VERSION 5.8 ;
BUSBITCHARS "[]" ;
DIVIDERCHAR "/" ;
UNITS
    DATABASE MICRONS 1000 ;
END UNITS

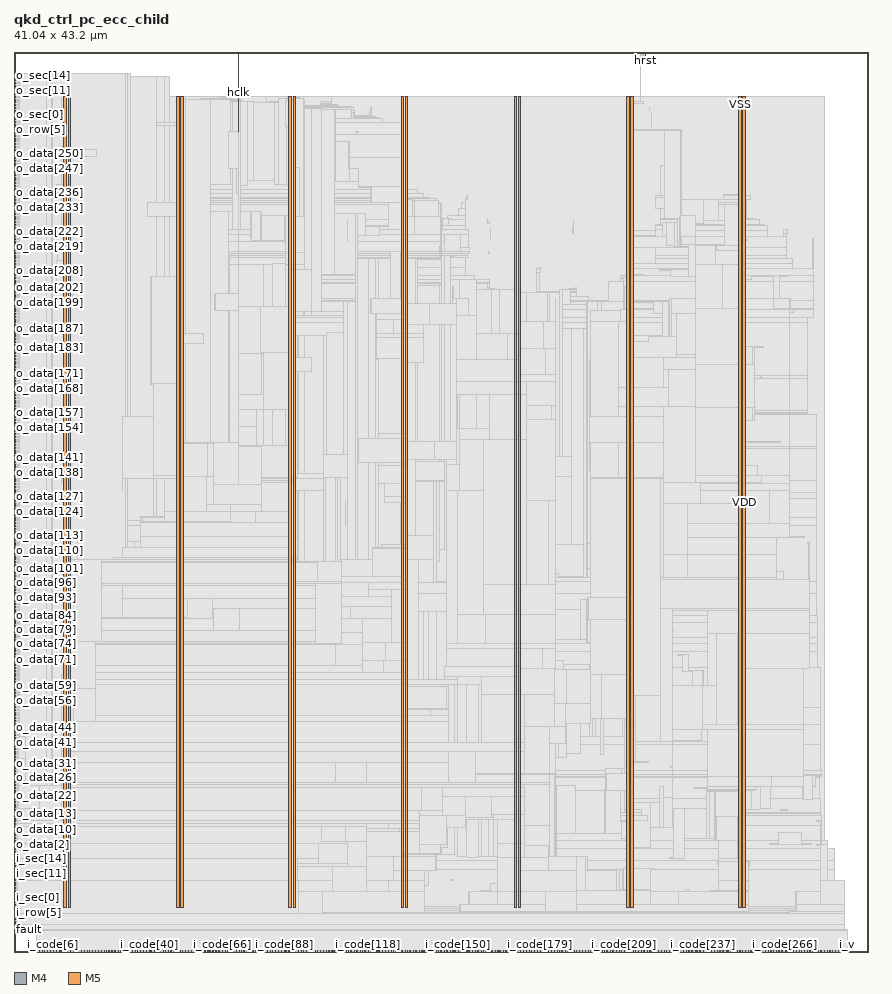
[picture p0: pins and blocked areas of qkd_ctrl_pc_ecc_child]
MACRO qkd_ctrl_pc_ecc_child
  FOREIGN qkd_ctrl_pc_ecc_child 0 0 ;
  CLASS BLOCK ;
  SIZE 41.04 BY 43.2 ;
  PIN fault
    DIRECTION OUTPUT ;
    USE SIGNAL ;
    PORT
      LAYER M4 ;
        RECT  0 1.056 0.084 1.08 ;
    END
  END fault
  PIN hclk
    DIRECTION INPUT ;
    USE SIGNAL ;
    PORT
      LAYER M5 ;
        RECT  10.752 43.116 10.776 43.2 ;
    END
    PORT
      LAYER M5 ;
        RECT  10.752 39.395 10.776 43.152 ;
    END
  END hclk
  PIN hrst
    DIRECTION INPUT ;
    USE SIGNAL ;
    PORT
      LAYER M5 ;
        RECT  30.288 43.116 30.312 43.2 ;
    END
    PORT
      LAYER M5 ;
        RECT  30.288 43.045 30.312 43.152 ;
    END
  END hrst
  PIN i_code[0]
    DIRECTION INPUT ;
    USE SIGNAL ;
    PORT
      LAYER M5 ;
        RECT  1.056 0 1.08 0.084 ;
    END
  END i_code[0]
  PIN i_code[100]
    DIRECTION INPUT ;
    USE SIGNAL ;
    PORT
      LAYER M5 ;
        RECT  14.544 0 14.568 0.084 ;
    END
  END i_code[100]
  PIN i_code[101]
    DIRECTION INPUT ;
    USE SIGNAL ;
    PORT
      LAYER M5 ;
        RECT  14.688 0 14.712 0.084 ;
    END
  END i_code[101]
  PIN i_code[102]
    DIRECTION INPUT ;
    USE SIGNAL ;
    PORT
      LAYER M5 ;
        RECT  14.832 0 14.856 0.084 ;
    END
  END i_code[102]
  PIN i_code[103]
    DIRECTION INPUT ;
    USE SIGNAL ;
    PORT
      LAYER M5 ;
        RECT  14.976 0 15 0.084 ;
    END
  END i_code[103]
  PIN i_code[104]
    DIRECTION INPUT ;
    USE SIGNAL ;
    PORT
      LAYER M5 ;
        RECT  15.12 0 15.144 0.084 ;
    END
  END i_code[104]
  PIN i_code[105]
    DIRECTION INPUT ;
    USE SIGNAL ;
    PORT
      LAYER M5 ;
        RECT  15.264 0 15.288 0.084 ;
    END
  END i_code[105]
  PIN i_code[106]
    DIRECTION INPUT ;
    USE SIGNAL ;
    PORT
      LAYER M5 ;
        RECT  15.36 0 15.384 0.084 ;
    END
  END i_code[106]
  PIN i_code[107]
    DIRECTION INPUT ;
    USE SIGNAL ;
    PORT
      LAYER M5 ;
        RECT  15.504 0 15.528 0.084 ;
    END
  END i_code[107]
  PIN i_code[108]
    DIRECTION INPUT ;
    USE SIGNAL ;
    PORT
      LAYER M5 ;
        RECT  15.648 0 15.672 0.084 ;
    END
  END i_code[108]
  PIN i_code[109]
    DIRECTION INPUT ;
    USE SIGNAL ;
    PORT
      LAYER M5 ;
        RECT  15.792 0 15.816 0.084 ;
    END
  END i_code[109]
  PIN i_code[10]
    DIRECTION INPUT ;
    USE SIGNAL ;
    PORT
      LAYER M5 ;
        RECT  2.4 0 2.424 0.084 ;
    END
  END i_code[10]
  PIN i_code[110]
    DIRECTION INPUT ;
    USE SIGNAL ;
    PORT
      LAYER M5 ;
        RECT  15.936 0 15.96 0.084 ;
    END
  END i_code[110]
  PIN i_code[111]
    DIRECTION INPUT ;
    USE SIGNAL ;
    PORT
      LAYER M5 ;
        RECT  16.032 0 16.056 0.084 ;
    END
  END i_code[111]
  PIN i_code[112]
    DIRECTION INPUT ;
    USE SIGNAL ;
    PORT
      LAYER M5 ;
        RECT  16.176 0 16.2 0.084 ;
    END
  END i_code[112]
  PIN i_code[113]
    DIRECTION INPUT ;
    USE SIGNAL ;
    PORT
      LAYER M5 ;
        RECT  16.32 0 16.344 0.084 ;
    END
  END i_code[113]
  PIN i_code[114]
    DIRECTION INPUT ;
    USE SIGNAL ;
    PORT
      LAYER M5 ;
        RECT  16.464 0 16.488 0.084 ;
    END
  END i_code[114]
  PIN i_code[115]
    DIRECTION INPUT ;
    USE SIGNAL ;
    PORT
      LAYER M5 ;
        RECT  16.608 0 16.632 0.084 ;
    END
  END i_code[115]
  PIN i_code[116]
    DIRECTION INPUT ;
    USE SIGNAL ;
    PORT
      LAYER M5 ;
        RECT  16.704 0 16.728 0.084 ;
    END
  END i_code[116]
  PIN i_code[117]
    DIRECTION INPUT ;
    USE SIGNAL ;
    PORT
      LAYER M5 ;
        RECT  16.848 0 16.872 0.084 ;
    END
  END i_code[117]
  PIN i_code[118]
    DIRECTION INPUT ;
    USE SIGNAL ;
    PORT
      LAYER M5 ;
        RECT  16.992 0 17.016 0.084 ;
    END
  END i_code[118]
  PIN i_code[119]
    DIRECTION INPUT ;
    USE SIGNAL ;
    PORT
      LAYER M5 ;
        RECT  17.136 0 17.16 0.084 ;
    END
  END i_code[119]
  PIN i_code[11]
    DIRECTION INPUT ;
    USE SIGNAL ;
    PORT
      LAYER M5 ;
        RECT  2.544 0 2.568 0.084 ;
    END
  END i_code[11]
  PIN i_code[120]
    DIRECTION INPUT ;
    USE SIGNAL ;
    PORT
      LAYER M5 ;
        RECT  17.28 0 17.304 0.084 ;
    END
  END i_code[120]
  PIN i_code[121]
    DIRECTION INPUT ;
    USE SIGNAL ;
    PORT
      LAYER M5 ;
        RECT  17.424 0 17.448 0.084 ;
    END
  END i_code[121]
  PIN i_code[122]
    DIRECTION INPUT ;
    USE SIGNAL ;
    PORT
      LAYER M5 ;
        RECT  17.52 0 17.544 0.084 ;
    END
  END i_code[122]
  PIN i_code[123]
    DIRECTION INPUT ;
    USE SIGNAL ;
    PORT
      LAYER M5 ;
        RECT  17.664 0 17.688 0.084 ;
    END
  END i_code[123]
  PIN i_code[124]
    DIRECTION INPUT ;
    USE SIGNAL ;
    PORT
      LAYER M5 ;
        RECT  17.808 0 17.832 0.084 ;
    END
  END i_code[124]
  PIN i_code[125]
    DIRECTION INPUT ;
    USE SIGNAL ;
    PORT
      LAYER M5 ;
        RECT  17.952 0 17.976 0.084 ;
    END
  END i_code[125]
  PIN i_code[126]
    DIRECTION INPUT ;
    USE SIGNAL ;
    PORT
      LAYER M5 ;
        RECT  18.096 0 18.12 0.084 ;
    END
  END i_code[126]
  PIN i_code[127]
    DIRECTION INPUT ;
    USE SIGNAL ;
    PORT
      LAYER M5 ;
        RECT  18.192 0 18.216 0.084 ;
    END
  END i_code[127]
  PIN i_code[128]
    DIRECTION INPUT ;
    USE SIGNAL ;
    PORT
      LAYER M5 ;
        RECT  18.336 0 18.36 0.084 ;
    END
  END i_code[128]
  PIN i_code[129]
    DIRECTION INPUT ;
    USE SIGNAL ;
    PORT
      LAYER M5 ;
        RECT  18.48 0 18.504 0.084 ;
    END
  END i_code[129]
  PIN i_code[12]
    DIRECTION INPUT ;
    USE SIGNAL ;
    PORT
      LAYER M5 ;
        RECT  2.688 0 2.712 0.084 ;
    END
  END i_code[12]
  PIN i_code[130]
    DIRECTION INPUT ;
    USE SIGNAL ;
    PORT
      LAYER M5 ;
        RECT  18.624 0 18.648 0.084 ;
    END
  END i_code[130]
  PIN i_code[131]
    DIRECTION INPUT ;
    USE SIGNAL ;
    PORT
      LAYER M5 ;
        RECT  18.768 0 18.792 0.084 ;
    END
  END i_code[131]
  PIN i_code[132]
    DIRECTION INPUT ;
    USE SIGNAL ;
    PORT
      LAYER M5 ;
        RECT  18.864 0 18.888 0.084 ;
    END
  END i_code[132]
  PIN i_code[133]
    DIRECTION INPUT ;
    USE SIGNAL ;
    PORT
      LAYER M5 ;
        RECT  19.008 0 19.032 0.084 ;
    END
  END i_code[133]
  PIN i_code[134]
    DIRECTION INPUT ;
    USE SIGNAL ;
    PORT
      LAYER M5 ;
        RECT  19.152 0 19.176 0.084 ;
    END
  END i_code[134]
  PIN i_code[135]
    DIRECTION INPUT ;
    USE SIGNAL ;
    PORT
      LAYER M5 ;
        RECT  19.296 0 19.32 0.084 ;
    END
  END i_code[135]
  PIN i_code[136]
    DIRECTION INPUT ;
    USE SIGNAL ;
    PORT
      LAYER M5 ;
        RECT  19.44 0 19.464 0.084 ;
    END
  END i_code[136]
  PIN i_code[137]
    DIRECTION INPUT ;
    USE SIGNAL ;
    PORT
      LAYER M5 ;
        RECT  19.584 0 19.608 0.084 ;
    END
  END i_code[137]
  PIN i_code[138]
    DIRECTION INPUT ;
    USE SIGNAL ;
    PORT
      LAYER M5 ;
        RECT  19.68 0 19.704 0.084 ;
    END
  END i_code[138]
  PIN i_code[139]
    DIRECTION INPUT ;
    USE SIGNAL ;
    PORT
      LAYER M5 ;
        RECT  19.824 0 19.848 0.084 ;
    END
  END i_code[139]
  PIN i_code[13]
    DIRECTION INPUT ;
    USE SIGNAL ;
    PORT
      LAYER M5 ;
        RECT  2.832 0 2.856 0.084 ;
    END
  END i_code[13]
  PIN i_code[140]
    DIRECTION INPUT ;
    USE SIGNAL ;
    PORT
      LAYER M5 ;
        RECT  19.968 0 19.992 0.084 ;
    END
  END i_code[140]
  PIN i_code[141]
    DIRECTION INPUT ;
    USE SIGNAL ;
    PORT
      LAYER M5 ;
        RECT  20.112 0 20.136 0.084 ;
    END
  END i_code[141]
  PIN i_code[142]
    DIRECTION INPUT ;
    USE SIGNAL ;
    PORT
      LAYER M5 ;
        RECT  20.256 0 20.28 0.084 ;
    END
  END i_code[142]
  PIN i_code[143]
    DIRECTION INPUT ;
    USE SIGNAL ;
    PORT
      LAYER M5 ;
        RECT  20.352 0 20.376 0.084 ;
    END
  END i_code[143]
  PIN i_code[144]
    DIRECTION INPUT ;
    USE SIGNAL ;
    PORT
      LAYER M5 ;
        RECT  20.496 0 20.52 0.084 ;
    END
  END i_code[144]
  PIN i_code[145]
    DIRECTION INPUT ;
    USE SIGNAL ;
    PORT
      LAYER M5 ;
        RECT  20.64 0 20.664 0.084 ;
    END
  END i_code[145]
  PIN i_code[146]
    DIRECTION INPUT ;
    USE SIGNAL ;
    PORT
      LAYER M5 ;
        RECT  20.784 0 20.808 0.084 ;
    END
  END i_code[146]
  PIN i_code[147]
    DIRECTION INPUT ;
    USE SIGNAL ;
    PORT
      LAYER M5 ;
        RECT  20.928 0 20.952 0.084 ;
    END
  END i_code[147]
  PIN i_code[148]
    DIRECTION INPUT ;
    USE SIGNAL ;
    PORT
      LAYER M5 ;
        RECT  21.072 0 21.096 0.084 ;
    END
  END i_code[148]
  PIN i_code[149]
    DIRECTION INPUT ;
    USE SIGNAL ;
    PORT
      LAYER M5 ;
        RECT  21.168 0 21.192 0.084 ;
    END
  END i_code[149]
  PIN i_code[14]
    DIRECTION INPUT ;
    USE SIGNAL ;
    PORT
      LAYER M5 ;
        RECT  2.928 0 2.952 0.084 ;
    END
  END i_code[14]
  PIN i_code[150]
    DIRECTION INPUT ;
    USE SIGNAL ;
    PORT
      LAYER M5 ;
        RECT  21.312 0 21.336 0.084 ;
    END
  END i_code[150]
  PIN i_code[151]
    DIRECTION INPUT ;
    USE SIGNAL ;
    PORT
      LAYER M5 ;
        RECT  21.456 0 21.48 0.084 ;
    END
  END i_code[151]
  PIN i_code[152]
    DIRECTION INPUT ;
    USE SIGNAL ;
    PORT
      LAYER M5 ;
        RECT  21.6 0 21.624 0.084 ;
    END
  END i_code[152]
  PIN i_code[153]
    DIRECTION INPUT ;
    USE SIGNAL ;
    PORT
      LAYER M5 ;
        RECT  21.744 0 21.768 0.084 ;
    END
  END i_code[153]
  PIN i_code[154]
    DIRECTION INPUT ;
    USE SIGNAL ;
    PORT
      LAYER M5 ;
        RECT  21.84 0 21.864 0.084 ;
    END
  END i_code[154]
  PIN i_code[155]
    DIRECTION INPUT ;
    USE SIGNAL ;
    PORT
      LAYER M5 ;
        RECT  21.984 0 22.008 0.084 ;
    END
  END i_code[155]
  PIN i_code[156]
    DIRECTION INPUT ;
    USE SIGNAL ;
    PORT
      LAYER M5 ;
        RECT  22.128 0 22.152 0.084 ;
    END
  END i_code[156]
  PIN i_code[157]
    DIRECTION INPUT ;
    USE SIGNAL ;
    PORT
      LAYER M5 ;
        RECT  22.272 0 22.296 0.084 ;
    END
  END i_code[157]
  PIN i_code[158]
    DIRECTION INPUT ;
    USE SIGNAL ;
    PORT
      LAYER M5 ;
        RECT  22.416 0 22.44 0.084 ;
    END
  END i_code[158]
  PIN i_code[159]
    DIRECTION INPUT ;
    USE SIGNAL ;
    PORT
      LAYER M5 ;
        RECT  22.512 0 22.536 0.084 ;
    END
  END i_code[159]
  PIN i_code[15]
    DIRECTION INPUT ;
    USE SIGNAL ;
    PORT
      LAYER M5 ;
        RECT  3.072 0 3.096 0.084 ;
    END
  END i_code[15]
  PIN i_code[160]
    DIRECTION INPUT ;
    USE SIGNAL ;
    PORT
      LAYER M5 ;
        RECT  22.656 0 22.68 0.084 ;
    END
  END i_code[160]
  PIN i_code[161]
    DIRECTION INPUT ;
    USE SIGNAL ;
    PORT
      LAYER M5 ;
        RECT  22.8 0 22.824 0.084 ;
    END
  END i_code[161]
  PIN i_code[162]
    DIRECTION INPUT ;
    USE SIGNAL ;
    PORT
      LAYER M5 ;
        RECT  22.944 0 22.968 0.084 ;
    END
  END i_code[162]
  PIN i_code[163]
    DIRECTION INPUT ;
    USE SIGNAL ;
    PORT
      LAYER M5 ;
        RECT  23.088 0 23.112 0.084 ;
    END
  END i_code[163]
  PIN i_code[164]
    DIRECTION INPUT ;
    USE SIGNAL ;
    PORT
      LAYER M5 ;
        RECT  23.232 0 23.256 0.084 ;
    END
  END i_code[164]
  PIN i_code[165]
    DIRECTION INPUT ;
    USE SIGNAL ;
    PORT
      LAYER M5 ;
        RECT  23.328 0 23.352 0.084 ;
    END
  END i_code[165]
  PIN i_code[166]
    DIRECTION INPUT ;
    USE SIGNAL ;
    PORT
      LAYER M5 ;
        RECT  23.472 0 23.496 0.084 ;
    END
  END i_code[166]
  PIN i_code[167]
    DIRECTION INPUT ;
    USE SIGNAL ;
    PORT
      LAYER M5 ;
        RECT  23.616 0 23.64 0.084 ;
    END
  END i_code[167]
  PIN i_code[168]
    DIRECTION INPUT ;
    USE SIGNAL ;
    PORT
      LAYER M5 ;
        RECT  23.76 0 23.784 0.084 ;
    END
  END i_code[168]
  PIN i_code[169]
    DIRECTION INPUT ;
    USE SIGNAL ;
    PORT
      LAYER M5 ;
        RECT  23.904 0 23.928 0.084 ;
    END
  END i_code[169]
  PIN i_code[16]
    DIRECTION INPUT ;
    USE SIGNAL ;
    PORT
      LAYER M5 ;
        RECT  3.216 0 3.24 0.084 ;
    END
  END i_code[16]
  PIN i_code[170]
    DIRECTION INPUT ;
    USE SIGNAL ;
    PORT
      LAYER M5 ;
        RECT  24 0 24.024 0.084 ;
    END
  END i_code[170]
  PIN i_code[171]
    DIRECTION INPUT ;
    USE SIGNAL ;
    PORT
      LAYER M5 ;
        RECT  24.144 0 24.168 0.084 ;
    END
  END i_code[171]
  PIN i_code[172]
    DIRECTION INPUT ;
    USE SIGNAL ;
    PORT
      LAYER M5 ;
        RECT  24.288 0 24.312 0.084 ;
    END
  END i_code[172]
  PIN i_code[173]
    DIRECTION INPUT ;
    USE SIGNAL ;
    PORT
      LAYER M5 ;
        RECT  24.432 0 24.456 0.084 ;
    END
  END i_code[173]
  PIN i_code[174]
    DIRECTION INPUT ;
    USE SIGNAL ;
    PORT
      LAYER M5 ;
        RECT  24.576 0 24.6 0.084 ;
    END
  END i_code[174]
  PIN i_code[175]
    DIRECTION INPUT ;
    USE SIGNAL ;
    PORT
      LAYER M5 ;
        RECT  24.72 0 24.744 0.084 ;
    END
  END i_code[175]
  PIN i_code[176]
    DIRECTION INPUT ;
    USE SIGNAL ;
    PORT
      LAYER M5 ;
        RECT  24.816 0 24.84 0.084 ;
    END
  END i_code[176]
  PIN i_code[177]
    DIRECTION INPUT ;
    USE SIGNAL ;
    PORT
      LAYER M5 ;
        RECT  24.96 0 24.984 0.084 ;
    END
  END i_code[177]
  PIN i_code[178]
    DIRECTION INPUT ;
    USE SIGNAL ;
    PORT
      LAYER M5 ;
        RECT  25.104 0 25.128 0.084 ;
    END
  END i_code[178]
  PIN i_code[179]
    DIRECTION INPUT ;
    USE SIGNAL ;
    PORT
      LAYER M5 ;
        RECT  25.248 0 25.272 0.084 ;
    END
  END i_code[179]
  PIN i_code[17]
    DIRECTION INPUT ;
    USE SIGNAL ;
    PORT
      LAYER M5 ;
        RECT  3.36 0 3.384 0.084 ;
    END
  END i_code[17]
  PIN i_code[180]
    DIRECTION INPUT ;
    USE SIGNAL ;
    PORT
      LAYER M5 ;
        RECT  25.392 0 25.416 0.084 ;
    END
  END i_code[180]
  PIN i_code[181]
    DIRECTION INPUT ;
    USE SIGNAL ;
    PORT
      LAYER M5 ;
        RECT  25.488 0 25.512 0.084 ;
    END
  END i_code[181]
  PIN i_code[182]
    DIRECTION INPUT ;
    USE SIGNAL ;
    PORT
      LAYER M5 ;
        RECT  25.632 0 25.656 0.084 ;
    END
  END i_code[182]
  PIN i_code[183]
    DIRECTION INPUT ;
    USE SIGNAL ;
    PORT
      LAYER M5 ;
        RECT  25.776 0 25.8 0.084 ;
    END
  END i_code[183]
  PIN i_code[184]
    DIRECTION INPUT ;
    USE SIGNAL ;
    PORT
      LAYER M5 ;
        RECT  25.92 0 25.944 0.084 ;
    END
  END i_code[184]
  PIN i_code[185]
    DIRECTION INPUT ;
    USE SIGNAL ;
    PORT
      LAYER M5 ;
        RECT  26.064 0 26.088 0.084 ;
    END
  END i_code[185]
  PIN i_code[186]
    DIRECTION INPUT ;
    USE SIGNAL ;
    PORT
      LAYER M5 ;
        RECT  26.16 0 26.184 0.084 ;
    END
  END i_code[186]
  PIN i_code[187]
    DIRECTION INPUT ;
    USE SIGNAL ;
    PORT
      LAYER M5 ;
        RECT  26.304 0 26.328 0.084 ;
    END
  END i_code[187]
  PIN i_code[188]
    DIRECTION INPUT ;
    USE SIGNAL ;
    PORT
      LAYER M5 ;
        RECT  26.448 0 26.472 0.084 ;
    END
  END i_code[188]
  PIN i_code[189]
    DIRECTION INPUT ;
    USE SIGNAL ;
    PORT
      LAYER M5 ;
        RECT  26.592 0 26.616 0.084 ;
    END
  END i_code[189]
  PIN i_code[18]
    DIRECTION INPUT ;
    USE SIGNAL ;
    PORT
      LAYER M5 ;
        RECT  3.504 0 3.528 0.084 ;
    END
  END i_code[18]
  PIN i_code[190]
    DIRECTION INPUT ;
    USE SIGNAL ;
    PORT
      LAYER M5 ;
        RECT  26.736 0 26.76 0.084 ;
    END
  END i_code[190]
  PIN i_code[191]
    DIRECTION INPUT ;
    USE SIGNAL ;
    PORT
      LAYER M5 ;
        RECT  26.88 0 26.904 0.084 ;
    END
  END i_code[191]
  PIN i_code[192]
    DIRECTION INPUT ;
    USE SIGNAL ;
    PORT
      LAYER M5 ;
        RECT  26.976 0 27 0.084 ;
    END
  END i_code[192]
  PIN i_code[193]
    DIRECTION INPUT ;
    USE SIGNAL ;
    PORT
      LAYER M5 ;
        RECT  27.12 0 27.144 0.084 ;
    END
  END i_code[193]
  PIN i_code[194]
    DIRECTION INPUT ;
    USE SIGNAL ;
    PORT
      LAYER M5 ;
        RECT  27.264 0 27.288 0.084 ;
    END
  END i_code[194]
  PIN i_code[195]
    DIRECTION INPUT ;
    USE SIGNAL ;
    PORT
      LAYER M5 ;
        RECT  27.408 0 27.432 0.084 ;
    END
  END i_code[195]
  PIN i_code[196]
    DIRECTION INPUT ;
    USE SIGNAL ;
    PORT
      LAYER M5 ;
        RECT  27.552 0 27.576 0.084 ;
    END
  END i_code[196]
  PIN i_code[197]
    DIRECTION INPUT ;
    USE SIGNAL ;
    PORT
      LAYER M5 ;
        RECT  27.648 0 27.672 0.084 ;
    END
  END i_code[197]
  PIN i_code[198]
    DIRECTION INPUT ;
    USE SIGNAL ;
    PORT
      LAYER M5 ;
        RECT  27.792 0 27.816 0.084 ;
    END
  END i_code[198]
  PIN i_code[199]
    DIRECTION INPUT ;
    USE SIGNAL ;
    PORT
      LAYER M5 ;
        RECT  27.936 0 27.96 0.084 ;
    END
  END i_code[199]
  PIN i_code[19]
    DIRECTION INPUT ;
    USE SIGNAL ;
    PORT
      LAYER M5 ;
        RECT  3.6 0 3.624 0.084 ;
    END
  END i_code[19]
  PIN i_code[1]
    DIRECTION INPUT ;
    USE SIGNAL ;
    PORT
      LAYER M5 ;
        RECT  1.2 0 1.224 0.084 ;
    END
  END i_code[1]
  PIN i_code[200]
    DIRECTION INPUT ;
    USE SIGNAL ;
    PORT
      LAYER M5 ;
        RECT  28.08 0 28.104 0.084 ;
    END
  END i_code[200]
  PIN i_code[201]
    DIRECTION INPUT ;
    USE SIGNAL ;
    PORT
      LAYER M5 ;
        RECT  28.224 0 28.248 0.084 ;
    END
  END i_code[201]
  PIN i_code[202]
    DIRECTION INPUT ;
    USE SIGNAL ;
    PORT
      LAYER M5 ;
        RECT  28.32 0 28.344 0.084 ;
    END
  END i_code[202]
  PIN i_code[203]
    DIRECTION INPUT ;
    USE SIGNAL ;
    PORT
      LAYER M5 ;
        RECT  28.464 0 28.488 0.084 ;
    END
  END i_code[203]
  PIN i_code[204]
    DIRECTION INPUT ;
    USE SIGNAL ;
    PORT
      LAYER M5 ;
        RECT  28.608 0 28.632 0.084 ;
    END
  END i_code[204]
  PIN i_code[205]
    DIRECTION INPUT ;
    USE SIGNAL ;
    PORT
      LAYER M5 ;
        RECT  28.752 0 28.776 0.084 ;
    END
  END i_code[205]
  PIN i_code[206]
    DIRECTION INPUT ;
    USE SIGNAL ;
    PORT
      LAYER M5 ;
        RECT  28.896 0 28.92 0.084 ;
    END
  END i_code[206]
  PIN i_code[207]
    DIRECTION INPUT ;
    USE SIGNAL ;
    PORT
      LAYER M5 ;
        RECT  29.04 0 29.064 0.084 ;
    END
  END i_code[207]
  PIN i_code[208]
    DIRECTION INPUT ;
    USE SIGNAL ;
    PORT
      LAYER M5 ;
        RECT  29.136 0 29.16 0.084 ;
    END
  END i_code[208]
  PIN i_code[209]
    DIRECTION INPUT ;
    USE SIGNAL ;
    PORT
      LAYER M5 ;
        RECT  29.28 0 29.304 0.084 ;
    END
  END i_code[209]
  PIN i_code[20]
    DIRECTION INPUT ;
    USE SIGNAL ;
    PORT
      LAYER M5 ;
        RECT  3.744 0 3.768 0.084 ;
    END
  END i_code[20]
  PIN i_code[210]
    DIRECTION INPUT ;
    USE SIGNAL ;
    PORT
      LAYER M5 ;
        RECT  29.424 0 29.448 0.084 ;
    END
  END i_code[210]
  PIN i_code[211]
    DIRECTION INPUT ;
    USE SIGNAL ;
    PORT
      LAYER M5 ;
        RECT  29.568 0 29.592 0.084 ;
    END
  END i_code[211]
  PIN i_code[212]
    DIRECTION INPUT ;
    USE SIGNAL ;
    PORT
      LAYER M5 ;
        RECT  29.712 0 29.736 0.084 ;
    END
  END i_code[212]
  PIN i_code[213]
    DIRECTION INPUT ;
    USE SIGNAL ;
    PORT
      LAYER M5 ;
        RECT  29.808 0 29.832 0.084 ;
    END
  END i_code[213]
  PIN i_code[214]
    DIRECTION INPUT ;
    USE SIGNAL ;
    PORT
      LAYER M5 ;
        RECT  29.952 0 29.976 0.084 ;
    END
  END i_code[214]
  PIN i_code[215]
    DIRECTION INPUT ;
    USE SIGNAL ;
    PORT
      LAYER M5 ;
        RECT  30.096 0 30.12 0.084 ;
    END
  END i_code[215]
  PIN i_code[216]
    DIRECTION INPUT ;
    USE SIGNAL ;
    PORT
      LAYER M5 ;
        RECT  30.24 0 30.264 0.084 ;
    END
  END i_code[216]
  PIN i_code[217]
    DIRECTION INPUT ;
    USE SIGNAL ;
    PORT
      LAYER M5 ;
        RECT  30.384 0 30.408 0.084 ;
    END
  END i_code[217]
  PIN i_code[218]
    DIRECTION INPUT ;
    USE SIGNAL ;
    PORT
      LAYER M5 ;
        RECT  30.528 0 30.552 0.084 ;
    END
  END i_code[218]
  PIN i_code[219]
    DIRECTION INPUT ;
    USE SIGNAL ;
    PORT
      LAYER M5 ;
        RECT  30.624 0 30.648 0.084 ;
    END
  END i_code[219]
  PIN i_code[21]
    DIRECTION INPUT ;
    USE SIGNAL ;
    PORT
      LAYER M5 ;
        RECT  3.888 0 3.912 0.084 ;
    END
  END i_code[21]
  PIN i_code[220]
    DIRECTION INPUT ;
    USE SIGNAL ;
    PORT
      LAYER M5 ;
        RECT  30.768 0 30.792 0.084 ;
    END
  END i_code[220]
  PIN i_code[221]
    DIRECTION INPUT ;
    USE SIGNAL ;
    PORT
      LAYER M5 ;
        RECT  30.912 0 30.936 0.084 ;
    END
  END i_code[221]
  PIN i_code[222]
    DIRECTION INPUT ;
    USE SIGNAL ;
    PORT
      LAYER M5 ;
        RECT  31.056 0 31.08 0.084 ;
    END
  END i_code[222]
  PIN i_code[223]
    DIRECTION INPUT ;
    USE SIGNAL ;
    PORT
      LAYER M5 ;
        RECT  31.2 0 31.224 0.084 ;
    END
  END i_code[223]
  PIN i_code[224]
    DIRECTION INPUT ;
    USE SIGNAL ;
    PORT
      LAYER M5 ;
        RECT  31.296 0 31.32 0.084 ;
    END
  END i_code[224]
  PIN i_code[225]
    DIRECTION INPUT ;
    USE SIGNAL ;
    PORT
      LAYER M5 ;
        RECT  31.44 0 31.464 0.084 ;
    END
  END i_code[225]
  PIN i_code[226]
    DIRECTION INPUT ;
    USE SIGNAL ;
    PORT
      LAYER M5 ;
        RECT  31.584 0 31.608 0.084 ;
    END
  END i_code[226]
  PIN i_code[227]
    DIRECTION INPUT ;
    USE SIGNAL ;
    PORT
      LAYER M5 ;
        RECT  31.728 0 31.752 0.084 ;
    END
  END i_code[227]
  PIN i_code[228]
    DIRECTION INPUT ;
    USE SIGNAL ;
    PORT
      LAYER M5 ;
        RECT  31.872 0 31.896 0.084 ;
    END
  END i_code[228]
  PIN i_code[229]
    DIRECTION INPUT ;
    USE SIGNAL ;
    PORT
      LAYER M5 ;
        RECT  31.968 0 31.992 0.084 ;
    END
  END i_code[229]
  PIN i_code[22]
    DIRECTION INPUT ;
    USE SIGNAL ;
    PORT
      LAYER M5 ;
        RECT  4.032 0 4.056 0.084 ;
    END
  END i_code[22]
  PIN i_code[230]
    DIRECTION INPUT ;
    USE SIGNAL ;
    PORT
      LAYER M5 ;
        RECT  32.112 0 32.136 0.084 ;
    END
  END i_code[230]
  PIN i_code[231]
    DIRECTION INPUT ;
    USE SIGNAL ;
    PORT
      LAYER M5 ;
        RECT  32.256 0 32.28 0.084 ;
    END
  END i_code[231]
  PIN i_code[232]
    DIRECTION INPUT ;
    USE SIGNAL ;
    PORT
      LAYER M5 ;
        RECT  32.4 0 32.424 0.084 ;
    END
  END i_code[232]
  PIN i_code[233]
    DIRECTION INPUT ;
    USE SIGNAL ;
    PORT
      LAYER M5 ;
        RECT  32.544 0 32.568 0.084 ;
    END
  END i_code[233]
  PIN i_code[234]
    DIRECTION INPUT ;
    USE SIGNAL ;
    PORT
      LAYER M5 ;
        RECT  32.688 0 32.712 0.084 ;
    END
  END i_code[234]
  PIN i_code[235]
    DIRECTION INPUT ;
    USE SIGNAL ;
    PORT
      LAYER M5 ;
        RECT  32.784 0 32.808 0.084 ;
    END
  END i_code[235]
  PIN i_code[236]
    DIRECTION INPUT ;
    USE SIGNAL ;
    PORT
      LAYER M5 ;
        RECT  32.928 0 32.952 0.084 ;
    END
  END i_code[236]
  PIN i_code[237]
    DIRECTION INPUT ;
    USE SIGNAL ;
    PORT
      LAYER M5 ;
        RECT  33.072 0 33.096 0.084 ;
    END
  END i_code[237]
  PIN i_code[238]
    DIRECTION INPUT ;
    USE SIGNAL ;
    PORT
      LAYER M5 ;
        RECT  33.216 0 33.24 0.084 ;
    END
  END i_code[238]
  PIN i_code[239]
    DIRECTION INPUT ;
    USE SIGNAL ;
    PORT
      LAYER M5 ;
        RECT  33.36 0 33.384 0.084 ;
    END
  END i_code[239]
  PIN i_code[23]
    DIRECTION INPUT ;
    USE SIGNAL ;
    PORT
      LAYER M5 ;
        RECT  4.176 0 4.2 0.084 ;
    END
  END i_code[23]
  PIN i_code[240]
    DIRECTION INPUT ;
    USE SIGNAL ;
    PORT
      LAYER M5 ;
        RECT  33.456 0 33.48 0.084 ;
    END
  END i_code[240]
  PIN i_code[241]
    DIRECTION INPUT ;
    USE SIGNAL ;
    PORT
      LAYER M5 ;
        RECT  33.6 0 33.624 0.084 ;
    END
  END i_code[241]
  PIN i_code[242]
    DIRECTION INPUT ;
    USE SIGNAL ;
    PORT
      LAYER M5 ;
        RECT  33.744 0 33.768 0.084 ;
    END
  END i_code[242]
  PIN i_code[243]
    DIRECTION INPUT ;
    USE SIGNAL ;
    PORT
      LAYER M5 ;
        RECT  33.888 0 33.912 0.084 ;
    END
  END i_code[243]
  PIN i_code[244]
    DIRECTION INPUT ;
    USE SIGNAL ;
    PORT
      LAYER M5 ;
        RECT  34.032 0 34.056 0.084 ;
    END
  END i_code[244]
  PIN i_code[245]
    DIRECTION INPUT ;
    USE SIGNAL ;
    PORT
      LAYER M5 ;
        RECT  34.176 0 34.2 0.084 ;
    END
  END i_code[245]
  PIN i_code[246]
    DIRECTION INPUT ;
    USE SIGNAL ;
    PORT
      LAYER M5 ;
        RECT  34.272 0 34.296 0.084 ;
    END
  END i_code[246]
  PIN i_code[247]
    DIRECTION INPUT ;
    USE SIGNAL ;
    PORT
      LAYER M5 ;
        RECT  34.416 0 34.44 0.084 ;
    END
  END i_code[247]
  PIN i_code[248]
    DIRECTION INPUT ;
    USE SIGNAL ;
    PORT
      LAYER M5 ;
        RECT  34.56 0 34.584 0.084 ;
    END
  END i_code[248]
  PIN i_code[249]
    DIRECTION INPUT ;
    USE SIGNAL ;
    PORT
      LAYER M5 ;
        RECT  34.704 0 34.728 0.084 ;
    END
  END i_code[249]
  PIN i_code[24]
    DIRECTION INPUT ;
    USE SIGNAL ;
    PORT
      LAYER M5 ;
        RECT  4.32 0 4.344 0.084 ;
    END
  END i_code[24]
  PIN i_code[250]
    DIRECTION INPUT ;
    USE SIGNAL ;
    PORT
      LAYER M5 ;
        RECT  34.848 0 34.872 0.084 ;
    END
  END i_code[250]
  PIN i_code[251]
    DIRECTION INPUT ;
    USE SIGNAL ;
    PORT
      LAYER M5 ;
        RECT  34.944 0 34.968 0.084 ;
    END
  END i_code[251]
  PIN i_code[252]
    DIRECTION INPUT ;
    USE SIGNAL ;
    PORT
      LAYER M5 ;
        RECT  35.088 0 35.112 0.084 ;
    END
  END i_code[252]
  PIN i_code[253]
    DIRECTION INPUT ;
    USE SIGNAL ;
    PORT
      LAYER M5 ;
        RECT  35.232 0 35.256 0.084 ;
    END
  END i_code[253]
  PIN i_code[254]
    DIRECTION INPUT ;
    USE SIGNAL ;
    PORT
      LAYER M5 ;
        RECT  35.376 0 35.4 0.084 ;
    END
  END i_code[254]
  PIN i_code[255]
    DIRECTION INPUT ;
    USE SIGNAL ;
    PORT
      LAYER M5 ;
        RECT  35.52 0 35.544 0.084 ;
    END
  END i_code[255]
  PIN i_code[256]
    DIRECTION INPUT ;
    USE SIGNAL ;
    PORT
      LAYER M5 ;
        RECT  35.616 0 35.64 0.084 ;
    END
  END i_code[256]
  PIN i_code[257]
    DIRECTION INPUT ;
    USE SIGNAL ;
    PORT
      LAYER M5 ;
        RECT  35.76 0 35.784 0.084 ;
    END
  END i_code[257]
  PIN i_code[258]
    DIRECTION INPUT ;
    USE SIGNAL ;
    PORT
      LAYER M5 ;
        RECT  35.904 0 35.928 0.084 ;
    END
  END i_code[258]
  PIN i_code[259]
    DIRECTION INPUT ;
    USE SIGNAL ;
    PORT
      LAYER M5 ;
        RECT  36.048 0 36.072 0.084 ;
    END
  END i_code[259]
  PIN i_code[25]
    DIRECTION INPUT ;
    USE SIGNAL ;
    PORT
      LAYER M5 ;
        RECT  4.416 0 4.44 0.084 ;
    END
  END i_code[25]
  PIN i_code[260]
    DIRECTION INPUT ;
    USE SIGNAL ;
    PORT
      LAYER M5 ;
        RECT  36.192 0 36.216 0.084 ;
    END
  END i_code[260]
  PIN i_code[261]
    DIRECTION INPUT ;
    USE SIGNAL ;
    PORT
      LAYER M5 ;
        RECT  36.336 0 36.36 0.084 ;
    END
  END i_code[261]
  PIN i_code[262]
    DIRECTION INPUT ;
    USE SIGNAL ;
    PORT
      LAYER M5 ;
        RECT  36.432 0 36.456 0.084 ;
    END
  END i_code[262]
  PIN i_code[263]
    DIRECTION INPUT ;
    USE SIGNAL ;
    PORT
      LAYER M5 ;
        RECT  36.576 0 36.6 0.084 ;
    END
  END i_code[263]
  PIN i_code[264]
    DIRECTION INPUT ;
    USE SIGNAL ;
    PORT
      LAYER M5 ;
        RECT  36.72 0 36.744 0.084 ;
    END
  END i_code[264]
  PIN i_code[265]
    DIRECTION INPUT ;
    USE SIGNAL ;
    PORT
      LAYER M5 ;
        RECT  36.864 0 36.888 0.084 ;
    END
  END i_code[265]
  PIN i_code[266]
    DIRECTION INPUT ;
    USE SIGNAL ;
    PORT
      LAYER M5 ;
        RECT  37.008 0 37.032 0.084 ;
    END
  END i_code[266]
  PIN i_code[267]
    DIRECTION INPUT ;
    USE SIGNAL ;
    PORT
      LAYER M5 ;
        RECT  37.104 0 37.128 0.084 ;
    END
  END i_code[267]
  PIN i_code[268]
    DIRECTION INPUT ;
    USE SIGNAL ;
    PORT
      LAYER M5 ;
        RECT  37.248 0 37.272 0.084 ;
    END
  END i_code[268]
  PIN i_code[269]
    DIRECTION INPUT ;
    USE SIGNAL ;
    PORT
      LAYER M5 ;
        RECT  37.392 0 37.416 0.084 ;
    END
  END i_code[269]
  PIN i_code[26]
    DIRECTION INPUT ;
    USE SIGNAL ;
    PORT
      LAYER M5 ;
        RECT  4.56 0 4.584 0.084 ;
    END
  END i_code[26]
  PIN i_code[270]
    DIRECTION INPUT ;
    USE SIGNAL ;
    PORT
      LAYER M5 ;
        RECT  37.536 0 37.56 0.084 ;
    END
  END i_code[270]
  PIN i_code[271]
    DIRECTION INPUT ;
    USE SIGNAL ;
    PORT
      LAYER M5 ;
        RECT  37.68 0 37.704 0.084 ;
    END
  END i_code[271]
  PIN i_code[272]
    DIRECTION INPUT ;
    USE SIGNAL ;
    PORT
      LAYER M5 ;
        RECT  37.776 0 37.8 0.084 ;
    END
  END i_code[272]
  PIN i_code[273]
    DIRECTION INPUT ;
    USE SIGNAL ;
    PORT
      LAYER M5 ;
        RECT  37.92 0 37.944 0.084 ;
    END
  END i_code[273]
  PIN i_code[274]
    DIRECTION INPUT ;
    USE SIGNAL ;
    PORT
      LAYER M5 ;
        RECT  38.064 0 38.088 0.084 ;
    END
  END i_code[274]
  PIN i_code[275]
    DIRECTION INPUT ;
    USE SIGNAL ;
    PORT
      LAYER M5 ;
        RECT  38.208 0 38.232 0.084 ;
    END
  END i_code[275]
  PIN i_code[276]
    DIRECTION INPUT ;
    USE SIGNAL ;
    PORT
      LAYER M5 ;
        RECT  38.352 0 38.376 0.084 ;
    END
  END i_code[276]
  PIN i_code[277]
    DIRECTION INPUT ;
    USE SIGNAL ;
    PORT
      LAYER M5 ;
        RECT  38.496 0 38.52 0.084 ;
    END
  END i_code[277]
  PIN i_code[278]
    DIRECTION INPUT ;
    USE SIGNAL ;
    PORT
      LAYER M5 ;
        RECT  38.592 0 38.616 0.084 ;
    END
  END i_code[278]
  PIN i_code[279]
    DIRECTION INPUT ;
    USE SIGNAL ;
    PORT
      LAYER M5 ;
        RECT  38.736 0 38.76 0.084 ;
    END
  END i_code[279]
  PIN i_code[27]
    DIRECTION INPUT ;
    USE SIGNAL ;
    PORT
      LAYER M5 ;
        RECT  4.704 0 4.728 0.084 ;
    END
  END i_code[27]
  PIN i_code[280]
    DIRECTION INPUT ;
    USE SIGNAL ;
    PORT
      LAYER M5 ;
        RECT  38.88 0 38.904 0.084 ;
    END
  END i_code[280]
  PIN i_code[281]
    DIRECTION INPUT ;
    USE SIGNAL ;
    PORT
      LAYER M5 ;
        RECT  39.024 0 39.048 0.084 ;
    END
  END i_code[281]
  PIN i_code[282]
    DIRECTION INPUT ;
    USE SIGNAL ;
    PORT
      LAYER M5 ;
        RECT  39.168 0 39.192 0.084 ;
    END
  END i_code[282]
  PIN i_code[283]
    DIRECTION INPUT ;
    USE SIGNAL ;
    PORT
      LAYER M5 ;
        RECT  39.264 0 39.288 0.084 ;
    END
  END i_code[283]
  PIN i_code[284]
    DIRECTION INPUT ;
    USE SIGNAL ;
    PORT
      LAYER M5 ;
        RECT  39.408 0 39.432 0.084 ;
    END
  END i_code[284]
  PIN i_code[285]
    DIRECTION INPUT ;
    USE SIGNAL ;
    PORT
      LAYER M5 ;
        RECT  39.552 0 39.576 0.084 ;
    END
  END i_code[285]
  PIN i_code[286]
    DIRECTION INPUT ;
    USE SIGNAL ;
    PORT
      LAYER M5 ;
        RECT  39.696 0 39.72 0.084 ;
    END
  END i_code[286]
  PIN i_code[287]
    DIRECTION INPUT ;
    USE SIGNAL ;
    PORT
      LAYER M5 ;
        RECT  39.84 0 39.864 0.084 ;
    END
  END i_code[287]
  PIN i_code[28]
    DIRECTION INPUT ;
    USE SIGNAL ;
    PORT
      LAYER M5 ;
        RECT  4.848 0 4.872 0.084 ;
    END
  END i_code[28]
  PIN i_code[29]
    DIRECTION INPUT ;
    USE SIGNAL ;
    PORT
      LAYER M5 ;
        RECT  4.992 0 5.016 0.084 ;
    END
  END i_code[29]
  PIN i_code[2]
    DIRECTION INPUT ;
    USE SIGNAL ;
    PORT
      LAYER M5 ;
        RECT  1.344 0 1.368 0.084 ;
    END
  END i_code[2]
  PIN i_code[30]
    DIRECTION INPUT ;
    USE SIGNAL ;
    PORT
      LAYER M5 ;
        RECT  5.088 0 5.112 0.084 ;
    END
  END i_code[30]
  PIN i_code[31]
    DIRECTION INPUT ;
    USE SIGNAL ;
    PORT
      LAYER M5 ;
        RECT  5.232 0 5.256 0.084 ;
    END
  END i_code[31]
  PIN i_code[32]
    DIRECTION INPUT ;
    USE SIGNAL ;
    PORT
      LAYER M5 ;
        RECT  5.376 0 5.4 0.084 ;
    END
  END i_code[32]
  PIN i_code[33]
    DIRECTION INPUT ;
    USE SIGNAL ;
    PORT
      LAYER M5 ;
        RECT  5.52 0 5.544 0.084 ;
    END
  END i_code[33]
  PIN i_code[34]
    DIRECTION INPUT ;
    USE SIGNAL ;
    PORT
      LAYER M5 ;
        RECT  5.664 0 5.688 0.084 ;
    END
  END i_code[34]
  PIN i_code[35]
    DIRECTION INPUT ;
    USE SIGNAL ;
    PORT
      LAYER M5 ;
        RECT  5.808 0 5.832 0.084 ;
    END
  END i_code[35]
  PIN i_code[36]
    DIRECTION INPUT ;
    USE SIGNAL ;
    PORT
      LAYER M5 ;
        RECT  5.904 0 5.928 0.084 ;
    END
  END i_code[36]
  PIN i_code[37]
    DIRECTION INPUT ;
    USE SIGNAL ;
    PORT
      LAYER M5 ;
        RECT  6.048 0 6.072 0.084 ;
    END
  END i_code[37]
  PIN i_code[38]
    DIRECTION INPUT ;
    USE SIGNAL ;
    PORT
      LAYER M5 ;
        RECT  6.192 0 6.216 0.084 ;
    END
  END i_code[38]
  PIN i_code[39]
    DIRECTION INPUT ;
    USE SIGNAL ;
    PORT
      LAYER M5 ;
        RECT  6.336 0 6.36 0.084 ;
    END
  END i_code[39]
  PIN i_code[3]
    DIRECTION INPUT ;
    USE SIGNAL ;
    PORT
      LAYER M5 ;
        RECT  1.44 0 1.464 0.084 ;
    END
  END i_code[3]
  PIN i_code[40]
    DIRECTION INPUT ;
    USE SIGNAL ;
    PORT
      LAYER M5 ;
        RECT  6.48 0 6.504 0.084 ;
    END
  END i_code[40]
  PIN i_code[41]
    DIRECTION INPUT ;
    USE SIGNAL ;
    PORT
      LAYER M5 ;
        RECT  6.576 0 6.6 0.084 ;
    END
  END i_code[41]
  PIN i_code[42]
    DIRECTION INPUT ;
    USE SIGNAL ;
    PORT
      LAYER M5 ;
        RECT  6.72 0 6.744 0.084 ;
    END
  END i_code[42]
  PIN i_code[43]
    DIRECTION INPUT ;
    USE SIGNAL ;
    PORT
      LAYER M5 ;
        RECT  6.864 0 6.888 0.084 ;
    END
  END i_code[43]
  PIN i_code[44]
    DIRECTION INPUT ;
    USE SIGNAL ;
    PORT
      LAYER M5 ;
        RECT  7.008 0 7.032 0.084 ;
    END
  END i_code[44]
  PIN i_code[45]
    DIRECTION INPUT ;
    USE SIGNAL ;
    PORT
      LAYER M5 ;
        RECT  7.152 0 7.176 0.084 ;
    END
  END i_code[45]
  PIN i_code[46]
    DIRECTION INPUT ;
    USE SIGNAL ;
    PORT
      LAYER M5 ;
        RECT  7.248 0 7.272 0.084 ;
    END
  END i_code[46]
  PIN i_code[47]
    DIRECTION INPUT ;
    USE SIGNAL ;
    PORT
      LAYER M5 ;
        RECT  7.392 0 7.416 0.084 ;
    END
  END i_code[47]
  PIN i_code[48]
    DIRECTION INPUT ;
    USE SIGNAL ;
    PORT
      LAYER M5 ;
        RECT  7.536 0 7.56 0.084 ;
    END
  END i_code[48]
  PIN i_code[49]
    DIRECTION INPUT ;
    USE SIGNAL ;
    PORT
      LAYER M5 ;
        RECT  7.68 0 7.704 0.084 ;
    END
  END i_code[49]
  PIN i_code[4]
    DIRECTION INPUT ;
    USE SIGNAL ;
    PORT
      LAYER M5 ;
        RECT  1.584 0 1.608 0.084 ;
    END
  END i_code[4]
  PIN i_code[50]
    DIRECTION INPUT ;
    USE SIGNAL ;
    PORT
      LAYER M5 ;
        RECT  7.824 0 7.848 0.084 ;
    END
  END i_code[50]
  PIN i_code[51]
    DIRECTION INPUT ;
    USE SIGNAL ;
    PORT
      LAYER M5 ;
        RECT  7.968 0 7.992 0.084 ;
    END
  END i_code[51]
  PIN i_code[52]
    DIRECTION INPUT ;
    USE SIGNAL ;
    PORT
      LAYER M5 ;
        RECT  8.064 0 8.088 0.084 ;
    END
  END i_code[52]
  PIN i_code[53]
    DIRECTION INPUT ;
    USE SIGNAL ;
    PORT
      LAYER M5 ;
        RECT  8.208 0 8.232 0.084 ;
    END
  END i_code[53]
  PIN i_code[54]
    DIRECTION INPUT ;
    USE SIGNAL ;
    PORT
      LAYER M5 ;
        RECT  8.352 0 8.376 0.084 ;
    END
  END i_code[54]
  PIN i_code[55]
    DIRECTION INPUT ;
    USE SIGNAL ;
    PORT
      LAYER M5 ;
        RECT  8.496 0 8.52 0.084 ;
    END
  END i_code[55]
  PIN i_code[56]
    DIRECTION INPUT ;
    USE SIGNAL ;
    PORT
      LAYER M5 ;
        RECT  8.64 0 8.664 0.084 ;
    END
  END i_code[56]
  PIN i_code[57]
    DIRECTION INPUT ;
    USE SIGNAL ;
    PORT
      LAYER M5 ;
        RECT  8.736 0 8.76 0.084 ;
    END
  END i_code[57]
  PIN i_code[58]
    DIRECTION INPUT ;
    USE SIGNAL ;
    PORT
      LAYER M5 ;
        RECT  8.88 0 8.904 0.084 ;
    END
  END i_code[58]
  PIN i_code[59]
    DIRECTION INPUT ;
    USE SIGNAL ;
    PORT
      LAYER M5 ;
        RECT  9.024 0 9.048 0.084 ;
    END
  END i_code[59]
  PIN i_code[5]
    DIRECTION INPUT ;
    USE SIGNAL ;
    PORT
      LAYER M5 ;
        RECT  1.728 0 1.752 0.084 ;
    END
  END i_code[5]
  PIN i_code[60]
    DIRECTION INPUT ;
    USE SIGNAL ;
    PORT
      LAYER M5 ;
        RECT  9.168 0 9.192 0.084 ;
    END
  END i_code[60]
  PIN i_code[61]
    DIRECTION INPUT ;
    USE SIGNAL ;
    PORT
      LAYER M5 ;
        RECT  9.312 0 9.336 0.084 ;
    END
  END i_code[61]
  PIN i_code[62]
    DIRECTION INPUT ;
    USE SIGNAL ;
    PORT
      LAYER M5 ;
        RECT  9.408 0 9.432 0.084 ;
    END
  END i_code[62]
  PIN i_code[63]
    DIRECTION INPUT ;
    USE SIGNAL ;
    PORT
      LAYER M5 ;
        RECT  9.552 0 9.576 0.084 ;
    END
  END i_code[63]
  PIN i_code[64]
    DIRECTION INPUT ;
    USE SIGNAL ;
    PORT
      LAYER M5 ;
        RECT  9.696 0 9.72 0.084 ;
    END
  END i_code[64]
  PIN i_code[65]
    DIRECTION INPUT ;
    USE SIGNAL ;
    PORT
      LAYER M5 ;
        RECT  9.84 0 9.864 0.084 ;
    END
  END i_code[65]
  PIN i_code[66]
    DIRECTION INPUT ;
    USE SIGNAL ;
    PORT
      LAYER M5 ;
        RECT  9.984 0 10.008 0.084 ;
    END
  END i_code[66]
  PIN i_code[67]
    DIRECTION INPUT ;
    USE SIGNAL ;
    PORT
      LAYER M5 ;
        RECT  10.128 0 10.152 0.084 ;
    END
  END i_code[67]
  PIN i_code[68]
    DIRECTION INPUT ;
    USE SIGNAL ;
    PORT
      LAYER M5 ;
        RECT  10.224 0 10.248 0.084 ;
    END
  END i_code[68]
  PIN i_code[69]
    DIRECTION INPUT ;
    USE SIGNAL ;
    PORT
      LAYER M5 ;
        RECT  10.368 0 10.392 0.084 ;
    END
  END i_code[69]
  PIN i_code[6]
    DIRECTION INPUT ;
    USE SIGNAL ;
    PORT
      LAYER M5 ;
        RECT  1.872 0 1.896 0.084 ;
    END
  END i_code[6]
  PIN i_code[70]
    DIRECTION INPUT ;
    USE SIGNAL ;
    PORT
      LAYER M5 ;
        RECT  10.512 0 10.536 0.084 ;
    END
  END i_code[70]
  PIN i_code[71]
    DIRECTION INPUT ;
    USE SIGNAL ;
    PORT
      LAYER M5 ;
        RECT  10.656 0 10.68 0.084 ;
    END
  END i_code[71]
  PIN i_code[72]
    DIRECTION INPUT ;
    USE SIGNAL ;
    PORT
      LAYER M5 ;
        RECT  10.8 0 10.824 0.084 ;
    END
  END i_code[72]
  PIN i_code[73]
    DIRECTION INPUT ;
    USE SIGNAL ;
    PORT
      LAYER M5 ;
        RECT  10.896 0 10.92 0.084 ;
    END
  END i_code[73]
  PIN i_code[74]
    DIRECTION INPUT ;
    USE SIGNAL ;
    PORT
      LAYER M5 ;
        RECT  11.04 0 11.064 0.084 ;
    END
  END i_code[74]
  PIN i_code[75]
    DIRECTION INPUT ;
    USE SIGNAL ;
    PORT
      LAYER M5 ;
        RECT  11.184 0 11.208 0.084 ;
    END
  END i_code[75]
  PIN i_code[76]
    DIRECTION INPUT ;
    USE SIGNAL ;
    PORT
      LAYER M5 ;
        RECT  11.328 0 11.352 0.084 ;
    END
  END i_code[76]
  PIN i_code[77]
    DIRECTION INPUT ;
    USE SIGNAL ;
    PORT
      LAYER M5 ;
        RECT  11.472 0 11.496 0.084 ;
    END
  END i_code[77]
  PIN i_code[78]
    DIRECTION INPUT ;
    USE SIGNAL ;
    PORT
      LAYER M5 ;
        RECT  11.616 0 11.64 0.084 ;
    END
  END i_code[78]
  PIN i_code[79]
    DIRECTION INPUT ;
    USE SIGNAL ;
    PORT
      LAYER M5 ;
        RECT  11.712 0 11.736 0.084 ;
    END
  END i_code[79]
  PIN i_code[7]
    DIRECTION INPUT ;
    USE SIGNAL ;
    PORT
      LAYER M5 ;
        RECT  2.016 0 2.04 0.084 ;
    END
  END i_code[7]
  PIN i_code[80]
    DIRECTION INPUT ;
    USE SIGNAL ;
    PORT
      LAYER M5 ;
        RECT  11.856 0 11.88 0.084 ;
    END
  END i_code[80]
  PIN i_code[81]
    DIRECTION INPUT ;
    USE SIGNAL ;
    PORT
      LAYER M5 ;
        RECT  12 0 12.024 0.084 ;
    END
  END i_code[81]
  PIN i_code[82]
    DIRECTION INPUT ;
    USE SIGNAL ;
    PORT
      LAYER M5 ;
        RECT  12.144 0 12.168 0.084 ;
    END
  END i_code[82]
  PIN i_code[83]
    DIRECTION INPUT ;
    USE SIGNAL ;
    PORT
      LAYER M5 ;
        RECT  12.288 0 12.312 0.084 ;
    END
  END i_code[83]
  PIN i_code[84]
    DIRECTION INPUT ;
    USE SIGNAL ;
    PORT
      LAYER M5 ;
        RECT  12.384 0 12.408 0.084 ;
    END
  END i_code[84]
  PIN i_code[85]
    DIRECTION INPUT ;
    USE SIGNAL ;
    PORT
      LAYER M5 ;
        RECT  12.528 0 12.552 0.084 ;
    END
  END i_code[85]
  PIN i_code[86]
    DIRECTION INPUT ;
    USE SIGNAL ;
    PORT
      LAYER M5 ;
        RECT  12.672 0 12.696 0.084 ;
    END
  END i_code[86]
  PIN i_code[87]
    DIRECTION INPUT ;
    USE SIGNAL ;
    PORT
      LAYER M5 ;
        RECT  12.816 0 12.84 0.084 ;
    END
  END i_code[87]
  PIN i_code[88]
    DIRECTION INPUT ;
    USE SIGNAL ;
    PORT
      LAYER M5 ;
        RECT  12.96 0 12.984 0.084 ;
    END
  END i_code[88]
  PIN i_code[89]
    DIRECTION INPUT ;
    USE SIGNAL ;
    PORT
      LAYER M5 ;
        RECT  13.056 0 13.08 0.084 ;
    END
  END i_code[89]
  PIN i_code[8]
    DIRECTION INPUT ;
    USE SIGNAL ;
    PORT
      LAYER M5 ;
        RECT  2.16 0 2.184 0.084 ;
    END
  END i_code[8]
  PIN i_code[90]
    DIRECTION INPUT ;
    USE SIGNAL ;
    PORT
      LAYER M5 ;
        RECT  13.2 0 13.224 0.084 ;
    END
  END i_code[90]
  PIN i_code[91]
    DIRECTION INPUT ;
    USE SIGNAL ;
    PORT
      LAYER M5 ;
        RECT  13.344 0 13.368 0.084 ;
    END
  END i_code[91]
  PIN i_code[92]
    DIRECTION INPUT ;
    USE SIGNAL ;
    PORT
      LAYER M5 ;
        RECT  13.488 0 13.512 0.084 ;
    END
  END i_code[92]
  PIN i_code[93]
    DIRECTION INPUT ;
    USE SIGNAL ;
    PORT
      LAYER M5 ;
        RECT  13.632 0 13.656 0.084 ;
    END
  END i_code[93]
  PIN i_code[94]
    DIRECTION INPUT ;
    USE SIGNAL ;
    PORT
      LAYER M5 ;
        RECT  13.776 0 13.8 0.084 ;
    END
  END i_code[94]
  PIN i_code[95]
    DIRECTION INPUT ;
    USE SIGNAL ;
    PORT
      LAYER M5 ;
        RECT  13.872 0 13.896 0.084 ;
    END
  END i_code[95]
  PIN i_code[96]
    DIRECTION INPUT ;
    USE SIGNAL ;
    PORT
      LAYER M5 ;
        RECT  14.016 0 14.04 0.084 ;
    END
  END i_code[96]
  PIN i_code[97]
    DIRECTION INPUT ;
    USE SIGNAL ;
    PORT
      LAYER M5 ;
        RECT  14.16 0 14.184 0.084 ;
    END
  END i_code[97]
  PIN i_code[98]
    DIRECTION INPUT ;
    USE SIGNAL ;
    PORT
      LAYER M5 ;
        RECT  14.304 0 14.328 0.084 ;
    END
  END i_code[98]
  PIN i_code[99]
    DIRECTION INPUT ;
    USE SIGNAL ;
    PORT
      LAYER M5 ;
        RECT  14.448 0 14.472 0.084 ;
    END
  END i_code[99]
  PIN i_code[9]
    DIRECTION INPUT ;
    USE SIGNAL ;
    PORT
      LAYER M5 ;
        RECT  2.256 0 2.28 0.084 ;
    END
  END i_code[9]
  PIN i_row[0]
    DIRECTION INPUT ;
    USE SIGNAL ;
    PORT
      LAYER M4 ;
        RECT  0 1.2 0.084 1.224 ;
    END
  END i_row[0]
  PIN i_row[1]
    DIRECTION INPUT ;
    USE SIGNAL ;
    PORT
      LAYER M4 ;
        RECT  0 1.344 0.084 1.368 ;
    END
  END i_row[1]
  PIN i_row[2]
    DIRECTION INPUT ;
    USE SIGNAL ;
    PORT
      LAYER M4 ;
        RECT  0 1.44 0.084 1.464 ;
    END
  END i_row[2]
  PIN i_row[3]
    DIRECTION INPUT ;
    USE SIGNAL ;
    PORT
      LAYER M4 ;
        RECT  0 1.584 0.084 1.608 ;
    END
  END i_row[3]
  PIN i_row[4]
    DIRECTION INPUT ;
    USE SIGNAL ;
    PORT
      LAYER M4 ;
        RECT  0 1.728 0.084 1.752 ;
    END
  END i_row[4]
  PIN i_row[5]
    DIRECTION INPUT ;
    USE SIGNAL ;
    PORT
      LAYER M4 ;
        RECT  0 1.872 0.084 1.896 ;
    END
  END i_row[5]
  PIN i_row[6]
    DIRECTION INPUT ;
    USE SIGNAL ;
    PORT
      LAYER M4 ;
        RECT  0 1.968 0.084 1.992 ;
    END
  END i_row[6]
  PIN i_row[7]
    DIRECTION INPUT ;
    USE SIGNAL ;
    PORT
      LAYER M4 ;
        RECT  0 2.112 0.084 2.136 ;
    END
  END i_row[7]
  PIN i_sec[0]
    DIRECTION INPUT ;
    USE SIGNAL ;
    PORT
      LAYER M4 ;
        RECT  0 2.256 0.084 2.28 ;
    END
  END i_sec[0]
  PIN i_sec[10]
    DIRECTION INPUT ;
    USE SIGNAL ;
    PORT
      LAYER M4 ;
        RECT  0 3.6 0.084 3.624 ;
    END
  END i_sec[10]
  PIN i_sec[11]
    DIRECTION INPUT ;
    USE SIGNAL ;
    PORT
      LAYER M4 ;
        RECT  0 3.744 0.084 3.768 ;
    END
  END i_sec[11]
  PIN i_sec[12]
    DIRECTION INPUT ;
    USE SIGNAL ;
    PORT
      LAYER M4 ;
        RECT  0 3.888 0.084 3.912 ;
    END
  END i_sec[12]
  PIN i_sec[13]
    DIRECTION INPUT ;
    USE SIGNAL ;
    PORT
      LAYER M4 ;
        RECT  0 3.984 0.084 4.008 ;
    END
  END i_sec[13]
  PIN i_sec[14]
    DIRECTION INPUT ;
    USE SIGNAL ;
    PORT
      LAYER M4 ;
        RECT  0 4.128 0.084 4.152 ;
    END
  END i_sec[14]
  PIN i_sec[15]
    DIRECTION INPUT ;
    USE SIGNAL ;
    PORT
      LAYER M4 ;
        RECT  0 4.272 0.084 4.296 ;
    END
  END i_sec[15]
  PIN i_sec[16]
    DIRECTION INPUT ;
    USE SIGNAL ;
    PORT
      LAYER M4 ;
        RECT  0 4.416 0.084 4.44 ;
    END
  END i_sec[16]
  PIN i_sec[1]
    DIRECTION INPUT ;
    USE SIGNAL ;
    PORT
      LAYER M4 ;
        RECT  0 2.4 0.084 2.424 ;
    END
  END i_sec[1]
  PIN i_sec[2]
    DIRECTION INPUT ;
    USE SIGNAL ;
    PORT
      LAYER M4 ;
        RECT  0 2.544 0.084 2.568 ;
    END
  END i_sec[2]
  PIN i_sec[3]
    DIRECTION INPUT ;
    USE SIGNAL ;
    PORT
      LAYER M4 ;
        RECT  0 2.64 0.084 2.664 ;
    END
  END i_sec[3]
  PIN i_sec[4]
    DIRECTION INPUT ;
    USE SIGNAL ;
    PORT
      LAYER M4 ;
        RECT  0 2.784 0.084 2.808 ;
    END
  END i_sec[4]
  PIN i_sec[5]
    DIRECTION INPUT ;
    USE SIGNAL ;
    PORT
      LAYER M4 ;
        RECT  0 2.928 0.084 2.952 ;
    END
  END i_sec[5]
  PIN i_sec[6]
    DIRECTION INPUT ;
    USE SIGNAL ;
    PORT
      LAYER M4 ;
        RECT  0 3.072 0.084 3.096 ;
    END
  END i_sec[6]
  PIN i_sec[7]
    DIRECTION INPUT ;
    USE SIGNAL ;
    PORT
      LAYER M4 ;
        RECT  0 3.216 0.084 3.24 ;
    END
  END i_sec[7]
  PIN i_sec[8]
    DIRECTION INPUT ;
    USE SIGNAL ;
    PORT
      LAYER M4 ;
        RECT  0 3.312 0.084 3.336 ;
    END
  END i_sec[8]
  PIN i_sec[9]
    DIRECTION INPUT ;
    USE SIGNAL ;
    PORT
      LAYER M4 ;
        RECT  0 3.456 0.084 3.48 ;
    END
  END i_sec[9]
  PIN i_v
    DIRECTION INPUT ;
    USE SIGNAL ;
    PORT
      LAYER M5 ;
        RECT  39.984 0 40.008 0.084 ;
    END
  END i_v
  PIN o_data[0]
    DIRECTION OUTPUT ;
    USE SIGNAL ;
    PORT
      LAYER M4 ;
        RECT  0 4.512 0.084 4.536 ;
    END
  END o_data[0]
  PIN o_data[100]
    DIRECTION OUTPUT ;
    USE SIGNAL ;
    PORT
      LAYER M4 ;
        RECT  0 17.904 0.084 17.928 ;
    END
  END o_data[100]
  PIN o_data[101]
    DIRECTION OUTPUT ;
    USE SIGNAL ;
    PORT
      LAYER M4 ;
        RECT  0 18.048 0.084 18.072 ;
    END
  END o_data[101]
  PIN o_data[102]
    DIRECTION OUTPUT ;
    USE SIGNAL ;
    PORT
      LAYER M4 ;
        RECT  0 18.192 0.084 18.216 ;
    END
  END o_data[102]
  PIN o_data[103]
    DIRECTION OUTPUT ;
    USE SIGNAL ;
    PORT
      LAYER M4 ;
        RECT  0 18.288 0.084 18.312 ;
    END
  END o_data[103]
  PIN o_data[104]
    DIRECTION OUTPUT ;
    USE SIGNAL ;
    PORT
      LAYER M4 ;
        RECT  0 18.432 0.084 18.456 ;
    END
  END o_data[104]
  PIN o_data[105]
    DIRECTION OUTPUT ;
    USE SIGNAL ;
    PORT
      LAYER M4 ;
        RECT  0 18.576 0.084 18.6 ;
    END
  END o_data[105]
  PIN o_data[106]
    DIRECTION OUTPUT ;
    USE SIGNAL ;
    PORT
      LAYER M4 ;
        RECT  0 18.72 0.084 18.744 ;
    END
  END o_data[106]
  PIN o_data[107]
    DIRECTION OUTPUT ;
    USE SIGNAL ;
    PORT
      LAYER M4 ;
        RECT  0 18.864 0.084 18.888 ;
    END
  END o_data[107]
  PIN o_data[108]
    DIRECTION OUTPUT ;
    USE SIGNAL ;
    PORT
      LAYER M4 ;
        RECT  0 18.96 0.084 18.984 ;
    END
  END o_data[108]
  PIN o_data[109]
    DIRECTION OUTPUT ;
    USE SIGNAL ;
    PORT
      LAYER M4 ;
        RECT  0 19.104 0.084 19.128 ;
    END
  END o_data[109]
  PIN o_data[10]
    DIRECTION OUTPUT ;
    USE SIGNAL ;
    PORT
      LAYER M4 ;
        RECT  0 5.856 0.084 5.88 ;
    END
  END o_data[10]
  PIN o_data[110]
    DIRECTION OUTPUT ;
    USE SIGNAL ;
    PORT
      LAYER M4 ;
        RECT  0 19.248 0.084 19.272 ;
    END
  END o_data[110]
  PIN o_data[111]
    DIRECTION OUTPUT ;
    USE SIGNAL ;
    PORT
      LAYER M4 ;
        RECT  0 19.392 0.084 19.416 ;
    END
  END o_data[111]
  PIN o_data[112]
    DIRECTION OUTPUT ;
    USE SIGNAL ;
    PORT
      LAYER M4 ;
        RECT  0 19.536 0.084 19.56 ;
    END
  END o_data[112]
  PIN o_data[113]
    DIRECTION OUTPUT ;
    USE SIGNAL ;
    PORT
      LAYER M4 ;
        RECT  0 19.632 0.084 19.656 ;
    END
  END o_data[113]
  PIN o_data[114]
    DIRECTION OUTPUT ;
    USE SIGNAL ;
    PORT
      LAYER M4 ;
        RECT  0 19.776 0.084 19.8 ;
    END
  END o_data[114]
  PIN o_data[115]
    DIRECTION OUTPUT ;
    USE SIGNAL ;
    PORT
      LAYER M4 ;
        RECT  0 19.92 0.084 19.944 ;
    END
  END o_data[115]
  PIN o_data[116]
    DIRECTION OUTPUT ;
    USE SIGNAL ;
    PORT
      LAYER M4 ;
        RECT  0 20.064 0.084 20.088 ;
    END
  END o_data[116]
  PIN o_data[117]
    DIRECTION OUTPUT ;
    USE SIGNAL ;
    PORT
      LAYER M4 ;
        RECT  0 20.16 0.084 20.184 ;
    END
  END o_data[117]
  PIN o_data[118]
    DIRECTION OUTPUT ;
    USE SIGNAL ;
    PORT
      LAYER M4 ;
        RECT  0 20.304 0.084 20.328 ;
    END
  END o_data[118]
  PIN o_data[119]
    DIRECTION OUTPUT ;
    USE SIGNAL ;
    PORT
      LAYER M4 ;
        RECT  0 20.448 0.084 20.472 ;
    END
  END o_data[119]
  PIN o_data[11]
    DIRECTION OUTPUT ;
    USE SIGNAL ;
    PORT
      LAYER M4 ;
        RECT  0 6 0.084 6.024 ;
    END
  END o_data[11]
  PIN o_data[120]
    DIRECTION OUTPUT ;
    USE SIGNAL ;
    PORT
      LAYER M4 ;
        RECT  0 20.592 0.084 20.616 ;
    END
  END o_data[120]
  PIN o_data[121]
    DIRECTION OUTPUT ;
    USE SIGNAL ;
    PORT
      LAYER M4 ;
        RECT  0 20.736 0.084 20.76 ;
    END
  END o_data[121]
  PIN o_data[122]
    DIRECTION OUTPUT ;
    USE SIGNAL ;
    PORT
      LAYER M4 ;
        RECT  0 20.832 0.084 20.856 ;
    END
  END o_data[122]
  PIN o_data[123]
    DIRECTION OUTPUT ;
    USE SIGNAL ;
    PORT
      LAYER M4 ;
        RECT  0 20.976 0.084 21 ;
    END
  END o_data[123]
  PIN o_data[124]
    DIRECTION OUTPUT ;
    USE SIGNAL ;
    PORT
      LAYER M4 ;
        RECT  0 21.12 0.084 21.144 ;
    END
  END o_data[124]
  PIN o_data[125]
    DIRECTION OUTPUT ;
    USE SIGNAL ;
    PORT
      LAYER M4 ;
        RECT  0 21.264 0.084 21.288 ;
    END
  END o_data[125]
  PIN o_data[126]
    DIRECTION OUTPUT ;
    USE SIGNAL ;
    PORT
      LAYER M4 ;
        RECT  0 21.408 0.084 21.432 ;
    END
  END o_data[126]
  PIN o_data[127]
    DIRECTION OUTPUT ;
    USE SIGNAL ;
    PORT
      LAYER M4 ;
        RECT  0 21.504 0.084 21.528 ;
    END
  END o_data[127]
  PIN o_data[128]
    DIRECTION OUTPUT ;
    USE SIGNAL ;
    PORT
      LAYER M4 ;
        RECT  0 21.648 0.084 21.672 ;
    END
  END o_data[128]
  PIN o_data[129]
    DIRECTION OUTPUT ;
    USE SIGNAL ;
    PORT
      LAYER M4 ;
        RECT  0 21.792 0.084 21.816 ;
    END
  END o_data[129]
  PIN o_data[12]
    DIRECTION OUTPUT ;
    USE SIGNAL ;
    PORT
      LAYER M4 ;
        RECT  0 6.144 0.084 6.168 ;
    END
  END o_data[12]
  PIN o_data[130]
    DIRECTION OUTPUT ;
    USE SIGNAL ;
    PORT
      LAYER M4 ;
        RECT  0 21.936 0.084 21.96 ;
    END
  END o_data[130]
  PIN o_data[131]
    DIRECTION OUTPUT ;
    USE SIGNAL ;
    PORT
      LAYER M4 ;
        RECT  0 22.08 0.084 22.104 ;
    END
  END o_data[131]
  PIN o_data[132]
    DIRECTION OUTPUT ;
    USE SIGNAL ;
    PORT
      LAYER M4 ;
        RECT  0 22.176 0.084 22.2 ;
    END
  END o_data[132]
  PIN o_data[133]
    DIRECTION OUTPUT ;
    USE SIGNAL ;
    PORT
      LAYER M4 ;
        RECT  0 22.32 0.084 22.344 ;
    END
  END o_data[133]
  PIN o_data[134]
    DIRECTION OUTPUT ;
    USE SIGNAL ;
    PORT
      LAYER M4 ;
        RECT  0 22.464 0.084 22.488 ;
    END
  END o_data[134]
  PIN o_data[135]
    DIRECTION OUTPUT ;
    USE SIGNAL ;
    PORT
      LAYER M4 ;
        RECT  0 22.608 0.084 22.632 ;
    END
  END o_data[135]
  PIN o_data[136]
    DIRECTION OUTPUT ;
    USE SIGNAL ;
    PORT
      LAYER M4 ;
        RECT  0 22.704 0.084 22.728 ;
    END
  END o_data[136]
  PIN o_data[137]
    DIRECTION OUTPUT ;
    USE SIGNAL ;
    PORT
      LAYER M4 ;
        RECT  0 22.848 0.084 22.872 ;
    END
  END o_data[137]
  PIN o_data[138]
    DIRECTION OUTPUT ;
    USE SIGNAL ;
    PORT
      LAYER M4 ;
        RECT  0 22.992 0.084 23.016 ;
    END
  END o_data[138]
  PIN o_data[139]
    DIRECTION OUTPUT ;
    USE SIGNAL ;
    PORT
      LAYER M4 ;
        RECT  0 23.136 0.084 23.16 ;
    END
  END o_data[139]
  PIN o_data[13]
    DIRECTION OUTPUT ;
    USE SIGNAL ;
    PORT
      LAYER M4 ;
        RECT  0 6.288 0.084 6.312 ;
    END
  END o_data[13]
  PIN o_data[140]
    DIRECTION OUTPUT ;
    USE SIGNAL ;
    PORT
      LAYER M4 ;
        RECT  0 23.28 0.084 23.304 ;
    END
  END o_data[140]
  PIN o_data[141]
    DIRECTION OUTPUT ;
    USE SIGNAL ;
    PORT
      LAYER M4 ;
        RECT  0 23.376 0.084 23.4 ;
    END
  END o_data[141]
  PIN o_data[142]
    DIRECTION OUTPUT ;
    USE SIGNAL ;
    PORT
      LAYER M4 ;
        RECT  0 23.52 0.084 23.544 ;
    END
  END o_data[142]
  PIN o_data[143]
    DIRECTION OUTPUT ;
    USE SIGNAL ;
    PORT
      LAYER M4 ;
        RECT  0 23.664 0.084 23.688 ;
    END
  END o_data[143]
  PIN o_data[144]
    DIRECTION OUTPUT ;
    USE SIGNAL ;
    PORT
      LAYER M4 ;
        RECT  0 23.808 0.084 23.832 ;
    END
  END o_data[144]
  PIN o_data[145]
    DIRECTION OUTPUT ;
    USE SIGNAL ;
    PORT
      LAYER M4 ;
        RECT  0 23.952 0.084 23.976 ;
    END
  END o_data[145]
  PIN o_data[146]
    DIRECTION OUTPUT ;
    USE SIGNAL ;
    PORT
      LAYER M4 ;
        RECT  0 24.048 0.084 24.072 ;
    END
  END o_data[146]
  PIN o_data[147]
    DIRECTION OUTPUT ;
    USE SIGNAL ;
    PORT
      LAYER M4 ;
        RECT  0 24.192 0.084 24.216 ;
    END
  END o_data[147]
  PIN o_data[148]
    DIRECTION OUTPUT ;
    USE SIGNAL ;
    PORT
      LAYER M4 ;
        RECT  0 24.336 0.084 24.36 ;
    END
  END o_data[148]
  PIN o_data[149]
    DIRECTION OUTPUT ;
    USE SIGNAL ;
    PORT
      LAYER M4 ;
        RECT  0 24.48 0.084 24.504 ;
    END
  END o_data[149]
  PIN o_data[14]
    DIRECTION OUTPUT ;
    USE SIGNAL ;
    PORT
      LAYER M4 ;
        RECT  0 6.384 0.084 6.408 ;
    END
  END o_data[14]
  PIN o_data[150]
    DIRECTION OUTPUT ;
    USE SIGNAL ;
    PORT
      LAYER M4 ;
        RECT  0 24.576 0.084 24.6 ;
    END
  END o_data[150]
  PIN o_data[151]
    DIRECTION OUTPUT ;
    USE SIGNAL ;
    PORT
      LAYER M4 ;
        RECT  0 24.72 0.084 24.744 ;
    END
  END o_data[151]
  PIN o_data[152]
    DIRECTION OUTPUT ;
    USE SIGNAL ;
    PORT
      LAYER M4 ;
        RECT  0 24.864 0.084 24.888 ;
    END
  END o_data[152]
  PIN o_data[153]
    DIRECTION OUTPUT ;
    USE SIGNAL ;
    PORT
      LAYER M4 ;
        RECT  0 25.008 0.084 25.032 ;
    END
  END o_data[153]
  PIN o_data[154]
    DIRECTION OUTPUT ;
    USE SIGNAL ;
    PORT
      LAYER M4 ;
        RECT  0 25.152 0.084 25.176 ;
    END
  END o_data[154]
  PIN o_data[155]
    DIRECTION OUTPUT ;
    USE SIGNAL ;
    PORT
      LAYER M4 ;
        RECT  0 25.248 0.084 25.272 ;
    END
  END o_data[155]
  PIN o_data[156]
    DIRECTION OUTPUT ;
    USE SIGNAL ;
    PORT
      LAYER M4 ;
        RECT  0 25.392 0.084 25.416 ;
    END
  END o_data[156]
  PIN o_data[157]
    DIRECTION OUTPUT ;
    USE SIGNAL ;
    PORT
      LAYER M4 ;
        RECT  0 25.536 0.084 25.56 ;
    END
  END o_data[157]
  PIN o_data[158]
    DIRECTION OUTPUT ;
    USE SIGNAL ;
    PORT
      LAYER M4 ;
        RECT  0 25.68 0.084 25.704 ;
    END
  END o_data[158]
  PIN o_data[159]
    DIRECTION OUTPUT ;
    USE SIGNAL ;
    PORT
      LAYER M4 ;
        RECT  0 25.824 0.084 25.848 ;
    END
  END o_data[159]
  PIN o_data[15]
    DIRECTION OUTPUT ;
    USE SIGNAL ;
    PORT
      LAYER M4 ;
        RECT  0 6.528 0.084 6.552 ;
    END
  END o_data[15]
  PIN o_data[160]
    DIRECTION OUTPUT ;
    USE SIGNAL ;
    PORT
      LAYER M4 ;
        RECT  0 25.92 0.084 25.944 ;
    END
  END o_data[160]
  PIN o_data[161]
    DIRECTION OUTPUT ;
    USE SIGNAL ;
    PORT
      LAYER M4 ;
        RECT  0 26.064 0.084 26.088 ;
    END
  END o_data[161]
  PIN o_data[162]
    DIRECTION OUTPUT ;
    USE SIGNAL ;
    PORT
      LAYER M4 ;
        RECT  0 26.208 0.084 26.232 ;
    END
  END o_data[162]
  PIN o_data[163]
    DIRECTION OUTPUT ;
    USE SIGNAL ;
    PORT
      LAYER M4 ;
        RECT  0 26.352 0.084 26.376 ;
    END
  END o_data[163]
  PIN o_data[164]
    DIRECTION OUTPUT ;
    USE SIGNAL ;
    PORT
      LAYER M4 ;
        RECT  0 26.448 0.084 26.472 ;
    END
  END o_data[164]
  PIN o_data[165]
    DIRECTION OUTPUT ;
    USE SIGNAL ;
    PORT
      LAYER M4 ;
        RECT  0 26.592 0.084 26.616 ;
    END
  END o_data[165]
  PIN o_data[166]
    DIRECTION OUTPUT ;
    USE SIGNAL ;
    PORT
      LAYER M4 ;
        RECT  0 26.736 0.084 26.76 ;
    END
  END o_data[166]
  PIN o_data[167]
    DIRECTION OUTPUT ;
    USE SIGNAL ;
    PORT
      LAYER M4 ;
        RECT  0 26.88 0.084 26.904 ;
    END
  END o_data[167]
  PIN o_data[168]
    DIRECTION OUTPUT ;
    USE SIGNAL ;
    PORT
      LAYER M4 ;
        RECT  0 27.024 0.084 27.048 ;
    END
  END o_data[168]
  PIN o_data[169]
    DIRECTION OUTPUT ;
    USE SIGNAL ;
    PORT
      LAYER M4 ;
        RECT  0 27.12 0.084 27.144 ;
    END
  END o_data[169]
  PIN o_data[16]
    DIRECTION OUTPUT ;
    USE SIGNAL ;
    PORT
      LAYER M4 ;
        RECT  0 6.672 0.084 6.696 ;
    END
  END o_data[16]
  PIN o_data[170]
    DIRECTION OUTPUT ;
    USE SIGNAL ;
    PORT
      LAYER M4 ;
        RECT  0 27.264 0.084 27.288 ;
    END
  END o_data[170]
  PIN o_data[171]
    DIRECTION OUTPUT ;
    USE SIGNAL ;
    PORT
      LAYER M4 ;
        RECT  0 27.408 0.084 27.432 ;
    END
  END o_data[171]
  PIN o_data[172]
    DIRECTION OUTPUT ;
    USE SIGNAL ;
    PORT
      LAYER M4 ;
        RECT  0 27.552 0.084 27.576 ;
    END
  END o_data[172]
  PIN o_data[173]
    DIRECTION OUTPUT ;
    USE SIGNAL ;
    PORT
      LAYER M4 ;
        RECT  0 27.696 0.084 27.72 ;
    END
  END o_data[173]
  PIN o_data[174]
    DIRECTION OUTPUT ;
    USE SIGNAL ;
    PORT
      LAYER M4 ;
        RECT  0 27.792 0.084 27.816 ;
    END
  END o_data[174]
  PIN o_data[175]
    DIRECTION OUTPUT ;
    USE SIGNAL ;
    PORT
      LAYER M4 ;
        RECT  0 27.936 0.084 27.96 ;
    END
  END o_data[175]
  PIN o_data[176]
    DIRECTION OUTPUT ;
    USE SIGNAL ;
    PORT
      LAYER M4 ;
        RECT  0 28.08 0.084 28.104 ;
    END
  END o_data[176]
  PIN o_data[177]
    DIRECTION OUTPUT ;
    USE SIGNAL ;
    PORT
      LAYER M4 ;
        RECT  0 28.224 0.084 28.248 ;
    END
  END o_data[177]
  PIN o_data[178]
    DIRECTION OUTPUT ;
    USE SIGNAL ;
    PORT
      LAYER M4 ;
        RECT  0 28.32 0.084 28.344 ;
    END
  END o_data[178]
  PIN o_data[179]
    DIRECTION OUTPUT ;
    USE SIGNAL ;
    PORT
      LAYER M4 ;
        RECT  0 28.464 0.084 28.488 ;
    END
  END o_data[179]
  PIN o_data[17]
    DIRECTION OUTPUT ;
    USE SIGNAL ;
    PORT
      LAYER M4 ;
        RECT  0 6.816 0.084 6.84 ;
    END
  END o_data[17]
  PIN o_data[180]
    DIRECTION OUTPUT ;
    USE SIGNAL ;
    PORT
      LAYER M4 ;
        RECT  0 28.608 0.084 28.632 ;
    END
  END o_data[180]
  PIN o_data[181]
    DIRECTION OUTPUT ;
    USE SIGNAL ;
    PORT
      LAYER M4 ;
        RECT  0 28.752 0.084 28.776 ;
    END
  END o_data[181]
  PIN o_data[182]
    DIRECTION OUTPUT ;
    USE SIGNAL ;
    PORT
      LAYER M4 ;
        RECT  0 28.896 0.084 28.92 ;
    END
  END o_data[182]
  PIN o_data[183]
    DIRECTION OUTPUT ;
    USE SIGNAL ;
    PORT
      LAYER M4 ;
        RECT  0 28.992 0.084 29.016 ;
    END
  END o_data[183]
  PIN o_data[184]
    DIRECTION OUTPUT ;
    USE SIGNAL ;
    PORT
      LAYER M4 ;
        RECT  0 29.136 0.084 29.16 ;
    END
  END o_data[184]
  PIN o_data[185]
    DIRECTION OUTPUT ;
    USE SIGNAL ;
    PORT
      LAYER M4 ;
        RECT  0 29.28 0.084 29.304 ;
    END
  END o_data[185]
  PIN o_data[186]
    DIRECTION OUTPUT ;
    USE SIGNAL ;
    PORT
      LAYER M4 ;
        RECT  0 29.424 0.084 29.448 ;
    END
  END o_data[186]
  PIN o_data[187]
    DIRECTION OUTPUT ;
    USE SIGNAL ;
    PORT
      LAYER M4 ;
        RECT  0 29.568 0.084 29.592 ;
    END
  END o_data[187]
  PIN o_data[188]
    DIRECTION OUTPUT ;
    USE SIGNAL ;
    PORT
      LAYER M4 ;
        RECT  0 29.664 0.084 29.688 ;
    END
  END o_data[188]
  PIN o_data[189]
    DIRECTION OUTPUT ;
    USE SIGNAL ;
    PORT
      LAYER M4 ;
        RECT  0 29.808 0.084 29.832 ;
    END
  END o_data[189]
  PIN o_data[18]
    DIRECTION OUTPUT ;
    USE SIGNAL ;
    PORT
      LAYER M4 ;
        RECT  0 6.96 0.084 6.984 ;
    END
  END o_data[18]
  PIN o_data[190]
    DIRECTION OUTPUT ;
    USE SIGNAL ;
    PORT
      LAYER M4 ;
        RECT  0 29.952 0.084 29.976 ;
    END
  END o_data[190]
  PIN o_data[191]
    DIRECTION OUTPUT ;
    USE SIGNAL ;
    PORT
      LAYER M4 ;
        RECT  0 30.096 0.084 30.12 ;
    END
  END o_data[191]
  PIN o_data[192]
    DIRECTION OUTPUT ;
    USE SIGNAL ;
    PORT
      LAYER M4 ;
        RECT  0 30.24 0.084 30.264 ;
    END
  END o_data[192]
  PIN o_data[193]
    DIRECTION OUTPUT ;
    USE SIGNAL ;
    PORT
      LAYER M4 ;
        RECT  0 30.336 0.084 30.36 ;
    END
  END o_data[193]
  PIN o_data[194]
    DIRECTION OUTPUT ;
    USE SIGNAL ;
    PORT
      LAYER M4 ;
        RECT  0 30.48 0.084 30.504 ;
    END
  END o_data[194]
  PIN o_data[195]
    DIRECTION OUTPUT ;
    USE SIGNAL ;
    PORT
      LAYER M4 ;
        RECT  0 30.624 0.084 30.648 ;
    END
  END o_data[195]
  PIN o_data[196]
    DIRECTION OUTPUT ;
    USE SIGNAL ;
    PORT
      LAYER M4 ;
        RECT  0 30.768 0.084 30.792 ;
    END
  END o_data[196]
  PIN o_data[197]
    DIRECTION OUTPUT ;
    USE SIGNAL ;
    PORT
      LAYER M4 ;
        RECT  0 30.864 0.084 30.888 ;
    END
  END o_data[197]
  PIN o_data[198]
    DIRECTION OUTPUT ;
    USE SIGNAL ;
    PORT
      LAYER M4 ;
        RECT  0 31.008 0.084 31.032 ;
    END
  END o_data[198]
  PIN o_data[199]
    DIRECTION OUTPUT ;
    USE SIGNAL ;
    PORT
      LAYER M4 ;
        RECT  0 31.152 0.084 31.176 ;
    END
  END o_data[199]
  PIN o_data[19]
    DIRECTION OUTPUT ;
    USE SIGNAL ;
    PORT
      LAYER M4 ;
        RECT  0 7.056 0.084 7.08 ;
    END
  END o_data[19]
  PIN o_data[1]
    DIRECTION OUTPUT ;
    USE SIGNAL ;
    PORT
      LAYER M4 ;
        RECT  0 4.656 0.084 4.68 ;
    END
  END o_data[1]
  PIN o_data[200]
    DIRECTION OUTPUT ;
    USE SIGNAL ;
    PORT
      LAYER M4 ;
        RECT  0 31.296 0.084 31.32 ;
    END
  END o_data[200]
  PIN o_data[201]
    DIRECTION OUTPUT ;
    USE SIGNAL ;
    PORT
      LAYER M4 ;
        RECT  0 31.44 0.084 31.464 ;
    END
  END o_data[201]
  PIN o_data[202]
    DIRECTION OUTPUT ;
    USE SIGNAL ;
    PORT
      LAYER M4 ;
        RECT  0 31.536 0.084 31.56 ;
    END
  END o_data[202]
  PIN o_data[203]
    DIRECTION OUTPUT ;
    USE SIGNAL ;
    PORT
      LAYER M4 ;
        RECT  0 31.68 0.084 31.704 ;
    END
  END o_data[203]
  PIN o_data[204]
    DIRECTION OUTPUT ;
    USE SIGNAL ;
    PORT
      LAYER M4 ;
        RECT  0 31.824 0.084 31.848 ;
    END
  END o_data[204]
  PIN o_data[205]
    DIRECTION OUTPUT ;
    USE SIGNAL ;
    PORT
      LAYER M4 ;
        RECT  0 31.968 0.084 31.992 ;
    END
  END o_data[205]
  PIN o_data[206]
    DIRECTION OUTPUT ;
    USE SIGNAL ;
    PORT
      LAYER M4 ;
        RECT  0 32.112 0.084 32.136 ;
    END
  END o_data[206]
  PIN o_data[207]
    DIRECTION OUTPUT ;
    USE SIGNAL ;
    PORT
      LAYER M4 ;
        RECT  0 32.208 0.084 32.232 ;
    END
  END o_data[207]
  PIN o_data[208]
    DIRECTION OUTPUT ;
    USE SIGNAL ;
    PORT
      LAYER M4 ;
        RECT  0 32.352 0.084 32.376 ;
    END
  END o_data[208]
  PIN o_data[209]
    DIRECTION OUTPUT ;
    USE SIGNAL ;
    PORT
      LAYER M4 ;
        RECT  0 32.496 0.084 32.52 ;
    END
  END o_data[209]
  PIN o_data[20]
    DIRECTION OUTPUT ;
    USE SIGNAL ;
    PORT
      LAYER M4 ;
        RECT  0 7.2 0.084 7.224 ;
    END
  END o_data[20]
  PIN o_data[210]
    DIRECTION OUTPUT ;
    USE SIGNAL ;
    PORT
      LAYER M4 ;
        RECT  0 32.64 0.084 32.664 ;
    END
  END o_data[210]
  PIN o_data[211]
    DIRECTION OUTPUT ;
    USE SIGNAL ;
    PORT
      LAYER M4 ;
        RECT  0 32.736 0.084 32.76 ;
    END
  END o_data[211]
  PIN o_data[212]
    DIRECTION OUTPUT ;
    USE SIGNAL ;
    PORT
      LAYER M4 ;
        RECT  0 32.88 0.084 32.904 ;
    END
  END o_data[212]
  PIN o_data[213]
    DIRECTION OUTPUT ;
    USE SIGNAL ;
    PORT
      LAYER M4 ;
        RECT  0 33.024 0.084 33.048 ;
    END
  END o_data[213]
  PIN o_data[214]
    DIRECTION OUTPUT ;
    USE SIGNAL ;
    PORT
      LAYER M4 ;
        RECT  0 33.168 0.084 33.192 ;
    END
  END o_data[214]
  PIN o_data[215]
    DIRECTION OUTPUT ;
    USE SIGNAL ;
    PORT
      LAYER M4 ;
        RECT  0 33.312 0.084 33.336 ;
    END
  END o_data[215]
  PIN o_data[216]
    DIRECTION OUTPUT ;
    USE SIGNAL ;
    PORT
      LAYER M4 ;
        RECT  0 33.408 0.084 33.432 ;
    END
  END o_data[216]
  PIN o_data[217]
    DIRECTION OUTPUT ;
    USE SIGNAL ;
    PORT
      LAYER M4 ;
        RECT  0 33.552 0.084 33.576 ;
    END
  END o_data[217]
  PIN o_data[218]
    DIRECTION OUTPUT ;
    USE SIGNAL ;
    PORT
      LAYER M4 ;
        RECT  0 33.696 0.084 33.72 ;
    END
  END o_data[218]
  PIN o_data[219]
    DIRECTION OUTPUT ;
    USE SIGNAL ;
    PORT
      LAYER M4 ;
        RECT  0 33.84 0.084 33.864 ;
    END
  END o_data[219]
  PIN o_data[21]
    DIRECTION OUTPUT ;
    USE SIGNAL ;
    PORT
      LAYER M4 ;
        RECT  0 7.344 0.084 7.368 ;
    END
  END o_data[21]
  PIN o_data[220]
    DIRECTION OUTPUT ;
    USE SIGNAL ;
    PORT
      LAYER M4 ;
        RECT  0 33.984 0.084 34.008 ;
    END
  END o_data[220]
  PIN o_data[221]
    DIRECTION OUTPUT ;
    USE SIGNAL ;
    PORT
      LAYER M4 ;
        RECT  0 34.08 0.084 34.104 ;
    END
  END o_data[221]
  PIN o_data[222]
    DIRECTION OUTPUT ;
    USE SIGNAL ;
    PORT
      LAYER M4 ;
        RECT  0 34.224 0.084 34.248 ;
    END
  END o_data[222]
  PIN o_data[223]
    DIRECTION OUTPUT ;
    USE SIGNAL ;
    PORT
      LAYER M4 ;
        RECT  0 34.368 0.084 34.392 ;
    END
  END o_data[223]
  PIN o_data[224]
    DIRECTION OUTPUT ;
    USE SIGNAL ;
    PORT
      LAYER M4 ;
        RECT  0 34.512 0.084 34.536 ;
    END
  END o_data[224]
  PIN o_data[225]
    DIRECTION OUTPUT ;
    USE SIGNAL ;
    PORT
      LAYER M4 ;
        RECT  0 34.608 0.084 34.632 ;
    END
  END o_data[225]
  PIN o_data[226]
    DIRECTION OUTPUT ;
    USE SIGNAL ;
    PORT
      LAYER M4 ;
        RECT  0 34.752 0.084 34.776 ;
    END
  END o_data[226]
  PIN o_data[227]
    DIRECTION OUTPUT ;
    USE SIGNAL ;
    PORT
      LAYER M4 ;
        RECT  0 34.896 0.084 34.92 ;
    END
  END o_data[227]
  PIN o_data[228]
    DIRECTION OUTPUT ;
    USE SIGNAL ;
    PORT
      LAYER M4 ;
        RECT  0 35.04 0.084 35.064 ;
    END
  END o_data[228]
  PIN o_data[229]
    DIRECTION OUTPUT ;
    USE SIGNAL ;
    PORT
      LAYER M4 ;
        RECT  0 35.184 0.084 35.208 ;
    END
  END o_data[229]
  PIN o_data[22]
    DIRECTION OUTPUT ;
    USE SIGNAL ;
    PORT
      LAYER M4 ;
        RECT  0 7.488 0.084 7.512 ;
    END
  END o_data[22]
  PIN o_data[230]
    DIRECTION OUTPUT ;
    USE SIGNAL ;
    PORT
      LAYER M4 ;
        RECT  0 35.28 0.084 35.304 ;
    END
  END o_data[230]
  PIN o_data[231]
    DIRECTION OUTPUT ;
    USE SIGNAL ;
    PORT
      LAYER M4 ;
        RECT  0 35.424 0.084 35.448 ;
    END
  END o_data[231]
  PIN o_data[232]
    DIRECTION OUTPUT ;
    USE SIGNAL ;
    PORT
      LAYER M4 ;
        RECT  0 35.568 0.084 35.592 ;
    END
  END o_data[232]
  PIN o_data[233]
    DIRECTION OUTPUT ;
    USE SIGNAL ;
    PORT
      LAYER M4 ;
        RECT  0 35.712 0.084 35.736 ;
    END
  END o_data[233]
  PIN o_data[234]
    DIRECTION OUTPUT ;
    USE SIGNAL ;
    PORT
      LAYER M4 ;
        RECT  0 35.856 0.084 35.88 ;
    END
  END o_data[234]
  PIN o_data[235]
    DIRECTION OUTPUT ;
    USE SIGNAL ;
    PORT
      LAYER M4 ;
        RECT  0 35.952 0.084 35.976 ;
    END
  END o_data[235]
  PIN o_data[236]
    DIRECTION OUTPUT ;
    USE SIGNAL ;
    PORT
      LAYER M4 ;
        RECT  0 36.096 0.084 36.12 ;
    END
  END o_data[236]
  PIN o_data[237]
    DIRECTION OUTPUT ;
    USE SIGNAL ;
    PORT
      LAYER M4 ;
        RECT  0 36.24 0.084 36.264 ;
    END
  END o_data[237]
  PIN o_data[238]
    DIRECTION OUTPUT ;
    USE SIGNAL ;
    PORT
      LAYER M4 ;
        RECT  0 36.384 0.084 36.408 ;
    END
  END o_data[238]
  PIN o_data[239]
    DIRECTION OUTPUT ;
    USE SIGNAL ;
    PORT
      LAYER M4 ;
        RECT  0 36.48 0.084 36.504 ;
    END
  END o_data[239]
  PIN o_data[23]
    DIRECTION OUTPUT ;
    USE SIGNAL ;
    PORT
      LAYER M4 ;
        RECT  0 7.632 0.084 7.656 ;
    END
  END o_data[23]
  PIN o_data[240]
    DIRECTION OUTPUT ;
    USE SIGNAL ;
    PORT
      LAYER M4 ;
        RECT  0 36.624 0.084 36.648 ;
    END
  END o_data[240]
  PIN o_data[241]
    DIRECTION OUTPUT ;
    USE SIGNAL ;
    PORT
      LAYER M4 ;
        RECT  0 36.768 0.084 36.792 ;
    END
  END o_data[241]
  PIN o_data[242]
    DIRECTION OUTPUT ;
    USE SIGNAL ;
    PORT
      LAYER M4 ;
        RECT  0 36.912 0.084 36.936 ;
    END
  END o_data[242]
  PIN o_data[243]
    DIRECTION OUTPUT ;
    USE SIGNAL ;
    PORT
      LAYER M4 ;
        RECT  0 37.056 0.084 37.08 ;
    END
  END o_data[243]
  PIN o_data[244]
    DIRECTION OUTPUT ;
    USE SIGNAL ;
    PORT
      LAYER M4 ;
        RECT  0 37.152 0.084 37.176 ;
    END
  END o_data[244]
  PIN o_data[245]
    DIRECTION OUTPUT ;
    USE SIGNAL ;
    PORT
      LAYER M4 ;
        RECT  0 37.296 0.084 37.32 ;
    END
  END o_data[245]
  PIN o_data[246]
    DIRECTION OUTPUT ;
    USE SIGNAL ;
    PORT
      LAYER M4 ;
        RECT  0 37.44 0.084 37.464 ;
    END
  END o_data[246]
  PIN o_data[247]
    DIRECTION OUTPUT ;
    USE SIGNAL ;
    PORT
      LAYER M4 ;
        RECT  0 37.584 0.084 37.608 ;
    END
  END o_data[247]
  PIN o_data[248]
    DIRECTION OUTPUT ;
    USE SIGNAL ;
    PORT
      LAYER M4 ;
        RECT  0 37.728 0.084 37.752 ;
    END
  END o_data[248]
  PIN o_data[249]
    DIRECTION OUTPUT ;
    USE SIGNAL ;
    PORT
      LAYER M4 ;
        RECT  0 37.824 0.084 37.848 ;
    END
  END o_data[249]
  PIN o_data[24]
    DIRECTION OUTPUT ;
    USE SIGNAL ;
    PORT
      LAYER M4 ;
        RECT  0 7.728 0.084 7.752 ;
    END
  END o_data[24]
  PIN o_data[250]
    DIRECTION OUTPUT ;
    USE SIGNAL ;
    PORT
      LAYER M4 ;
        RECT  0 37.968 0.084 37.992 ;
    END
  END o_data[250]
  PIN o_data[251]
    DIRECTION OUTPUT ;
    USE SIGNAL ;
    PORT
      LAYER M4 ;
        RECT  0 38.112 0.084 38.136 ;
    END
  END o_data[251]
  PIN o_data[252]
    DIRECTION OUTPUT ;
    USE SIGNAL ;
    PORT
      LAYER M4 ;
        RECT  0 38.256 0.084 38.28 ;
    END
  END o_data[252]
  PIN o_data[253]
    DIRECTION OUTPUT ;
    USE SIGNAL ;
    PORT
      LAYER M4 ;
        RECT  0 38.4 0.084 38.424 ;
    END
  END o_data[253]
  PIN o_data[254]
    DIRECTION OUTPUT ;
    USE SIGNAL ;
    PORT
      LAYER M4 ;
        RECT  0 38.496 0.084 38.52 ;
    END
  END o_data[254]
  PIN o_data[255]
    DIRECTION OUTPUT ;
    USE SIGNAL ;
    PORT
      LAYER M4 ;
        RECT  0 38.64 0.084 38.664 ;
    END
  END o_data[255]
  PIN o_data[25]
    DIRECTION OUTPUT ;
    USE SIGNAL ;
    PORT
      LAYER M4 ;
        RECT  0 7.872 0.084 7.896 ;
    END
  END o_data[25]
  PIN o_data[26]
    DIRECTION OUTPUT ;
    USE SIGNAL ;
    PORT
      LAYER M4 ;
        RECT  0 8.016 0.084 8.04 ;
    END
  END o_data[26]
  PIN o_data[27]
    DIRECTION OUTPUT ;
    USE SIGNAL ;
    PORT
      LAYER M4 ;
        RECT  0 8.16 0.084 8.184 ;
    END
  END o_data[27]
  PIN o_data[28]
    DIRECTION OUTPUT ;
    USE SIGNAL ;
    PORT
      LAYER M4 ;
        RECT  0 8.256 0.084 8.28 ;
    END
  END o_data[28]
  PIN o_data[29]
    DIRECTION OUTPUT ;
    USE SIGNAL ;
    PORT
      LAYER M4 ;
        RECT  0 8.4 0.084 8.424 ;
    END
  END o_data[29]
  PIN o_data[2]
    DIRECTION OUTPUT ;
    USE SIGNAL ;
    PORT
      LAYER M4 ;
        RECT  0 4.8 0.084 4.824 ;
    END
  END o_data[2]
  PIN o_data[30]
    DIRECTION OUTPUT ;
    USE SIGNAL ;
    PORT
      LAYER M4 ;
        RECT  0 8.544 0.084 8.568 ;
    END
  END o_data[30]
  PIN o_data[31]
    DIRECTION OUTPUT ;
    USE SIGNAL ;
    PORT
      LAYER M4 ;
        RECT  0 8.688 0.084 8.712 ;
    END
  END o_data[31]
  PIN o_data[32]
    DIRECTION OUTPUT ;
    USE SIGNAL ;
    PORT
      LAYER M4 ;
        RECT  0 8.832 0.084 8.856 ;
    END
  END o_data[32]
  PIN o_data[33]
    DIRECTION OUTPUT ;
    USE SIGNAL ;
    PORT
      LAYER M4 ;
        RECT  0 8.928 0.084 8.952 ;
    END
  END o_data[33]
  PIN o_data[34]
    DIRECTION OUTPUT ;
    USE SIGNAL ;
    PORT
      LAYER M4 ;
        RECT  0 9.072 0.084 9.096 ;
    END
  END o_data[34]
  PIN o_data[35]
    DIRECTION OUTPUT ;
    USE SIGNAL ;
    PORT
      LAYER M4 ;
        RECT  0 9.216 0.084 9.24 ;
    END
  END o_data[35]
  PIN o_data[36]
    DIRECTION OUTPUT ;
    USE SIGNAL ;
    PORT
      LAYER M4 ;
        RECT  0 9.36 0.084 9.384 ;
    END
  END o_data[36]
  PIN o_data[37]
    DIRECTION OUTPUT ;
    USE SIGNAL ;
    PORT
      LAYER M4 ;
        RECT  0 9.504 0.084 9.528 ;
    END
  END o_data[37]
  PIN o_data[38]
    DIRECTION OUTPUT ;
    USE SIGNAL ;
    PORT
      LAYER M4 ;
        RECT  0 9.6 0.084 9.624 ;
    END
  END o_data[38]
  PIN o_data[39]
    DIRECTION OUTPUT ;
    USE SIGNAL ;
    PORT
      LAYER M4 ;
        RECT  0 9.744 0.084 9.768 ;
    END
  END o_data[39]
  PIN o_data[3]
    DIRECTION OUTPUT ;
    USE SIGNAL ;
    PORT
      LAYER M4 ;
        RECT  0 4.944 0.084 4.968 ;
    END
  END o_data[3]
  PIN o_data[40]
    DIRECTION OUTPUT ;
    USE SIGNAL ;
    PORT
      LAYER M4 ;
        RECT  0 9.888 0.084 9.912 ;
    END
  END o_data[40]
  PIN o_data[41]
    DIRECTION OUTPUT ;
    USE SIGNAL ;
    PORT
      LAYER M4 ;
        RECT  0 10.032 0.084 10.056 ;
    END
  END o_data[41]
  PIN o_data[42]
    DIRECTION OUTPUT ;
    USE SIGNAL ;
    PORT
      LAYER M4 ;
        RECT  0 10.128 0.084 10.152 ;
    END
  END o_data[42]
  PIN o_data[43]
    DIRECTION OUTPUT ;
    USE SIGNAL ;
    PORT
      LAYER M4 ;
        RECT  0 10.272 0.084 10.296 ;
    END
  END o_data[43]
  PIN o_data[44]
    DIRECTION OUTPUT ;
    USE SIGNAL ;
    PORT
      LAYER M4 ;
        RECT  0 10.416 0.084 10.44 ;
    END
  END o_data[44]
  PIN o_data[45]
    DIRECTION OUTPUT ;
    USE SIGNAL ;
    PORT
      LAYER M4 ;
        RECT  0 10.56 0.084 10.584 ;
    END
  END o_data[45]
  PIN o_data[46]
    DIRECTION OUTPUT ;
    USE SIGNAL ;
    PORT
      LAYER M4 ;
        RECT  0 10.704 0.084 10.728 ;
    END
  END o_data[46]
  PIN o_data[47]
    DIRECTION OUTPUT ;
    USE SIGNAL ;
    PORT
      LAYER M4 ;
        RECT  0 10.8 0.084 10.824 ;
    END
  END o_data[47]
  PIN o_data[48]
    DIRECTION OUTPUT ;
    USE SIGNAL ;
    PORT
      LAYER M4 ;
        RECT  0 10.944 0.084 10.968 ;
    END
  END o_data[48]
  PIN o_data[49]
    DIRECTION OUTPUT ;
    USE SIGNAL ;
    PORT
      LAYER M4 ;
        RECT  0 11.088 0.084 11.112 ;
    END
  END o_data[49]
  PIN o_data[4]
    DIRECTION OUTPUT ;
    USE SIGNAL ;
    PORT
      LAYER M4 ;
        RECT  0 5.088 0.084 5.112 ;
    END
  END o_data[4]
  PIN o_data[50]
    DIRECTION OUTPUT ;
    USE SIGNAL ;
    PORT
      LAYER M4 ;
        RECT  0 11.232 0.084 11.256 ;
    END
  END o_data[50]
  PIN o_data[51]
    DIRECTION OUTPUT ;
    USE SIGNAL ;
    PORT
      LAYER M4 ;
        RECT  0 11.376 0.084 11.4 ;
    END
  END o_data[51]
  PIN o_data[52]
    DIRECTION OUTPUT ;
    USE SIGNAL ;
    PORT
      LAYER M4 ;
        RECT  0 11.472 0.084 11.496 ;
    END
  END o_data[52]
  PIN o_data[53]
    DIRECTION OUTPUT ;
    USE SIGNAL ;
    PORT
      LAYER M4 ;
        RECT  0 11.616 0.084 11.64 ;
    END
  END o_data[53]
  PIN o_data[54]
    DIRECTION OUTPUT ;
    USE SIGNAL ;
    PORT
      LAYER M4 ;
        RECT  0 11.76 0.084 11.784 ;
    END
  END o_data[54]
  PIN o_data[55]
    DIRECTION OUTPUT ;
    USE SIGNAL ;
    PORT
      LAYER M4 ;
        RECT  0 11.904 0.084 11.928 ;
    END
  END o_data[55]
  PIN o_data[56]
    DIRECTION OUTPUT ;
    USE SIGNAL ;
    PORT
      LAYER M4 ;
        RECT  0 12.048 0.084 12.072 ;
    END
  END o_data[56]
  PIN o_data[57]
    DIRECTION OUTPUT ;
    USE SIGNAL ;
    PORT
      LAYER M4 ;
        RECT  0 12.144 0.084 12.168 ;
    END
  END o_data[57]
  PIN o_data[58]
    DIRECTION OUTPUT ;
    USE SIGNAL ;
    PORT
      LAYER M4 ;
        RECT  0 12.288 0.084 12.312 ;
    END
  END o_data[58]
  PIN o_data[59]
    DIRECTION OUTPUT ;
    USE SIGNAL ;
    PORT
      LAYER M4 ;
        RECT  0 12.432 0.084 12.456 ;
    END
  END o_data[59]
  PIN o_data[5]
    DIRECTION OUTPUT ;
    USE SIGNAL ;
    PORT
      LAYER M4 ;
        RECT  0 5.184 0.084 5.208 ;
    END
  END o_data[5]
  PIN o_data[60]
    DIRECTION OUTPUT ;
    USE SIGNAL ;
    PORT
      LAYER M4 ;
        RECT  0 12.576 0.084 12.6 ;
    END
  END o_data[60]
  PIN o_data[61]
    DIRECTION OUTPUT ;
    USE SIGNAL ;
    PORT
      LAYER M4 ;
        RECT  0 12.672 0.084 12.696 ;
    END
  END o_data[61]
  PIN o_data[62]
    DIRECTION OUTPUT ;
    USE SIGNAL ;
    PORT
      LAYER M4 ;
        RECT  0 12.816 0.084 12.84 ;
    END
  END o_data[62]
  PIN o_data[63]
    DIRECTION OUTPUT ;
    USE SIGNAL ;
    PORT
      LAYER M4 ;
        RECT  0 12.96 0.084 12.984 ;
    END
  END o_data[63]
  PIN o_data[64]
    DIRECTION OUTPUT ;
    USE SIGNAL ;
    PORT
      LAYER M4 ;
        RECT  0 13.104 0.084 13.128 ;
    END
  END o_data[64]
  PIN o_data[65]
    DIRECTION OUTPUT ;
    USE SIGNAL ;
    PORT
      LAYER M4 ;
        RECT  0 13.248 0.084 13.272 ;
    END
  END o_data[65]
  PIN o_data[66]
    DIRECTION OUTPUT ;
    USE SIGNAL ;
    PORT
      LAYER M4 ;
        RECT  0 13.344 0.084 13.368 ;
    END
  END o_data[66]
  PIN o_data[67]
    DIRECTION OUTPUT ;
    USE SIGNAL ;
    PORT
      LAYER M4 ;
        RECT  0 13.488 0.084 13.512 ;
    END
  END o_data[67]
  PIN o_data[68]
    DIRECTION OUTPUT ;
    USE SIGNAL ;
    PORT
      LAYER M4 ;
        RECT  0 13.632 0.084 13.656 ;
    END
  END o_data[68]
  PIN o_data[69]
    DIRECTION OUTPUT ;
    USE SIGNAL ;
    PORT
      LAYER M4 ;
        RECT  0 13.776 0.084 13.8 ;
    END
  END o_data[69]
  PIN o_data[6]
    DIRECTION OUTPUT ;
    USE SIGNAL ;
    PORT
      LAYER M4 ;
        RECT  0 5.328 0.084 5.352 ;
    END
  END o_data[6]
  PIN o_data[70]
    DIRECTION OUTPUT ;
    USE SIGNAL ;
    PORT
      LAYER M4 ;
        RECT  0 13.92 0.084 13.944 ;
    END
  END o_data[70]
  PIN o_data[71]
    DIRECTION OUTPUT ;
    USE SIGNAL ;
    PORT
      LAYER M4 ;
        RECT  0 14.016 0.084 14.04 ;
    END
  END o_data[71]
  PIN o_data[72]
    DIRECTION OUTPUT ;
    USE SIGNAL ;
    PORT
      LAYER M4 ;
        RECT  0 14.16 0.084 14.184 ;
    END
  END o_data[72]
  PIN o_data[73]
    DIRECTION OUTPUT ;
    USE SIGNAL ;
    PORT
      LAYER M4 ;
        RECT  0 14.304 0.084 14.328 ;
    END
  END o_data[73]
  PIN o_data[74]
    DIRECTION OUTPUT ;
    USE SIGNAL ;
    PORT
      LAYER M4 ;
        RECT  0 14.448 0.084 14.472 ;
    END
  END o_data[74]
  PIN o_data[75]
    DIRECTION OUTPUT ;
    USE SIGNAL ;
    PORT
      LAYER M4 ;
        RECT  0 14.544 0.084 14.568 ;
    END
  END o_data[75]
  PIN o_data[76]
    DIRECTION OUTPUT ;
    USE SIGNAL ;
    PORT
      LAYER M4 ;
        RECT  0 14.688 0.084 14.712 ;
    END
  END o_data[76]
  PIN o_data[77]
    DIRECTION OUTPUT ;
    USE SIGNAL ;
    PORT
      LAYER M4 ;
        RECT  0 14.832 0.084 14.856 ;
    END
  END o_data[77]
  PIN o_data[78]
    DIRECTION OUTPUT ;
    USE SIGNAL ;
    PORT
      LAYER M4 ;
        RECT  0 14.976 0.084 15 ;
    END
  END o_data[78]
  PIN o_data[79]
    DIRECTION OUTPUT ;
    USE SIGNAL ;
    PORT
      LAYER M4 ;
        RECT  0 15.12 0.084 15.144 ;
    END
  END o_data[79]
  PIN o_data[7]
    DIRECTION OUTPUT ;
    USE SIGNAL ;
    PORT
      LAYER M4 ;
        RECT  0 5.472 0.084 5.496 ;
    END
  END o_data[7]
  PIN o_data[80]
    DIRECTION OUTPUT ;
    USE SIGNAL ;
    PORT
      LAYER M4 ;
        RECT  0 15.216 0.084 15.24 ;
    END
  END o_data[80]
  PIN o_data[81]
    DIRECTION OUTPUT ;
    USE SIGNAL ;
    PORT
      LAYER M4 ;
        RECT  0 15.36 0.084 15.384 ;
    END
  END o_data[81]
  PIN o_data[82]
    DIRECTION OUTPUT ;
    USE SIGNAL ;
    PORT
      LAYER M4 ;
        RECT  0 15.504 0.084 15.528 ;
    END
  END o_data[82]
  PIN o_data[83]
    DIRECTION OUTPUT ;
    USE SIGNAL ;
    PORT
      LAYER M4 ;
        RECT  0 15.648 0.084 15.672 ;
    END
  END o_data[83]
  PIN o_data[84]
    DIRECTION OUTPUT ;
    USE SIGNAL ;
    PORT
      LAYER M4 ;
        RECT  0 15.792 0.084 15.816 ;
    END
  END o_data[84]
  PIN o_data[85]
    DIRECTION OUTPUT ;
    USE SIGNAL ;
    PORT
      LAYER M4 ;
        RECT  0 15.888 0.084 15.912 ;
    END
  END o_data[85]
  PIN o_data[86]
    DIRECTION OUTPUT ;
    USE SIGNAL ;
    PORT
      LAYER M4 ;
        RECT  0 16.032 0.084 16.056 ;
    END
  END o_data[86]
  PIN o_data[87]
    DIRECTION OUTPUT ;
    USE SIGNAL ;
    PORT
      LAYER M4 ;
        RECT  0 16.176 0.084 16.2 ;
    END
  END o_data[87]
  PIN o_data[88]
    DIRECTION OUTPUT ;
    USE SIGNAL ;
    PORT
      LAYER M4 ;
        RECT  0 16.32 0.084 16.344 ;
    END
  END o_data[88]
  PIN o_data[89]
    DIRECTION OUTPUT ;
    USE SIGNAL ;
    PORT
      LAYER M4 ;
        RECT  0 16.416 0.084 16.44 ;
    END
  END o_data[89]
  PIN o_data[8]
    DIRECTION OUTPUT ;
    USE SIGNAL ;
    PORT
      LAYER M4 ;
        RECT  0 5.616 0.084 5.64 ;
    END
  END o_data[8]
  PIN o_data[90]
    DIRECTION OUTPUT ;
    USE SIGNAL ;
    PORT
      LAYER M4 ;
        RECT  0 16.56 0.084 16.584 ;
    END
  END o_data[90]
  PIN o_data[91]
    DIRECTION OUTPUT ;
    USE SIGNAL ;
    PORT
      LAYER M4 ;
        RECT  0 16.704 0.084 16.728 ;
    END
  END o_data[91]
  PIN o_data[92]
    DIRECTION OUTPUT ;
    USE SIGNAL ;
    PORT
      LAYER M4 ;
        RECT  0 16.848 0.084 16.872 ;
    END
  END o_data[92]
  PIN o_data[93]
    DIRECTION OUTPUT ;
    USE SIGNAL ;
    PORT
      LAYER M4 ;
        RECT  0 16.992 0.084 17.016 ;
    END
  END o_data[93]
  PIN o_data[94]
    DIRECTION OUTPUT ;
    USE SIGNAL ;
    PORT
      LAYER M4 ;
        RECT  0 17.088 0.084 17.112 ;
    END
  END o_data[94]
  PIN o_data[95]
    DIRECTION OUTPUT ;
    USE SIGNAL ;
    PORT
      LAYER M4 ;
        RECT  0 17.232 0.084 17.256 ;
    END
  END o_data[95]
  PIN o_data[96]
    DIRECTION OUTPUT ;
    USE SIGNAL ;
    PORT
      LAYER M4 ;
        RECT  0 17.376 0.084 17.4 ;
    END
  END o_data[96]
  PIN o_data[97]
    DIRECTION OUTPUT ;
    USE SIGNAL ;
    PORT
      LAYER M4 ;
        RECT  0 17.52 0.084 17.544 ;
    END
  END o_data[97]
  PIN o_data[98]
    DIRECTION OUTPUT ;
    USE SIGNAL ;
    PORT
      LAYER M4 ;
        RECT  0 17.664 0.084 17.688 ;
    END
  END o_data[98]
  PIN o_data[99]
    DIRECTION OUTPUT ;
    USE SIGNAL ;
    PORT
      LAYER M4 ;
        RECT  0 17.76 0.084 17.784 ;
    END
  END o_data[99]
  PIN o_data[9]
    DIRECTION OUTPUT ;
    USE SIGNAL ;
    PORT
      LAYER M4 ;
        RECT  0 5.76 0.084 5.784 ;
    END
  END o_data[9]
  PIN o_row[0]
    DIRECTION OUTPUT ;
    USE SIGNAL ;
    PORT
      LAYER M4 ;
        RECT  0 38.784 0.084 38.808 ;
    END
  END o_row[0]
  PIN o_row[1]
    DIRECTION OUTPUT ;
    USE SIGNAL ;
    PORT
      LAYER M4 ;
        RECT  0 38.928 0.084 38.952 ;
    END
  END o_row[1]
  PIN o_row[2]
    DIRECTION OUTPUT ;
    USE SIGNAL ;
    PORT
      LAYER M4 ;
        RECT  0 39.024 0.084 39.048 ;
    END
  END o_row[2]
  PIN o_row[3]
    DIRECTION OUTPUT ;
    USE SIGNAL ;
    PORT
      LAYER M4 ;
        RECT  0 39.168 0.084 39.192 ;
    END
  END o_row[3]
  PIN o_row[4]
    DIRECTION OUTPUT ;
    USE SIGNAL ;
    PORT
      LAYER M4 ;
        RECT  0 39.312 0.084 39.336 ;
    END
  END o_row[4]
  PIN o_row[5]
    DIRECTION OUTPUT ;
    USE SIGNAL ;
    PORT
      LAYER M4 ;
        RECT  0 39.456 0.084 39.48 ;
    END
  END o_row[5]
  PIN o_row[6]
    DIRECTION OUTPUT ;
    USE SIGNAL ;
    PORT
      LAYER M4 ;
        RECT  0 39.6 0.084 39.624 ;
    END
  END o_row[6]
  PIN o_row[7]
    DIRECTION OUTPUT ;
    USE SIGNAL ;
    PORT
      LAYER M4 ;
        RECT  0 39.696 0.084 39.72 ;
    END
  END o_row[7]
  PIN o_sec[0]
    DIRECTION OUTPUT ;
    USE SIGNAL ;
    PORT
      LAYER M4 ;
        RECT  0 39.84 0.084 39.864 ;
    END
  END o_sec[0]
  PIN o_sec[10]
    DIRECTION OUTPUT ;
    USE SIGNAL ;
    PORT
      LAYER M4 ;
        RECT  0 41.184 0.084 41.208 ;
    END
  END o_sec[10]
  PIN o_sec[11]
    DIRECTION OUTPUT ;
    USE SIGNAL ;
    PORT
      LAYER M4 ;
        RECT  0 41.328 0.084 41.352 ;
    END
  END o_sec[11]
  PIN o_sec[12]
    DIRECTION OUTPUT ;
    USE SIGNAL ;
    PORT
      LAYER M4 ;
        RECT  0 41.472 0.084 41.496 ;
    END
  END o_sec[12]
  PIN o_sec[13]
    DIRECTION OUTPUT ;
    USE SIGNAL ;
    PORT
      LAYER M4 ;
        RECT  0 41.568 0.084 41.592 ;
    END
  END o_sec[13]
  PIN o_sec[14]
    DIRECTION OUTPUT ;
    USE SIGNAL ;
    PORT
      LAYER M4 ;
        RECT  0 41.712 0.084 41.736 ;
    END
  END o_sec[14]
  PIN o_sec[15]
    DIRECTION OUTPUT ;
    USE SIGNAL ;
    PORT
      LAYER M4 ;
        RECT  0 41.856 0.084 41.88 ;
    END
  END o_sec[15]
  PIN o_sec[16]
    DIRECTION OUTPUT ;
    USE SIGNAL ;
    PORT
      LAYER M4 ;
        RECT  0 42 0.084 42.024 ;
    END
  END o_sec[16]
  PIN o_sec[1]
    DIRECTION OUTPUT ;
    USE SIGNAL ;
    PORT
      LAYER M4 ;
        RECT  0 39.984 0.084 40.008 ;
    END
  END o_sec[1]
  PIN o_sec[2]
    DIRECTION OUTPUT ;
    USE SIGNAL ;
    PORT
      LAYER M4 ;
        RECT  0 40.128 0.084 40.152 ;
    END
  END o_sec[2]
  PIN o_sec[3]
    DIRECTION OUTPUT ;
    USE SIGNAL ;
    PORT
      LAYER M4 ;
        RECT  0 40.272 0.084 40.296 ;
    END
  END o_sec[3]
  PIN o_sec[4]
    DIRECTION OUTPUT ;
    USE SIGNAL ;
    PORT
      LAYER M4 ;
        RECT  0 40.368 0.084 40.392 ;
    END
  END o_sec[4]
  PIN o_sec[5]
    DIRECTION OUTPUT ;
    USE SIGNAL ;
    PORT
      LAYER M4 ;
        RECT  0 40.512 0.084 40.536 ;
    END
  END o_sec[5]
  PIN o_sec[6]
    DIRECTION OUTPUT ;
    USE SIGNAL ;
    PORT
      LAYER M4 ;
        RECT  0 40.656 0.084 40.68 ;
    END
  END o_sec[6]
  PIN o_sec[7]
    DIRECTION OUTPUT ;
    USE SIGNAL ;
    PORT
      LAYER M4 ;
        RECT  0 40.8 0.084 40.824 ;
    END
  END o_sec[7]
  PIN o_sec[8]
    DIRECTION OUTPUT ;
    USE SIGNAL ;
    PORT
      LAYER M4 ;
        RECT  0 40.896 0.084 40.92 ;
    END
  END o_sec[8]
  PIN o_sec[9]
    DIRECTION OUTPUT ;
    USE SIGNAL ;
    PORT
      LAYER M4 ;
        RECT  0 41.04 0.084 41.064 ;
    END
  END o_sec[9]
  PIN o_v
    DIRECTION OUTPUT ;
    USE SIGNAL ;
    PORT
      LAYER M4 ;
        RECT  0 42.144 0.084 42.168 ;
    END
  END o_v
  PIN VDD
    DIRECTION INOUT ;
    USE POWER ;
    PORT
      LAYER M5 ;
        RECT  34.992 2.151 35.112 41.049 ;
        RECT  29.592 2.151 29.712 41.049 ;
        RECT  24.192 2.151 24.312 41.049 ;
        RECT  18.792 2.151 18.912 41.049 ;
        RECT  13.392 2.151 13.512 41.049 ;
        RECT  7.992 2.151 8.112 41.049 ;
        RECT  2.592 2.151 2.712 41.049 ;
    END
  END VDD
  PIN VSS
    DIRECTION INOUT ;
    USE GROUND ;
    PORT
      LAYER M5 ;
        RECT  34.8 2.137 34.92 41.063 ;
        RECT  29.4 2.137 29.52 41.063 ;
        RECT  24 2.137 24.12 41.063 ;
        RECT  18.6 2.137 18.72 41.063 ;
        RECT  13.2 2.137 13.32 41.063 ;
        RECT  7.8 2.137 7.92 41.063 ;
        RECT  2.4 2.137 2.52 41.063 ;
    END
  END VSS
  # OT_OBS_CLOSED layer=M5 d_um=1.536 added=162
  OBS
    LAYER RVTN ;
     RECT  2.16 2.16 38.88 2.295 ;
     RECT  2.16 2.565 38.88 2.835 ;
     RECT  2.16 3.105 38.88 3.375 ;
     RECT  2.16 3.645 38.88 3.915 ;
     RECT  2.16 4.185 38.88 4.455 ;
     RECT  2.16 4.725 38.88 4.995 ;
     RECT  2.16 5.265 38.88 5.535 ;
     RECT  2.16 5.805 38.88 6.075 ;
     RECT  2.16 6.345 38.88 6.615 ;
     RECT  2.16 6.885 38.88 7.155 ;
     RECT  2.16 7.425 38.88 7.695 ;
     RECT  2.16 7.965 38.88 8.235 ;
     RECT  2.16 8.505 38.88 8.775 ;
     RECT  2.16 9.045 38.88 9.315 ;
     RECT  2.16 9.585 38.88 9.855 ;
     RECT  2.16 10.125 38.88 10.395 ;
     RECT  2.16 10.665 38.88 10.935 ;
     RECT  2.16 11.205 38.88 11.475 ;
     RECT  2.16 11.745 38.88 12.015 ;
     RECT  2.16 12.285 38.88 12.555 ;
     RECT  2.16 12.825 38.88 13.095 ;
     RECT  2.16 13.365 38.88 13.635 ;
     RECT  2.16 13.905 38.88 14.175 ;
     RECT  2.16 14.445 38.88 14.715 ;
     RECT  2.16 14.985 38.88 15.255 ;
     RECT  2.16 15.525 38.88 15.795 ;
     RECT  2.16 16.065 38.88 16.335 ;
     RECT  2.16 16.605 38.88 16.875 ;
     RECT  2.16 17.145 38.88 17.415 ;
     RECT  2.16 17.685 38.88 17.955 ;
     RECT  2.16 18.225 38.88 18.495 ;
     RECT  2.16 18.765 38.88 19.035 ;
     RECT  2.16 19.305 38.88 19.575 ;
     RECT  2.16 19.845 38.88 20.115 ;
     RECT  2.16 20.385 38.88 20.655 ;
     RECT  2.16 20.925 38.88 21.195 ;
     RECT  2.16 21.465 38.88 21.735 ;
     RECT  2.16 22.005 38.88 22.275 ;
     RECT  2.16 22.545 38.88 22.815 ;
     RECT  2.16 23.085 38.88 23.355 ;
     RECT  2.16 23.625 38.88 23.895 ;
     RECT  2.16 24.165 38.88 24.435 ;
     RECT  2.16 24.705 38.88 24.975 ;
     RECT  2.16 25.245 38.88 25.515 ;
     RECT  2.16 25.785 38.88 26.055 ;
     RECT  2.16 26.325 38.88 26.595 ;
     RECT  2.16 26.865 38.88 27.135 ;
     RECT  2.16 27.405 38.88 27.675 ;
     RECT  2.16 27.945 38.88 28.215 ;
     RECT  2.16 28.485 38.88 28.755 ;
     RECT  2.16 29.025 38.88 29.295 ;
     RECT  2.16 29.565 38.88 29.835 ;
     RECT  2.16 30.105 38.88 30.375 ;
     RECT  2.16 30.645 38.88 30.915 ;
     RECT  2.16 31.185 38.88 31.455 ;
     RECT  2.16 31.725 38.88 31.995 ;
     RECT  2.16 32.265 38.88 32.535 ;
     RECT  2.16 32.805 38.88 33.075 ;
     RECT  2.16 33.345 38.88 33.615 ;
     RECT  2.16 33.885 38.88 34.155 ;
     RECT  2.16 34.425 38.88 34.695 ;
     RECT  2.16 34.965 38.88 35.235 ;
     RECT  2.16 35.505 38.88 35.775 ;
     RECT  2.16 36.045 38.88 36.315 ;
     RECT  2.16 36.585 38.88 36.855 ;
     RECT  2.16 37.125 38.88 37.395 ;
     RECT  2.16 37.665 38.88 37.935 ;
     RECT  2.16 38.205 38.88 38.475 ;
     RECT  2.16 38.745 38.88 39.015 ;
     RECT  2.16 39.285 38.88 39.555 ;
     RECT  2.16 39.825 38.88 40.095 ;
     RECT  2.16 40.365 38.88 40.635 ;
     RECT  2.16 40.905 38.88 41.04 ;
    LAYER RVTP ;
     RECT  2.16 2.295 38.88 2.565 ;
     RECT  2.16 2.835 38.88 3.105 ;
     RECT  2.16 3.375 38.88 3.645 ;
     RECT  2.16 3.915 38.88 4.185 ;
     RECT  2.16 4.455 38.88 4.725 ;
     RECT  2.16 4.995 38.88 5.265 ;
     RECT  2.16 5.535 38.88 5.805 ;
     RECT  2.16 6.075 38.88 6.345 ;
     RECT  2.16 6.615 38.88 6.885 ;
     RECT  2.16 7.155 38.88 7.425 ;
     RECT  2.16 7.695 38.88 7.965 ;
     RECT  2.16 8.235 38.88 8.505 ;
     RECT  2.16 8.775 38.88 9.045 ;
     RECT  2.16 9.315 38.88 9.585 ;
     RECT  2.16 9.855 38.88 10.125 ;
     RECT  2.16 10.395 38.88 10.665 ;
     RECT  2.16 10.935 38.88 11.205 ;
     RECT  2.16 11.475 38.88 11.745 ;
     RECT  2.16 12.015 38.88 12.285 ;
     RECT  2.16 12.555 38.88 12.825 ;
     RECT  2.16 13.095 38.88 13.365 ;
     RECT  2.16 13.635 38.88 13.905 ;
     RECT  2.16 14.175 38.88 14.445 ;
     RECT  2.16 14.715 38.88 14.985 ;
     RECT  2.16 15.255 38.88 15.525 ;
     RECT  2.16 15.795 38.88 16.065 ;
     RECT  2.16 16.335 38.88 16.605 ;
     RECT  2.16 16.875 38.88 17.145 ;
     RECT  2.16 17.415 38.88 17.685 ;
     RECT  2.16 17.955 38.88 18.225 ;
     RECT  2.16 18.495 38.88 18.765 ;
     RECT  2.16 19.035 38.88 19.305 ;
     RECT  2.16 19.575 38.88 19.845 ;
     RECT  2.16 20.115 38.88 20.385 ;
     RECT  2.16 20.655 38.88 20.925 ;
     RECT  2.16 21.195 38.88 21.465 ;
     RECT  2.16 21.735 38.88 22.005 ;
     RECT  2.16 22.275 38.88 22.545 ;
     RECT  2.16 22.815 38.88 23.085 ;
     RECT  2.16 23.355 38.88 23.625 ;
     RECT  2.16 23.895 38.88 24.165 ;
     RECT  2.16 24.435 38.88 24.705 ;
     RECT  2.16 24.975 38.88 25.245 ;
     RECT  2.16 25.515 38.88 25.785 ;
     RECT  2.16 26.055 38.88 26.325 ;
     RECT  2.16 26.595 38.88 26.865 ;
     RECT  2.16 27.135 38.88 27.405 ;
     RECT  2.16 27.675 38.88 27.945 ;
     RECT  2.16 28.215 38.88 28.485 ;
     RECT  2.16 28.755 38.88 29.025 ;
     RECT  2.16 29.295 38.88 29.565 ;
     RECT  2.16 29.835 38.88 30.105 ;
     RECT  2.16 30.375 38.88 30.645 ;
     RECT  2.16 30.915 38.88 31.185 ;
     RECT  2.16 31.455 38.88 31.725 ;
     RECT  2.16 31.995 38.88 32.265 ;
     RECT  2.16 32.535 38.88 32.805 ;
     RECT  2.16 33.075 38.88 33.345 ;
     RECT  2.16 33.615 38.88 33.885 ;
     RECT  2.16 34.155 38.88 34.425 ;
     RECT  2.16 34.695 38.88 34.965 ;
     RECT  2.16 35.235 38.88 35.505 ;
     RECT  2.16 35.775 38.88 36.045 ;
     RECT  2.16 36.315 38.88 36.585 ;
     RECT  2.16 36.855 38.88 37.125 ;
     RECT  2.16 37.395 38.88 37.665 ;
     RECT  2.16 37.935 38.88 38.205 ;
     RECT  2.16 38.475 38.88 38.745 ;
     RECT  2.16 39.015 38.88 39.285 ;
     RECT  2.16 39.555 38.88 39.825 ;
     RECT  2.16 40.095 38.88 40.365 ;
     RECT  2.16 40.635 38.88 40.905 ;
    LAYER M1 ;
     RECT  2.16 2.151 38.88 41.049 ;
    LAYER M2 ;
     RECT  0.067 6.012 0.103 6.03 ;
     RECT  0.067 1.881 0.167 1.899 ;
     RECT  0.103 28.764 0.203 28.782 ;
     RECT  0.175 25.686 0.275 25.704 ;
     RECT  0.211 39.996 0.311 40.014 ;
     RECT  0.499 22.896 0.535 22.914 ;
     RECT  0.103 5.31 0.571 6.03 ;
     RECT  0.571 5.238 0.823 6.03 ;
     RECT  1.723 4.392 1.759 4.41 ;
     RECT  0.823 5.238 1.759 6.678 ;
     RECT  1.399 10.134 2.011 10.152 ;
     RECT  1.759 4.392 2.083 6.678 ;
     RECT  2.155 2.196 2.16 2.214 ;
     RECT  2.083 3.996 2.16 6.678 ;
     RECT  0.535 7.74 2.16 7.758 ;
     RECT  0.103 8.856 2.16 8.874 ;
     RECT  2.011 9.936 2.16 10.152 ;
     RECT  0.535 11.826 2.16 11.844 ;
     RECT  1.723 14.418 2.16 14.436 ;
     RECT  0.535 17.496 2.16 17.514 ;
     RECT  0.535 20.394 2.16 20.412 ;
     RECT  0.535 22.554 2.16 23.148 ;
     RECT  0.535 25.866 2.16 25.884 ;
     RECT  0.535 30.726 2.16 30.744 ;
     RECT  0.535 31.806 2.16 32.364 ;
     RECT  0.103 33.696 2.16 33.714 ;
     RECT  0.535 36.936 2.16 36.954 ;
     RECT  0.535 39.294 2.16 39.312 ;
     RECT  0.535 40.986 2.16 41.004 ;
     RECT  2.16 2.151 2.299 41.049 ;
     RECT  2.299 2.151 2.615 41.094 ;
     RECT  2.615 2.151 2.659 41.049 ;
     RECT  2.659 2.034 10.103 41.049 ;
     RECT  10.103 2.151 12.127 41.049 ;
     RECT  12.127 2.106 13.127 41.049 ;
     RECT  13.127 2.151 38.88 41.049 ;
     RECT  38.88 4.392 39.047 5.328 ;
     RECT  39.047 4.392 39.299 4.986 ;
     RECT  39.299 4.806 39.335 4.986 ;
     RECT  39.335 4.968 39.371 4.986 ;
    LAYER M3 ;
     RECT  39.204 0.091 39.222 0.139 ;
     RECT  2.412 0.043 2.43 0.173 ;
     RECT  8.316 0.091 8.334 0.221 ;
     RECT  13.572 0.091 13.59 0.365 ;
     RECT  39.204 0.139 39.294 0.475 ;
     RECT  38.7 0.475 39.294 0.523 ;
     RECT  4.824 0.043 4.842 0.571 ;
     RECT  37.116 0.475 37.134 0.571 ;
     RECT  36.576 0.571 37.134 1.099 ;
     RECT  37.98 0.523 39.294 1.099 ;
     RECT  2.304 0.571 2.322 1.195 ;
     RECT  1.764 1.195 2.322 1.723 ;
     RECT  4.788 0.571 4.842 1.723 ;
     RECT  7.236 1.099 7.254 1.723 ;
     RECT  21.276 1.675 21.294 1.723 ;
     RECT  23.76 0.523 23.778 1.723 ;
     RECT  36.576 1.099 39.366 1.723 ;
     RECT  1.764 1.723 4.05 1.771 ;
     RECT  4.788 1.723 5.382 1.771 ;
     RECT  6.336 0.091 6.354 1.771 ;
     RECT  7.2 1.723 8.406 1.771 ;
     RECT  11.988 1.147 12.006 1.771 ;
     RECT  12.78 1.723 12.798 1.771 ;
     RECT  13.896 1.723 30.438 1.771 ;
     RECT  31.356 1.723 32.67 1.771 ;
     RECT  11.484 1.771 12.798 1.819 ;
     RECT  13.896 1.771 33.786 1.819 ;
     RECT  34.596 1.723 39.366 1.819 ;
     RECT  0.108 1.435 0.126 1.867 ;
     RECT  0.108 1.867 0.162 1.876 ;
     RECT  13.896 1.819 39.366 2.011 ;
     RECT  11.484 1.819 12.834 2.101 ;
     RECT  13.572 2.011 39.366 2.101 ;
     RECT  1.764 1.771 6.354 2.191 ;
     RECT  7.2 1.771 9.018 2.191 ;
     RECT  10.008 1.723 10.386 2.191 ;
     RECT  11.484 2.101 39.366 2.191 ;
     RECT  0.072 1.876 0.162 2.395 ;
     RECT  1.764 2.191 39.366 3.979 ;
     RECT  1.728 3.979 39.366 4.415 ;
     RECT  1.764 4.415 39.366 4.955 ;
     RECT  1.8 4.955 39.366 4.991 ;
     RECT  1.8 4.991 39.042 5.333 ;
     RECT  0.072 2.395 0.846 6.035 ;
     RECT  0.144 6.035 0.846 6.091 ;
     RECT  1.8 5.333 38.754 6.091 ;
     RECT  0.144 6.091 38.754 6.539 ;
     RECT  0.144 6.539 38.718 6.653 ;
     RECT  0.54 6.653 38.718 6.683 ;
     RECT  1.404 6.683 38.718 7.385 ;
     RECT  0.54 6.683 0.558 7.763 ;
     RECT  1.404 7.385 38.682 8.395 ;
     RECT  1.152 8.395 38.682 8.401 ;
     RECT  1.152 8.401 38.754 8.525 ;
     RECT  0.324 8.155 0.342 8.683 ;
     RECT  1.404 8.525 38.754 8.699 ;
     RECT  0.216 8.683 0.342 8.827 ;
     RECT  0.108 8.827 0.342 8.851 ;
     RECT  0.108 8.851 0.558 8.879 ;
     RECT  0.252 8.879 0.558 9.629 ;
     RECT  1.404 8.699 38.718 9.959 ;
     RECT  1.404 9.959 1.422 10.157 ;
     RECT  0.144 9.739 0.162 10.411 ;
     RECT  0.144 10.411 0.234 10.637 ;
     RECT  2.268 9.959 38.718 10.931 ;
     RECT  0.144 10.637 0.162 11.515 ;
     RECT  2.376 10.931 38.718 11.713 ;
     RECT  2.304 11.713 38.718 11.755 ;
     RECT  0.144 11.515 0.198 11.821 ;
     RECT  0.144 11.821 0.558 12.077 ;
     RECT  0.144 12.077 0.342 12.701 ;
     RECT  1.728 11.755 38.718 13.667 ;
     RECT  0.144 12.701 0.162 13.805 ;
     RECT  1.728 13.667 38.574 14.441 ;
     RECT  2.304 14.441 38.574 14.819 ;
     RECT  2.34 14.819 38.574 15.089 ;
     RECT  0.144 14.539 0.162 15.149 ;
     RECT  2.415 15.089 38.574 15.835 ;
     RECT  2.34 15.835 38.574 16.133 ;
     RECT  2.34 16.133 38.538 16.141 ;
     RECT  1.116 17.083 1.134 17.213 ;
     RECT  2.304 16.141 38.538 17.221 ;
     RECT  0.144 16.699 0.162 17.491 ;
     RECT  2.268 17.221 38.538 17.789 ;
     RECT  0.144 17.491 0.558 18.173 ;
     RECT  0.324 18.173 0.558 18.317 ;
     RECT  0.324 18.317 0.342 18.989 ;
     RECT  0.144 19.099 0.162 19.853 ;
     RECT  2.304 17.789 38.538 20.489 ;
     RECT  0.54 20.389 0.558 20.635 ;
     RECT  0.144 20.635 0.558 20.765 ;
     RECT  2.376 20.489 38.538 20.849 ;
     RECT  0.54 20.765 0.558 21.293 ;
     RECT  2.415 20.849 38.538 21.775 ;
     RECT  2.34 21.775 38.538 22.072 ;
     RECT  0.144 21.643 0.162 22.549 ;
     RECT  2.304 22.072 38.538 22.649 ;
     RECT  0.144 22.549 0.558 23.981 ;
     RECT  2.376 22.649 38.538 24.187 ;
     RECT  2.304 24.187 38.538 24.269 ;
     RECT  0.144 23.981 0.522 24.365 ;
     RECT  0.144 24.365 0.162 25.517 ;
     RECT  0.18 25.672 0.198 25.681 ;
     RECT  2.415 24.269 38.538 25.781 ;
     RECT  2.415 25.781 38.07 25.825 ;
     RECT  0.18 25.681 0.27 25.861 ;
     RECT  2.34 25.825 38.07 25.915 ;
     RECT  2.304 25.915 38.07 25.979 ;
     RECT  0.18 25.861 0.558 26.093 ;
     RECT  0.54 26.093 0.558 26.477 ;
     RECT  0.144 26.827 0.234 27.245 ;
     RECT  0.216 27.245 0.234 27.293 ;
     RECT  2.34 25.979 38.07 27.547 ;
     RECT  2.196 27.547 38.07 27.677 ;
     RECT  0.144 28.219 0.162 28.315 ;
     RECT  0.144 28.315 0.342 28.493 ;
     RECT  0.144 28.493 0.198 28.759 ;
     RECT  0.108 28.759 0.198 28.925 ;
     RECT  0.18 28.925 0.198 28.973 ;
     RECT  0.324 29.419 0.342 29.597 ;
     RECT  2.304 27.677 38.07 30.235 ;
     RECT  2.268 30.235 38.07 30.451 ;
     RECT  2.268 30.451 38.358 30.479 ;
     RECT  2.268 30.479 23.202 30.557 ;
     RECT  0.144 30.475 0.162 30.721 ;
     RECT  24.015 30.479 38.358 30.839 ;
     RECT  29.304 30.839 38.358 30.875 ;
     RECT  0.144 30.721 0.558 31.037 ;
     RECT  24.015 30.839 28.53 31.253 ;
     RECT  29.376 30.875 38.358 31.253 ;
     RECT  2.268 30.557 23.022 31.289 ;
     RECT  6.192 31.289 23.022 31.379 ;
     RECT  24.015 31.253 27.558 31.451 ;
     RECT  22.716 31.379 23.022 31.459 ;
     RECT  0.144 31.037 0.162 31.565 ;
     RECT  24.015 31.451 27.018 31.661 ;
     RECT  25.092 31.661 27.018 31.685 ;
     RECT  22.716 31.459 23.094 31.793 ;
     RECT  26.208 31.685 27.018 31.793 ;
     RECT  26.208 31.793 26.982 31.805 ;
     RECT  22.716 31.793 23.058 31.829 ;
     RECT  26.604 31.805 26.982 31.829 ;
     RECT  22.716 31.829 22.842 31.919 ;
     RECT  26.964 31.829 26.982 31.919 ;
     RECT  2.268 31.289 5.418 31.997 ;
     RECT  6.192 31.379 21.762 32.107 ;
     RECT  22.716 31.919 22.806 32.107 ;
     RECT  2.376 31.997 5.418 32.155 ;
     RECT  6.192 32.107 22.806 32.155 ;
     RECT  28.512 31.253 28.53 32.161 ;
     RECT  29.415 31.253 38.358 32.161 ;
     RECT  28.512 32.161 38.358 32.189 ;
     RECT  2.376 32.155 22.806 32.297 ;
     RECT  2.376 32.297 22.086 32.459 ;
     RECT  2.376 32.459 21.978 32.495 ;
     RECT  29.088 32.189 38.358 32.495 ;
     RECT  25.092 31.685 25.218 32.611 ;
     RECT  0.54 31.801 0.558 32.669 ;
     RECT  25.092 32.611 25.254 32.801 ;
     RECT  29.415 32.495 38.358 32.801 ;
     RECT  25.236 32.801 25.254 32.837 ;
     RECT  2.376 32.495 21.69 32.872 ;
     RECT  29.415 32.801 37.35 33.035 ;
     RECT  30.78 33.035 37.35 33.269 ;
     RECT  2.304 32.872 21.69 33.313 ;
     RECT  30.78 33.269 37.098 33.413 ;
     RECT  2.304 33.313 21.762 33.449 ;
     RECT  2.415 33.449 21.762 33.547 ;
     RECT  2.415 33.547 21.87 33.611 ;
     RECT  22.788 33.511 22.806 33.611 ;
     RECT  0.108 33.691 0.126 33.728 ;
     RECT  21.42 33.611 21.87 33.809 ;
     RECT  29.415 33.035 29.697 33.817 ;
     RECT  30.78 33.413 37.062 33.817 ;
     RECT  2.415 33.611 20.682 34.109 ;
     RECT  38.34 32.801 38.358 34.259 ;
     RECT  29.415 33.817 37.062 34.349 ;
     RECT  5.904 34.109 20.682 34.429 ;
     RECT  21.42 33.809 21.798 34.429 ;
     RECT  26.82 34.465 26.838 34.501 ;
     RECT  36.936 34.349 37.062 34.501 ;
     RECT  29.415 34.349 36.162 34.655 ;
     RECT  5.904 34.429 21.798 34.691 ;
     RECT  36.936 34.501 37.134 34.691 ;
     RECT  22.86 34.195 22.878 34.727 ;
     RECT  37.116 34.691 37.134 34.727 ;
     RECT  0.144 33.979 0.162 34.733 ;
     RECT  26.784 34.501 26.838 34.763 ;
     RECT  2.415 34.109 5.094 34.861 ;
     RECT  5.904 34.691 21.69 34.861 ;
     RECT  30.816 34.655 36.162 34.889 ;
     RECT  2.415 34.861 21.69 34.891 ;
     RECT  30.816 34.889 36.018 34.925 ;
     RECT  22.716 34.969 22.806 35.069 ;
     RECT  2.304 34.891 21.69 35.159 ;
     RECT  26.856 34.771 26.874 35.159 ;
     RECT  31.032 34.925 35.766 35.159 ;
     RECT  31.032 35.159 35.586 35.195 ;
     RECT  0.324 35.035 0.342 35.213 ;
     RECT  22.716 35.069 22.734 35.231 ;
     RECT  31.032 35.195 35.154 35.231 ;
     RECT  32.004 35.231 35.154 35.309 ;
     RECT  20.808 35.159 21.69 35.339 ;
     RECT  32.04 35.309 35.154 35.537 ;
     RECT  31.032 35.231 31.23 35.671 ;
     RECT  21.348 35.339 21.69 35.699 ;
     RECT  2.304 35.159 19.926 35.899 ;
     RECT  2.304 35.899 20.43 35.969 ;
     RECT  21.492 35.699 21.69 35.969 ;
     RECT  32.364 35.537 35.154 35.969 ;
     RECT  0.144 35.947 0.162 36.077 ;
     RECT  2.304 35.969 20.358 36.077 ;
     RECT  21.672 35.969 21.69 36.121 ;
     RECT  33.768 35.969 35.154 36.121 ;
     RECT  32.364 35.969 32.382 36.125 ;
     RECT  33.768 36.121 35.334 36.125 ;
     RECT  2.304 36.077 20.286 36.149 ;
     RECT  21.672 36.121 21.762 36.149 ;
     RECT  2.304 36.149 19.926 36.239 ;
     RECT  30.78 35.671 31.23 36.239 ;
     RECT  21.744 36.149 21.762 36.311 ;
     RECT  30.816 36.239 31.23 36.311 ;
     RECT  34.056 36.125 35.334 36.311 ;
     RECT  34.056 36.311 35.097 36.383 ;
     RECT  2.304 36.239 19.638 36.419 ;
     RECT  2.304 36.419 19.386 36.581 ;
     RECT  0.54 36.931 0.558 37.325 ;
     RECT  31.032 36.311 31.23 37.733 ;
     RECT  0.144 37.675 0.162 37.853 ;
     RECT  2.304 36.581 18.897 38.129 ;
     RECT  0.324 38.923 0.342 38.971 ;
     RECT  2.34 38.129 18.897 39.253 ;
     RECT  0.216 38.971 0.342 39.289 ;
     RECT  0.216 39.289 0.558 39.451 ;
     RECT  29.415 34.655 29.697 39.451 ;
     RECT  31.212 37.733 31.23 39.479 ;
     RECT  29.415 39.451 30.366 39.488 ;
     RECT  0.144 39.451 0.558 39.581 ;
     RECT  0.18 39.581 0.558 39.629 ;
     RECT  2.304 39.253 18.897 39.821 ;
     RECT  2.304 39.821 17.694 40.019 ;
     RECT  2.304 40.019 17.478 40.055 ;
     RECT  0.18 39.629 0.306 40.061 ;
     RECT  2.304 40.055 17.334 40.091 ;
     RECT  2.304 40.091 17.154 40.163 ;
     RECT  17.064 40.163 17.154 40.289 ;
     RECT  30.6 39.631 30.618 40.289 ;
     RECT  0.18 40.061 0.27 40.301 ;
     RECT  2.304 40.163 16.326 40.397 ;
     RECT  2.304 40.397 16.29 40.559 ;
     RECT  17.136 40.289 17.154 40.559 ;
     RECT  30.492 40.405 30.51 40.559 ;
     RECT  2.304 40.559 16.182 40.595 ;
     RECT  2.304 40.595 15.534 40.631 ;
     RECT  14.688 40.631 15.534 40.667 ;
     RECT  2.304 40.631 13.914 40.685 ;
     RECT  29.415 39.488 29.697 40.711 ;
     RECT  14.688 40.667 15.246 40.739 ;
     RECT  18.615 39.821 18.897 40.787 ;
     RECT  24.015 31.661 24.297 40.787 ;
     RECT  34.815 36.383 35.097 40.787 ;
     RECT  0.252 40.301 0.27 40.829 ;
     RECT  2.304 40.685 11.502 40.829 ;
     RECT  12.24 40.685 13.914 40.829 ;
     RECT  14.76 40.739 15.246 40.829 ;
     RECT  29.415 40.711 30.222 40.829 ;
     RECT  2.304 40.829 10.926 40.865 ;
     RECT  12.708 40.829 13.914 40.877 ;
     RECT  3.6 40.865 10.926 40.901 ;
     RECT  4.932 40.901 10.926 40.925 ;
     RECT  3.6 40.901 3.942 40.937 ;
     RECT  4.932 40.925 5.814 40.937 ;
     RECT  6.804 40.925 10.926 40.937 ;
     RECT  6.804 40.937 8.226 40.973 ;
     RECT  9 40.937 10.494 40.973 ;
     RECT  12.708 40.877 13.878 40.973 ;
     RECT  15.228 40.829 15.246 40.973 ;
     RECT  6.804 40.973 7.905 41.009 ;
     RECT  9.864 40.973 10.494 41.009 ;
     RECT  13.176 40.973 13.698 41.009 ;
     RECT  6.912 41.009 7.905 41.057 ;
     RECT  13.215 41.009 13.305 41.057 ;
     RECT  18.615 40.787 18.705 41.057 ;
     RECT  24.015 40.787 24.105 41.057 ;
     RECT  29.415 40.829 30.078 41.057 ;
     RECT  34.815 40.787 34.905 41.057 ;
     RECT  2.304 40.865 2.826 41.099 ;
     RECT  2.592 41.099 2.826 41.117 ;
     RECT  2.808 41.117 2.826 41.213 ;
     RECT  0.54 40.981 0.558 41.357 ;
     RECT  3.6 40.937 3.618 41.501 ;
     RECT  4.932 40.937 5.562 41.597 ;
     RECT  5.364 41.597 5.562 41.741 ;
     RECT  6.912 41.057 7.47 41.885 ;
     RECT  7.452 41.885 7.47 42.029 ;
     RECT  5.544 41.741 5.562 42.173 ;
     RECT  30.06 41.057 30.078 43.085 ;
    LAYER M4 ;
     RECT  0.084 1.056 0.275 1.08 ;
     RECT  0.06 1.08 0.275 1.2 ;
     RECT  0.084 1.2 0.275 1.224 ;
     RECT  0.06 1.224 0.275 1.344 ;
     RECT  0.084 1.344 0.275 1.368 ;
     RECT  0.06 1.368 0.275 1.44 ;
     RECT  0.084 1.44 0.275 1.464 ;
     RECT  0.06 1.464 0.275 1.584 ;
     RECT  0.084 1.584 0.275 1.608 ;
     RECT  0.06 1.608 0.275 1.728 ;
     RECT  0.084 1.728 0.275 1.752 ;
     RECT  0.06 1.752 0.275 1.872 ;
     RECT  0.084 1.872 0.275 1.896 ;
     RECT  0.06 1.896 0.275 1.968 ;
     RECT  0.084 1.968 0.275 1.992 ;
     RECT  0.06 1.992 0.275 2.112 ;
     RECT  0.084 2.112 0.275 2.136 ;
     RECT  0.06 2.136 0.275 2.256 ;
     RECT  0.084 2.256 0.275 2.28 ;
     RECT  0.06 2.28 0.275 2.4 ;
     RECT  0.084 2.4 0.275 2.424 ;
     RECT  0.06 2.424 0.275 2.544 ;
     RECT  0.084 2.544 0.275 2.568 ;
     RECT  0.06 2.568 0.275 2.64 ;
     RECT  0.084 2.64 0.275 2.664 ;
     RECT  0.06 2.664 0.275 2.784 ;
     RECT  0.084 2.784 0.275 2.808 ;
     RECT  0.06 2.808 0.275 2.928 ;
     RECT  0.084 2.928 0.275 2.952 ;
     RECT  0.06 2.952 0.275 3.072 ;
     RECT  0.084 3.072 0.275 3.096 ;
     RECT  0.06 3.096 0.275 3.216 ;
     RECT  0.084 3.216 0.275 3.24 ;
     RECT  0.06 3.24 0.275 3.312 ;
     RECT  0.084 3.312 0.275 3.336 ;
     RECT  0.06 3.336 0.275 3.456 ;
     RECT  0.084 3.456 0.275 3.48 ;
     RECT  0.06 3.48 0.275 3.6 ;
     RECT  0.084 3.6 0.275 3.624 ;
     RECT  0.06 3.624 0.275 3.744 ;
     RECT  0.084 3.744 0.275 3.768 ;
     RECT  0.06 3.768 0.275 3.888 ;
     RECT  0.084 3.888 0.275 3.912 ;
     RECT  0.06 3.912 0.275 3.984 ;
     RECT  0.084 3.984 0.275 4.008 ;
     RECT  0.06 4.008 0.275 4.128 ;
     RECT  0.084 4.128 0.275 4.152 ;
     RECT  0.06 4.152 0.275 4.272 ;
     RECT  0.084 4.272 0.275 4.296 ;
     RECT  0.06 4.296 0.275 4.416 ;
     RECT  0.084 4.416 0.275 4.44 ;
     RECT  0.06 4.44 0.275 4.512 ;
     RECT  0.084 4.512 0.275 4.536 ;
     RECT  0.06 4.536 0.275 4.656 ;
     RECT  0.084 4.656 0.275 4.68 ;
     RECT  0.06 4.68 0.275 4.8 ;
     RECT  0.084 4.8 0.275 4.824 ;
     RECT  0.06 4.824 0.275 4.944 ;
     RECT  0.084 4.944 0.275 4.968 ;
     RECT  0.06 4.968 0.275 5.088 ;
     RECT  0.084 5.088 0.275 5.112 ;
     RECT  0.06 5.112 0.275 5.184 ;
     RECT  0.084 5.184 0.275 5.208 ;
     RECT  0.06 5.208 0.275 5.328 ;
     RECT  0.084 5.328 0.275 5.352 ;
     RECT  0.06 5.352 0.275 5.472 ;
     RECT  0.084 5.472 0.275 5.496 ;
     RECT  0.06 5.496 0.275 5.616 ;
     RECT  0.084 5.616 0.275 5.64 ;
     RECT  0.06 5.64 0.275 5.76 ;
     RECT  0.084 5.76 0.275 5.784 ;
     RECT  0.06 5.784 0.275 5.856 ;
     RECT  0.084 5.856 0.275 5.88 ;
     RECT  0.06 5.88 0.275 6 ;
     RECT  0.084 6 0.275 6.024 ;
     RECT  0.06 6.024 0.275 6.144 ;
     RECT  0.084 6.144 0.275 6.168 ;
     RECT  0.06 6.168 0.275 6.288 ;
     RECT  0.084 6.288 0.275 6.312 ;
     RECT  0.06 6.312 0.275 6.384 ;
     RECT  0.084 6.384 0.275 6.408 ;
     RECT  0.06 6.408 0.275 6.528 ;
     RECT  0.084 6.528 0.275 6.552 ;
     RECT  0.06 6.552 0.275 6.672 ;
     RECT  0.084 6.672 0.275 6.696 ;
     RECT  0.06 6.696 0.275 6.816 ;
     RECT  0.084 6.816 0.275 6.84 ;
     RECT  0.06 6.84 0.275 6.96 ;
     RECT  0.084 6.96 0.275 6.984 ;
     RECT  0.06 6.984 0.275 7.056 ;
     RECT  0.084 7.056 0.275 7.08 ;
     RECT  0.06 7.08 0.275 7.2 ;
     RECT  0.084 7.2 0.275 7.224 ;
     RECT  0.06 7.224 0.275 7.344 ;
     RECT  0.084 7.344 0.275 7.368 ;
     RECT  0.06 7.368 0.275 7.488 ;
     RECT  0.084 7.488 0.275 7.512 ;
     RECT  0.06 7.512 0.275 7.632 ;
     RECT  0.084 7.632 0.275 7.656 ;
     RECT  0.06 7.656 0.275 7.728 ;
     RECT  0.084 7.728 0.275 7.752 ;
     RECT  0.06 7.752 0.275 7.872 ;
     RECT  0.084 7.872 0.275 7.896 ;
     RECT  0.06 7.896 0.275 8.016 ;
     RECT  0.084 8.016 0.275 8.04 ;
     RECT  0.06 8.04 0.275 8.16 ;
     RECT  0.084 8.16 0.275 8.184 ;
     RECT  0.06 8.184 0.275 8.256 ;
     RECT  0.084 8.256 0.275 8.28 ;
     RECT  0.06 8.28 0.275 8.4 ;
     RECT  0.084 8.4 0.275 8.424 ;
     RECT  0.06 8.424 0.275 8.544 ;
     RECT  0.084 8.544 0.275 8.568 ;
     RECT  0.06 8.568 0.275 8.688 ;
     RECT  0.084 8.688 0.275 8.712 ;
     RECT  0.06 8.712 0.275 8.832 ;
     RECT  0.084 8.832 0.275 8.856 ;
     RECT  0.06 8.856 0.275 8.928 ;
     RECT  0.084 8.928 0.275 8.952 ;
     RECT  0.06 8.952 0.275 9.072 ;
     RECT  0.084 9.072 0.275 9.096 ;
     RECT  0.06 9.096 0.275 9.216 ;
     RECT  0.084 9.216 0.275 9.24 ;
     RECT  0.06 9.24 0.275 9.36 ;
     RECT  0.084 9.36 0.275 9.384 ;
     RECT  0.06 9.384 0.275 9.504 ;
     RECT  0.084 9.504 0.275 9.528 ;
     RECT  0.06 9.528 0.275 9.6 ;
     RECT  0.084 9.6 0.275 9.624 ;
     RECT  0.06 9.624 0.275 9.744 ;
     RECT  0.084 9.744 0.275 9.768 ;
     RECT  0.06 9.768 0.275 9.888 ;
     RECT  0.084 9.888 0.275 9.912 ;
     RECT  0.06 9.912 0.275 10.032 ;
     RECT  0.084 10.032 0.275 10.056 ;
     RECT  0.06 10.056 0.275 10.128 ;
     RECT  0.084 10.128 0.275 10.152 ;
     RECT  0.06 10.152 0.275 10.272 ;
     RECT  0.084 10.272 0.275 10.296 ;
     RECT  0.06 10.296 0.275 10.416 ;
     RECT  0.084 10.416 0.275 10.44 ;
     RECT  0.06 10.44 0.275 10.56 ;
     RECT  0.084 10.56 0.275 10.584 ;
     RECT  0.06 10.584 0.275 10.704 ;
     RECT  0.084 10.704 0.275 10.728 ;
     RECT  0.06 10.728 0.275 10.8 ;
     RECT  0.084 10.8 0.275 10.824 ;
     RECT  0.06 10.824 0.275 10.944 ;
     RECT  0.084 10.944 0.275 10.968 ;
     RECT  0.06 10.968 0.275 11.088 ;
     RECT  0.084 11.088 0.275 11.112 ;
     RECT  0.06 11.112 0.275 11.232 ;
     RECT  0.084 11.232 0.275 11.256 ;
     RECT  0.06 11.256 0.275 11.376 ;
     RECT  0.084 11.376 0.275 11.4 ;
     RECT  0.06 11.4 0.275 11.472 ;
     RECT  0.084 11.472 0.275 11.496 ;
     RECT  0.06 11.496 0.275 11.616 ;
     RECT  0.084 11.616 0.275 11.64 ;
     RECT  0.06 11.64 0.275 11.76 ;
     RECT  0.084 11.76 0.275 11.784 ;
     RECT  0.06 11.784 0.275 11.904 ;
     RECT  0.084 11.904 0.275 11.928 ;
     RECT  0.06 11.928 0.275 12.048 ;
     RECT  0.084 12.048 0.275 12.072 ;
     RECT  0.06 12.072 0.275 12.144 ;
     RECT  0.084 12.144 0.275 12.168 ;
     RECT  0.06 12.168 0.275 12.288 ;
     RECT  0.084 12.288 0.275 12.312 ;
     RECT  0.06 12.312 0.275 12.432 ;
     RECT  0.084 12.432 0.275 12.456 ;
     RECT  0.06 12.456 0.275 12.576 ;
     RECT  0.084 12.576 0.275 12.6 ;
     RECT  0.06 12.6 0.275 12.672 ;
     RECT  0.084 12.672 0.275 12.696 ;
     RECT  0.06 12.696 0.275 12.816 ;
     RECT  0.084 12.816 0.275 12.84 ;
     RECT  0.06 12.84 0.275 12.96 ;
     RECT  0.084 12.96 0.275 12.984 ;
     RECT  0.06 12.984 0.275 13.104 ;
     RECT  0.084 13.104 0.275 13.128 ;
     RECT  0.06 13.128 0.275 13.248 ;
     RECT  0.084 13.248 0.275 13.272 ;
     RECT  0.06 13.272 0.275 13.344 ;
     RECT  0.084 13.344 0.275 13.368 ;
     RECT  0.06 13.368 0.275 13.488 ;
     RECT  0.084 13.488 0.275 13.512 ;
     RECT  0.06 13.512 0.275 13.632 ;
     RECT  0.084 13.632 0.275 13.656 ;
     RECT  0.06 13.656 0.275 13.776 ;
     RECT  0.084 13.776 0.275 13.8 ;
     RECT  0.06 13.8 0.275 13.92 ;
     RECT  0.084 13.92 0.275 13.944 ;
     RECT  0.06 13.944 0.275 14.016 ;
     RECT  0.084 14.016 0.275 14.04 ;
     RECT  0.06 14.04 0.275 14.16 ;
     RECT  0.084 14.16 0.275 14.184 ;
     RECT  0.06 14.184 0.275 14.304 ;
     RECT  0.084 14.304 0.275 14.328 ;
     RECT  0.06 14.328 0.275 14.448 ;
     RECT  0.084 14.448 0.275 14.472 ;
     RECT  0.06 14.472 0.275 14.544 ;
     RECT  0.084 14.544 0.275 14.568 ;
     RECT  0.06 14.568 0.275 14.688 ;
     RECT  0.084 14.688 0.275 14.712 ;
     RECT  0.06 14.712 0.275 14.832 ;
     RECT  0.084 14.832 0.275 14.856 ;
     RECT  0.06 14.856 0.275 14.976 ;
     RECT  0.084 14.976 0.275 15 ;
     RECT  0.06 15 0.275 15.12 ;
     RECT  0.084 15.12 0.275 15.144 ;
     RECT  0.06 15.144 0.275 15.216 ;
     RECT  0.084 15.216 0.275 15.24 ;
     RECT  0.06 15.24 0.275 15.36 ;
     RECT  0.084 15.36 0.275 15.384 ;
     RECT  0.06 15.384 0.275 15.504 ;
     RECT  0.084 15.504 0.275 15.528 ;
     RECT  0.06 15.528 0.275 15.648 ;
     RECT  0.084 15.648 0.275 15.672 ;
     RECT  0.06 15.672 0.275 15.792 ;
     RECT  0.084 15.792 0.275 15.816 ;
     RECT  0.06 15.816 0.275 15.888 ;
     RECT  0.084 15.888 0.275 15.912 ;
     RECT  0.06 15.912 0.275 16.032 ;
     RECT  0.084 16.032 0.275 16.056 ;
     RECT  0.06 16.056 0.275 16.176 ;
     RECT  0.084 16.176 0.275 16.2 ;
     RECT  0.06 16.2 0.275 16.32 ;
     RECT  0.084 16.32 0.275 16.344 ;
     RECT  0.06 16.344 0.275 16.416 ;
     RECT  0.084 16.416 0.275 16.44 ;
     RECT  0.06 16.44 0.275 16.56 ;
     RECT  0.084 16.56 0.275 16.584 ;
     RECT  0.06 16.584 0.275 16.704 ;
     RECT  0.084 16.704 0.275 16.728 ;
     RECT  0.06 16.728 0.275 16.848 ;
     RECT  0.084 16.848 0.275 16.872 ;
     RECT  0.06 16.872 0.275 16.992 ;
     RECT  0.084 16.992 0.275 17.016 ;
     RECT  0.06 17.016 0.275 17.088 ;
     RECT  0.084 17.088 0.275 17.112 ;
     RECT  0.06 17.112 0.275 17.232 ;
     RECT  0.084 17.232 0.275 17.256 ;
     RECT  0.06 17.256 0.275 17.376 ;
     RECT  0.084 17.376 0.275 17.4 ;
     RECT  0.06 17.4 0.275 17.52 ;
     RECT  0.084 17.52 0.275 17.544 ;
     RECT  0.06 17.544 0.275 17.664 ;
     RECT  0.084 17.664 0.275 17.688 ;
     RECT  0.06 17.688 0.275 17.76 ;
     RECT  0.084 17.76 0.275 17.784 ;
     RECT  0.06 17.784 0.275 17.904 ;
     RECT  0.084 17.904 0.275 17.928 ;
     RECT  0.06 17.928 0.275 18.048 ;
     RECT  0.084 18.048 0.275 18.072 ;
     RECT  0.06 18.072 0.275 18.192 ;
     RECT  0.084 18.192 0.275 18.216 ;
     RECT  0.06 18.216 0.275 18.288 ;
     RECT  0.084 18.288 0.275 18.312 ;
     RECT  0.06 18.312 0.275 18.432 ;
     RECT  0.084 18.432 0.275 18.456 ;
     RECT  0.06 18.456 0.275 18.576 ;
     RECT  0.084 18.576 0.275 18.6 ;
     RECT  0.06 18.6 0.275 18.72 ;
     RECT  0.084 18.72 0.275 18.744 ;
     RECT  0.06 18.744 0.275 18.864 ;
     RECT  0.084 18.864 0.275 18.888 ;
     RECT  0.06 18.888 0.275 18.96 ;
     RECT  0.084 18.96 0.275 18.984 ;
     RECT  0.06 18.984 0.275 19.104 ;
     RECT  0.084 19.104 0.275 19.128 ;
     RECT  0.06 19.128 0.275 19.248 ;
     RECT  0.084 19.248 0.275 19.272 ;
     RECT  0.06 19.272 0.275 19.392 ;
     RECT  0.084 19.392 0.275 19.416 ;
     RECT  0.06 19.416 0.275 19.536 ;
     RECT  0.084 19.536 0.275 19.56 ;
     RECT  0.06 19.56 0.275 19.632 ;
     RECT  0.084 19.632 0.275 19.656 ;
     RECT  0.06 19.656 0.275 19.776 ;
     RECT  0.084 19.776 0.275 19.8 ;
     RECT  0.06 19.8 0.275 19.92 ;
     RECT  0.084 19.92 0.275 19.944 ;
     RECT  0.06 19.944 0.275 20.064 ;
     RECT  0.084 20.064 0.275 20.088 ;
     RECT  0.06 20.088 0.275 20.16 ;
     RECT  0.084 20.16 0.275 20.184 ;
     RECT  0.06 20.184 0.275 20.304 ;
     RECT  0.084 20.304 0.275 20.328 ;
     RECT  0.06 20.328 0.275 20.448 ;
     RECT  0.084 20.448 0.275 20.472 ;
     RECT  0.06 20.472 0.275 20.592 ;
     RECT  0.084 20.592 0.275 20.616 ;
     RECT  0.06 20.616 0.275 20.736 ;
     RECT  0.084 20.736 0.275 20.76 ;
     RECT  0.06 20.76 0.275 20.832 ;
     RECT  0.084 20.832 0.275 20.856 ;
     RECT  0.06 20.856 0.275 20.976 ;
     RECT  0.084 20.976 0.275 21 ;
     RECT  0.06 21 0.275 21.12 ;
     RECT  0.084 21.12 0.275 21.144 ;
     RECT  0.06 21.144 0.275 21.264 ;
     RECT  0.084 21.264 0.275 21.288 ;
     RECT  0.06 21.288 0.275 21.408 ;
     RECT  0.084 21.408 0.275 21.432 ;
     RECT  0.06 21.432 0.275 21.504 ;
     RECT  0.084 21.504 0.275 21.528 ;
     RECT  0.06 21.528 0.275 21.648 ;
     RECT  0.084 21.648 0.275 21.672 ;
     RECT  0.06 21.672 0.275 21.792 ;
     RECT  0.084 21.792 0.275 21.816 ;
     RECT  0.06 21.816 0.275 21.936 ;
     RECT  0.084 21.936 0.275 21.96 ;
     RECT  0.06 21.96 0.275 22.08 ;
     RECT  0.084 22.08 0.275 22.104 ;
     RECT  0.06 22.104 0.275 22.176 ;
     RECT  0.084 22.176 0.275 22.2 ;
     RECT  0.06 22.2 0.275 22.32 ;
     RECT  0.084 22.32 0.275 22.344 ;
     RECT  0.06 22.344 0.275 22.464 ;
     RECT  0.084 22.464 0.275 22.488 ;
     RECT  0.06 22.488 0.275 22.608 ;
     RECT  0.084 22.608 0.275 22.632 ;
     RECT  0.06 22.632 0.275 22.704 ;
     RECT  0.084 22.704 0.275 22.728 ;
     RECT  0.06 22.728 0.275 22.848 ;
     RECT  0.084 22.848 0.275 22.872 ;
     RECT  0.06 22.872 0.275 22.992 ;
     RECT  0.084 22.992 0.275 23.016 ;
     RECT  0.06 23.016 0.275 23.136 ;
     RECT  0.084 23.136 0.275 23.16 ;
     RECT  0.06 23.16 0.275 23.28 ;
     RECT  0.084 23.28 0.275 23.304 ;
     RECT  0.06 23.304 0.275 23.376 ;
     RECT  0.084 23.376 0.275 23.4 ;
     RECT  0.06 23.4 0.275 23.52 ;
     RECT  0.084 23.52 0.275 23.544 ;
     RECT  0.06 23.544 0.275 23.664 ;
     RECT  0.084 23.664 0.275 23.688 ;
     RECT  0.06 23.688 0.275 23.808 ;
     RECT  0.084 23.808 0.275 23.832 ;
     RECT  0.06 23.832 0.275 23.952 ;
     RECT  0.084 23.952 0.275 23.976 ;
     RECT  0.06 23.976 0.275 24.048 ;
     RECT  0.084 24.048 0.275 24.072 ;
     RECT  0.06 24.072 0.275 24.192 ;
     RECT  0.084 24.192 0.275 24.216 ;
     RECT  0.06 24.216 0.275 24.336 ;
     RECT  0.084 24.336 0.275 24.36 ;
     RECT  0.06 24.36 0.275 24.48 ;
     RECT  0.084 24.48 0.275 24.504 ;
     RECT  0.06 24.504 0.275 24.576 ;
     RECT  0.084 24.576 0.275 24.6 ;
     RECT  0.06 24.6 0.275 24.72 ;
     RECT  0.084 24.72 0.275 24.744 ;
     RECT  0.06 24.744 0.275 24.864 ;
     RECT  0.084 24.864 0.275 24.888 ;
     RECT  0.06 24.888 0.275 25.008 ;
     RECT  0.084 25.008 0.275 25.032 ;
     RECT  0.06 25.032 0.275 25.152 ;
     RECT  0.084 25.152 0.275 25.176 ;
     RECT  0.06 25.176 0.275 25.248 ;
     RECT  0.084 25.248 0.275 25.272 ;
     RECT  0.06 25.272 0.275 25.392 ;
     RECT  0.084 25.392 0.275 25.416 ;
     RECT  0.06 25.416 0.275 25.536 ;
     RECT  0.084 25.536 0.275 25.56 ;
     RECT  0.06 25.56 0.275 25.68 ;
     RECT  0.084 25.68 0.275 25.704 ;
     RECT  0.06 25.704 0.275 25.824 ;
     RECT  0.084 25.824 0.275 25.848 ;
     RECT  0.06 25.848 0.275 25.92 ;
     RECT  0.084 25.92 0.275 25.944 ;
     RECT  0.06 25.944 0.275 26.064 ;
     RECT  0.084 26.064 0.275 26.088 ;
     RECT  0.06 26.088 0.275 26.208 ;
     RECT  0.084 26.208 0.275 26.232 ;
     RECT  0.06 26.232 0.275 26.352 ;
     RECT  0.084 26.352 0.275 26.376 ;
     RECT  0.06 26.376 0.275 26.448 ;
     RECT  0.084 26.448 0.275 26.472 ;
     RECT  0.06 26.472 0.275 26.592 ;
     RECT  0.084 26.592 0.275 26.616 ;
     RECT  0.06 26.616 0.275 26.736 ;
     RECT  0.084 26.736 0.275 26.76 ;
     RECT  0.06 26.76 0.275 26.88 ;
     RECT  0.084 26.88 0.275 26.904 ;
     RECT  0.06 26.904 0.275 27.024 ;
     RECT  0.084 27.024 0.275 27.048 ;
     RECT  0.06 27.048 0.275 27.12 ;
     RECT  0.084 27.12 0.275 27.144 ;
     RECT  0.06 27.144 0.275 27.264 ;
     RECT  0.084 27.264 0.275 27.288 ;
     RECT  0.06 27.288 0.275 27.408 ;
     RECT  0.084 27.408 0.275 27.432 ;
     RECT  0.06 27.432 0.275 27.552 ;
     RECT  0.084 27.552 0.275 27.576 ;
     RECT  0.06 27.576 0.275 27.696 ;
     RECT  0.084 27.696 0.275 27.72 ;
     RECT  0.06 27.72 0.275 27.792 ;
     RECT  0.084 27.792 0.275 27.816 ;
     RECT  0.06 27.816 0.275 27.936 ;
     RECT  0.084 27.936 0.275 27.96 ;
     RECT  0.06 27.96 0.275 28.08 ;
     RECT  0.084 28.08 0.275 28.104 ;
     RECT  0.06 28.104 0.275 28.224 ;
     RECT  0.084 28.224 0.275 28.248 ;
     RECT  0.06 28.248 0.275 28.32 ;
     RECT  0.084 28.32 0.275 28.344 ;
     RECT  0.06 28.344 0.275 28.464 ;
     RECT  0.084 28.464 0.275 28.488 ;
     RECT  0.06 28.488 0.275 28.608 ;
     RECT  0.084 28.608 0.275 28.632 ;
     RECT  0.06 28.632 0.275 28.752 ;
     RECT  0.084 28.752 0.275 28.776 ;
     RECT  0.06 28.776 0.275 28.896 ;
     RECT  0.084 28.896 0.275 28.92 ;
     RECT  0.06 28.92 0.275 28.992 ;
     RECT  0.084 28.992 0.275 29.016 ;
     RECT  0.06 29.016 0.275 29.136 ;
     RECT  0.084 29.136 0.275 29.16 ;
     RECT  0.06 29.16 0.275 29.28 ;
     RECT  0.084 29.28 0.275 29.304 ;
     RECT  0.06 29.304 0.275 29.424 ;
     RECT  0.084 29.424 0.275 29.448 ;
     RECT  0.06 29.448 0.275 29.568 ;
     RECT  0.084 29.568 0.275 29.592 ;
     RECT  0.06 29.592 0.275 29.664 ;
     RECT  0.084 29.664 0.275 29.688 ;
     RECT  0.06 29.688 0.275 29.808 ;
     RECT  0.084 29.808 0.275 29.832 ;
     RECT  0.06 29.832 0.275 29.952 ;
     RECT  0.084 29.952 0.275 29.976 ;
     RECT  0.06 29.976 0.275 30.096 ;
     RECT  0.084 30.096 0.275 30.12 ;
     RECT  0.06 30.12 0.275 30.24 ;
     RECT  0.084 30.24 0.275 30.264 ;
     RECT  0.06 30.264 0.275 30.336 ;
     RECT  0.084 30.336 0.275 30.36 ;
     RECT  0.06 30.36 0.275 30.48 ;
     RECT  0.084 30.48 0.275 30.504 ;
     RECT  0.06 30.504 0.275 30.624 ;
     RECT  0.084 30.624 0.275 30.648 ;
     RECT  0.06 30.648 0.275 30.768 ;
     RECT  0.084 30.768 0.275 30.792 ;
     RECT  0.06 30.792 0.275 30.864 ;
     RECT  0.084 30.864 0.275 30.888 ;
     RECT  0.06 30.888 0.275 31.008 ;
     RECT  0.084 31.008 0.275 31.032 ;
     RECT  0.06 31.032 0.275 31.152 ;
     RECT  0.084 31.152 0.275 31.176 ;
     RECT  0.06 31.176 0.275 31.296 ;
     RECT  0.084 31.296 0.275 31.32 ;
     RECT  0.06 31.32 0.275 31.44 ;
     RECT  0.084 31.44 0.275 31.464 ;
     RECT  0.06 31.464 0.275 31.536 ;
     RECT  0.084 31.536 0.275 31.56 ;
     RECT  0.06 31.56 0.275 31.68 ;
     RECT  0.084 31.68 0.275 31.704 ;
     RECT  0.06 31.704 0.275 31.824 ;
     RECT  0.084 31.824 0.275 31.848 ;
     RECT  0.06 31.848 0.275 31.968 ;
     RECT  0.084 31.968 0.275 31.992 ;
     RECT  0.06 31.992 0.275 32.112 ;
     RECT  0.084 32.112 0.275 32.136 ;
     RECT  0.06 32.136 0.275 32.208 ;
     RECT  0.084 32.208 0.275 32.232 ;
     RECT  0.06 32.232 0.275 32.352 ;
     RECT  0.084 32.352 0.275 32.376 ;
     RECT  0.06 32.376 0.275 32.496 ;
     RECT  0.084 32.496 0.275 32.52 ;
     RECT  0.06 32.52 0.275 32.64 ;
     RECT  0.084 32.64 0.275 32.664 ;
     RECT  0.06 32.664 0.275 32.736 ;
     RECT  0.084 32.736 0.275 32.76 ;
     RECT  0.06 32.76 0.275 32.88 ;
     RECT  0.084 32.88 0.275 32.904 ;
     RECT  0.06 32.904 0.275 33.024 ;
     RECT  0.084 33.024 0.275 33.048 ;
     RECT  0.06 33.048 0.275 33.168 ;
     RECT  0.084 33.168 0.275 33.192 ;
     RECT  0.06 33.192 0.275 33.312 ;
     RECT  0.084 33.312 0.275 33.336 ;
     RECT  0.06 33.336 0.275 33.408 ;
     RECT  0.084 33.408 0.275 33.432 ;
     RECT  0.06 33.432 0.275 33.552 ;
     RECT  0.084 33.552 0.275 33.576 ;
     RECT  0.06 33.576 0.275 33.696 ;
     RECT  0.084 33.696 0.275 33.72 ;
     RECT  0.06 33.72 0.275 33.84 ;
     RECT  0.084 33.84 0.275 33.864 ;
     RECT  0.06 33.864 0.275 33.984 ;
     RECT  0.084 33.984 0.275 34.008 ;
     RECT  0.06 34.008 0.275 34.08 ;
     RECT  0.084 34.08 0.275 34.104 ;
     RECT  0.06 34.104 0.275 34.224 ;
     RECT  0.084 34.224 0.275 34.248 ;
     RECT  0.06 34.248 0.275 34.368 ;
     RECT  0.084 34.368 0.275 34.392 ;
     RECT  0.06 34.392 0.275 34.512 ;
     RECT  0.084 34.512 0.275 34.536 ;
     RECT  0.06 34.536 0.275 34.608 ;
     RECT  0.084 34.608 0.275 34.632 ;
     RECT  0.06 34.632 0.275 34.752 ;
     RECT  0.084 34.752 0.275 34.776 ;
     RECT  0.06 34.776 0.275 34.896 ;
     RECT  0.084 34.896 0.275 34.92 ;
     RECT  0.06 34.92 0.275 35.04 ;
     RECT  0.084 35.04 0.275 35.064 ;
     RECT  0.06 35.064 0.275 35.184 ;
     RECT  0.084 35.184 0.275 35.208 ;
     RECT  0.06 35.208 0.275 35.28 ;
     RECT  0.084 35.28 0.275 35.304 ;
     RECT  0.06 35.304 0.275 35.424 ;
     RECT  0.084 35.424 0.275 35.448 ;
     RECT  0.06 35.448 0.275 35.568 ;
     RECT  0.084 35.568 0.275 35.592 ;
     RECT  0.06 35.592 0.275 35.712 ;
     RECT  0.084 35.712 0.275 35.736 ;
     RECT  0.06 35.736 0.275 35.856 ;
     RECT  0.084 35.856 0.275 35.88 ;
     RECT  0.06 35.88 0.275 35.952 ;
     RECT  0.084 35.952 0.275 35.976 ;
     RECT  0.06 35.976 0.275 36.096 ;
     RECT  0.084 36.096 0.275 36.12 ;
     RECT  0.06 36.12 0.275 36.24 ;
     RECT  0.084 36.24 0.275 36.264 ;
     RECT  0.06 36.264 0.275 36.384 ;
     RECT  0.084 36.384 0.275 36.408 ;
     RECT  0.06 36.408 0.275 36.48 ;
     RECT  0.084 36.48 0.275 36.504 ;
     RECT  0.06 36.504 0.275 36.624 ;
     RECT  0.084 36.624 0.275 36.648 ;
     RECT  0.06 36.648 0.275 36.768 ;
     RECT  0.084 36.768 0.275 36.792 ;
     RECT  0.06 36.792 0.275 36.912 ;
     RECT  0.084 36.912 0.275 36.936 ;
     RECT  0.06 36.936 0.275 37.056 ;
     RECT  0.084 37.056 0.275 37.08 ;
     RECT  0.06 37.08 0.275 37.152 ;
     RECT  0.084 37.152 0.275 37.176 ;
     RECT  0.06 37.176 0.275 37.296 ;
     RECT  0.084 37.296 0.275 37.32 ;
     RECT  0.06 37.32 0.275 37.44 ;
     RECT  0.084 37.44 0.275 37.464 ;
     RECT  0.06 37.464 0.275 37.584 ;
     RECT  0.084 37.584 0.275 37.608 ;
     RECT  0.06 37.608 0.275 37.728 ;
     RECT  0.084 37.728 0.275 37.752 ;
     RECT  0.06 37.752 0.275 37.824 ;
     RECT  0.084 37.824 0.275 37.848 ;
     RECT  0.06 37.848 0.275 37.968 ;
     RECT  0.084 37.968 0.275 37.992 ;
     RECT  0.06 37.992 0.275 38.112 ;
     RECT  0.084 38.112 0.275 38.136 ;
     RECT  0.06 38.136 0.275 38.256 ;
     RECT  0.084 38.256 0.275 38.28 ;
     RECT  0.06 38.28 0.275 38.4 ;
     RECT  0.084 38.4 0.275 38.424 ;
     RECT  0.06 38.424 0.275 38.496 ;
     RECT  0.084 38.496 0.275 38.52 ;
     RECT  0.06 38.52 0.275 38.64 ;
     RECT  0.084 38.64 0.275 38.664 ;
     RECT  0.06 38.664 0.275 38.784 ;
     RECT  0.084 38.784 0.275 38.808 ;
     RECT  0.06 38.808 0.275 38.928 ;
     RECT  0.084 38.928 0.275 38.952 ;
     RECT  0.06 38.952 0.275 39.024 ;
     RECT  0.084 39.024 0.275 39.048 ;
     RECT  0.06 39.048 0.275 39.168 ;
     RECT  0.084 39.168 0.275 39.192 ;
     RECT  0.06 39.192 0.275 39.312 ;
     RECT  0.084 39.312 0.275 39.336 ;
     RECT  0.06 39.336 0.275 39.456 ;
     RECT  0.084 39.456 0.275 39.48 ;
     RECT  0.06 39.48 0.275 39.6 ;
     RECT  0.084 39.6 0.275 39.624 ;
     RECT  0.06 39.624 0.275 39.696 ;
     RECT  0.084 39.696 0.275 39.72 ;
     RECT  0.06 39.72 0.275 39.84 ;
     RECT  0.084 39.84 0.275 39.864 ;
     RECT  0.06 39.864 0.275 39.984 ;
     RECT  0.084 39.984 0.275 40.008 ;
     RECT  0.06 40.008 0.275 40.128 ;
     RECT  0.084 40.128 0.275 40.152 ;
     RECT  0.06 40.152 0.275 40.272 ;
     RECT  0.084 40.272 0.275 40.296 ;
     RECT  0.06 40.296 0.275 40.368 ;
     RECT  0.084 40.368 0.275 40.392 ;
     RECT  0.06 40.392 0.275 40.512 ;
     RECT  0.084 40.512 0.275 40.536 ;
     RECT  0.06 40.536 0.275 40.656 ;
     RECT  0.084 40.656 0.275 40.68 ;
     RECT  0.06 40.68 0.275 40.8 ;
     RECT  0.084 40.8 0.275 40.824 ;
     RECT  0.06 40.824 0.275 40.896 ;
     RECT  0.084 40.896 0.275 40.92 ;
     RECT  0.06 40.92 0.275 41.04 ;
     RECT  0.084 41.04 0.275 41.064 ;
     RECT  0.06 41.064 0.275 41.184 ;
     RECT  0.084 41.184 0.275 41.208 ;
     RECT  0.06 41.208 0.275 41.328 ;
     RECT  0.084 41.328 0.275 41.352 ;
     RECT  0.06 41.352 0.275 41.472 ;
     RECT  0.084 41.472 0.275 41.496 ;
     RECT  0.06 41.496 0.275 41.568 ;
     RECT  0.084 41.568 0.275 41.592 ;
     RECT  0.06 41.592 0.275 41.712 ;
     RECT  0.084 41.712 0.275 41.736 ;
     RECT  0.06 41.736 0.275 41.856 ;
     RECT  0.084 41.856 0.275 41.88 ;
     RECT  0.06 41.88 0.275 42 ;
     RECT  0.084 42 0.275 42.024 ;
     RECT  0.06 42.024 0.275 42.144 ;
     RECT  0.084 42.144 0.275 42.168 ;
     RECT  0.275 1.2 1.573 42.168 ;
     RECT  1.573 0.576 1.793 42.168 ;
     RECT  1.793 1.584 1.865 42.168 ;
     RECT  1.793 0.576 2.293 0.6 ;
     RECT  2.293 0.192 2.333 0.6 ;
     RECT  2.333 0.192 2.357 0.216 ;
     RECT  2.357 0.144 2.401 0.216 ;
     RECT  2.401 0.048 2.723 0.216 ;
     RECT  2.723 0.048 4.777 0.168 ;
     RECT  4.777 0.048 4.853 0.6 ;
     RECT  4.853 0.144 4.883 0.6 ;
     RECT  1.865 1.728 5.357 42.168 ;
     RECT  5.357 1.728 5.429 23.88 ;
     RECT  5.357 24.912 5.429 42.168 ;
     RECT  5.429 1.728 5.437 19.704 ;
     RECT  5.429 25.008 5.573 42.168 ;
     RECT  5.437 1.776 5.789 19.704 ;
     RECT  4.883 0.144 5.893 0.216 ;
     RECT  5.893 0.144 5.989 0.264 ;
     RECT  5.989 0.144 6.325 0.312 ;
     RECT  6.325 0.096 6.409 0.312 ;
     RECT  5.789 2.208 6.685 19.704 ;
     RECT  5.429 20.736 6.685 23.88 ;
     RECT  6.685 2.208 6.829 23.88 ;
     RECT  5.573 25.008 6.829 42.024 ;
     RECT  6.829 2.208 6.853 42.024 ;
     RECT  6.409 0.144 7.225 0.312 ;
     RECT  6.853 1.728 7.225 42.024 ;
     RECT  7.225 0.144 7.481 42.024 ;
     RECT  7.481 0.144 7.859 41.052 ;
     RECT  7.859 1.728 7.912 41.052 ;
     RECT  7.859 0.144 8.197 0.216 ;
     RECT  7.912 1.728 8.237 40.968 ;
     RECT  8.197 0.096 8.345 0.216 ;
     RECT  8.345 0.144 8.38 0.216 ;
     RECT  8.38 0.144 8.483 0.168 ;
     RECT  8.237 1.728 9.425 40.92 ;
     RECT  9.425 1.728 10.289 35.544 ;
     RECT  10.289 1.728 10.361 33.432 ;
     RECT  9.425 36.864 10.397 40.92 ;
     RECT  10.289 34.704 10.465 35.544 ;
     RECT  10.397 36.864 10.465 40.824 ;
     RECT  10.465 34.704 10.865 40.824 ;
     RECT  10.865 36.816 11.189 40.824 ;
     RECT  10.865 34.704 11.365 35.544 ;
     RECT  11.365 34.32 11.401 35.544 ;
     RECT  11.189 37.056 11.513 40.824 ;
     RECT  11.401 34.176 11.837 35.544 ;
     RECT  11.837 34.176 11.873 35.448 ;
     RECT  10.361 1.728 11.977 33 ;
     RECT  11.605 0.144 12.083 0.168 ;
     RECT  11.977 1.152 12.409 33 ;
     RECT  12.409 1.152 12.419 33.048 ;
     RECT  11.513 37.056 12.481 40.776 ;
     RECT  12.481 36.864 12.697 40.776 ;
     RECT  11.873 34.176 12.985 35.352 ;
     RECT  12.419 1.728 13.045 33.048 ;
     RECT  12.985 34.08 13.045 35.352 ;
     RECT  12.697 36.864 13.093 40.968 ;
     RECT  13.045 1.728 13.208 35.352 ;
     RECT  13.093 36.816 13.208 40.968 ;
     RECT  13.208 1.728 13.312 41.052 ;
     RECT  13.093 0.144 13.333 0.168 ;
     RECT  13.312 1.728 13.504 40.968 ;
     RECT  13.333 0.144 13.561 0.456 ;
     RECT  13.504 1.728 13.601 29.592 ;
     RECT  13.561 0.096 13.619 0.456 ;
     RECT  13.619 0.096 13.667 0.264 ;
     RECT  13.601 2.88 13.673 29.592 ;
     RECT  13.504 30.576 13.889 40.968 ;
     RECT  13.889 30.576 13.925 40.872 ;
     RECT  13.673 3.024 13.961 29.592 ;
     RECT  13.925 30.576 14.285 40.488 ;
     RECT  13.601 1.728 14.713 1.848 ;
     RECT  13.961 3.024 14.713 3.048 ;
     RECT  14.285 30.768 14.753 40.488 ;
     RECT  13.961 4.176 14.867 29.592 ;
     RECT  14.713 1.728 14.929 3.048 ;
     RECT  14.867 4.176 14.929 22.776 ;
     RECT  14.867 23.904 15.001 29.592 ;
     RECT  14.753 32.544 15.365 40.44 ;
     RECT  14.929 1.728 15.409 22.776 ;
     RECT  15.365 37.008 15.437 40.44 ;
     RECT  15.409 2.88 15.509 22.776 ;
     RECT  15.509 4.032 15.683 22.776 ;
     RECT  15.001 23.904 15.793 29.736 ;
     RECT  14.753 30.768 15.793 31.224 ;
     RECT  15.683 4.176 16.009 22.776 ;
     RECT  15.793 23.904 16.009 31.224 ;
     RECT  16.009 4.176 16.019 31.224 ;
     RECT  15.437 37.008 16.115 38.904 ;
     RECT  15.437 40.032 16.193 40.44 ;
     RECT  16.193 40.032 16.301 40.296 ;
     RECT  16.019 4.56 16.405 31.224 ;
     RECT  15.365 32.544 16.405 35.448 ;
     RECT  16.405 4.56 16.481 35.448 ;
     RECT  16.115 37.008 16.513 37.608 ;
     RECT  16.513 36.72 16.553 37.608 ;
     RECT  16.405 39.36 16.553 39.384 ;
     RECT  16.481 34.416 16.877 35.448 ;
     RECT  16.481 4.56 17.017 33.288 ;
     RECT  16.553 36.72 17.125 36.744 ;
     RECT  17.125 36 17.171 36.744 ;
     RECT  17.017 4.08 17.345 33.288 ;
     RECT  17.345 4.56 17.507 33.288 ;
     RECT  16.877 34.416 17.561 34.824 ;
     RECT  15.509 2.88 17.629 3.048 ;
     RECT  17.561 34.704 17.953 34.824 ;
     RECT  17.171 36 17.953 36.216 ;
     RECT  17.507 29.424 18.061 33.288 ;
     RECT  15.409 1.728 18.469 1.8 ;
     RECT  17.507 4.56 18.565 28.152 ;
     RECT  18.061 29.424 18.565 33.624 ;
     RECT  18.469 1.728 18.608 1.848 ;
     RECT  17.629 2.88 18.608 3.576 ;
     RECT  18.565 4.56 18.608 33.624 ;
     RECT  17.953 34.704 18.608 36.216 ;
     RECT  18.608 1.728 18.712 41.052 ;
     RECT  18.712 1.728 18.904 40.782 ;
     RECT  18.853 0.288 18.997 0.312 ;
     RECT  18.997 0.192 19.043 0.312 ;
     RECT  19.043 0.192 19.139 0.216 ;
     RECT  18.904 34.464 19.145 36.12 ;
     RECT  19.145 34.464 19.235 36.072 ;
     RECT  18.904 20.016 19.289 33.288 ;
     RECT  19.289 23.568 19.361 33.288 ;
     RECT  18.904 2.88 19.397 18.84 ;
     RECT  19.397 2.88 19.657 16.344 ;
     RECT  19.657 3.216 19.901 16.344 ;
     RECT  19.397 17.76 20.113 18.84 ;
     RECT  19.289 20.016 20.113 22.584 ;
     RECT  18.904 1.728 20.245 1.8 ;
     RECT  20.113 17.76 20.261 22.584 ;
     RECT  19.901 3.936 20.284 16.344 ;
     RECT  20.245 1.728 20.321 1.848 ;
     RECT  19.235 35.136 20.369 36.072 ;
     RECT  20.261 18.768 20.405 22.584 ;
     RECT  19.361 23.568 20.437 31.992 ;
     RECT  19.361 33.264 20.437 33.288 ;
     RECT  20.437 33.264 20.473 33.864 ;
     RECT  20.369 35.136 20.473 35.928 ;
     RECT  20.437 23.568 20.509 32.04 ;
     RECT  20.473 33.264 20.509 35.928 ;
     RECT  20.509 23.568 20.531 35.928 ;
     RECT  20.531 34.752 20.557 35.208 ;
     RECT  20.405 19.344 20.653 22.584 ;
     RECT  20.531 23.568 20.653 33.432 ;
     RECT  20.261 17.76 20.761 17.784 ;
     RECT  20.557 34.896 20.837 35.208 ;
     RECT  20.653 19.344 20.945 33.432 ;
     RECT  20.837 35.184 20.981 35.208 ;
     RECT  20.761 17.616 21.049 17.784 ;
     RECT  20.941 3.456 21.089 3.48 ;
     RECT  20.945 33.408 21.089 33.432 ;
     RECT  20.284 4.704 21.157 16.344 ;
     RECT  21.049 17.568 21.157 17.784 ;
     RECT  20.321 1.728 21.232 1.896 ;
     RECT  21.157 4.704 21.301 17.784 ;
     RECT  21.232 1.68 21.347 1.896 ;
     RECT  20.945 19.344 21.377 32.28 ;
     RECT  21.377 20.016 21.395 32.28 ;
     RECT  21.347 1.728 21.404 1.896 ;
     RECT  21.301 4.608 21.733 17.784 ;
     RECT  21.404 1.728 21.829 2.28 ;
     RECT  21.395 23.088 22.205 32.28 ;
     RECT  21.733 4.56 22.313 17.784 ;
     RECT  21.829 1.728 22.453 2.904 ;
     RECT  22.313 4.608 22.46 17.784 ;
     RECT  22.46 4.608 22.777 18.216 ;
     RECT  22.453 1.728 22.849 2.952 ;
     RECT  21.395 20.016 22.921 22.056 ;
     RECT  22.205 23.088 22.921 31.8 ;
     RECT  22.777 4.608 22.993 18.408 ;
     RECT  22.921 20.016 23.317 31.8 ;
     RECT  22.849 1.728 23.353 3.288 ;
     RECT  22.993 4.608 23.353 18.552 ;
     RECT  23.749 0.528 23.939 0.552 ;
     RECT  23.353 1.728 24.008 18.552 ;
     RECT  23.317 19.872 24.008 31.8 ;
     RECT  24.008 1.728 24.112 41.052 ;
     RECT  24.112 1.728 24.304 40.782 ;
     RECT  24.304 1.728 24.581 17.64 ;
     RECT  24.581 4.752 24.617 17.64 ;
     RECT  24.304 18.768 24.617 31.656 ;
     RECT  24.617 13.056 24.653 17.64 ;
     RECT  24.617 4.752 24.977 12.024 ;
     RECT  24.617 18.768 25.157 18.792 ;
     RECT  24.653 13.104 25.373 17.64 ;
     RECT  24.977 4.752 25.593 9.096 ;
     RECT  24.617 19.776 25.628 31.656 ;
     RECT  25.373 17.616 25.667 17.64 ;
     RECT  25.628 19.344 25.697 31.656 ;
     RECT  25.697 19.344 25.715 22.824 ;
     RECT  25.373 13.104 25.733 16.44 ;
     RECT  25.593 3.936 25.945 9.096 ;
     RECT  24.977 10.128 25.945 12.024 ;
     RECT  25.733 13.104 25.993 13.992 ;
     RECT  25.945 3.936 26.003 12.024 ;
     RECT  26.003 3.936 26.057 7.992 ;
     RECT  26.003 9.36 26.125 12.024 ;
     RECT  25.693 18 26.129 18.168 ;
     RECT  25.697 23.808 26.197 31.656 ;
     RECT  24.581 1.728 26.209 2.904 ;
     RECT  26.209 2.88 26.237 2.904 ;
     RECT  26.197 23.808 26.309 31.8 ;
     RECT  25.993 13.536 26.381 13.992 ;
     RECT  26.125 9.36 26.525 12.552 ;
     RECT  26.209 1.728 26.627 1.896 ;
     RECT  26.309 31.104 26.705 31.8 ;
     RECT  25.715 19.584 26.737 22.824 ;
     RECT  26.309 23.808 26.737 29.928 ;
     RECT  26.057 5.712 26.957 7.992 ;
     RECT  25.733 15.024 27.169 16.44 ;
     RECT  26.525 9.552 27.173 12.552 ;
     RECT  26.129 18 27.349 18.024 ;
     RECT  26.737 19.584 27.349 29.928 ;
     RECT  27.169 15.024 27.457 16.92 ;
     RECT  27.349 18 27.493 29.928 ;
     RECT  26.705 31.104 27.493 31.224 ;
     RECT  26.057 3.936 27.533 4.584 ;
     RECT  27.493 18 27.533 31.224 ;
     RECT  27.457 14.88 27.541 16.92 ;
     RECT  27.173 10.368 27.637 12.552 ;
     RECT  26.381 13.536 27.637 13.8 ;
     RECT  27.541 14.88 27.709 17.016 ;
     RECT  27.637 10.368 27.745 13.8 ;
     RECT  27.709 14.784 27.745 17.016 ;
     RECT  27.745 10.368 27.781 17.016 ;
     RECT  27.533 18 27.781 18.408 ;
     RECT  27.781 10.368 27.916 18.408 ;
     RECT  26.627 1.728 27.961 1.848 ;
     RECT  27.533 19.632 28.001 31.224 ;
     RECT  27.961 1.728 28.115 2.232 ;
     RECT  27.916 10.368 28.141 13.848 ;
     RECT  27.916 14.88 28.181 18.408 ;
     RECT  28.001 19.728 28.211 31.224 ;
     RECT  28.205 2.88 28.288 2.904 ;
     RECT  28.141 9.504 28.289 13.848 ;
     RECT  26.957 5.712 28.364 7.752 ;
     RECT  28.364 5.712 28.405 7.8 ;
     RECT  28.288 2.88 28.897 2.952 ;
     RECT  27.533 3.936 28.897 3.96 ;
     RECT  28.115 1.728 29.077 1.752 ;
     RECT  28.897 2.88 29.077 3.96 ;
     RECT  28.181 18 29.084 18.408 ;
     RECT  28.211 19.728 29.084 22.056 ;
     RECT  28.405 5.712 29.149 8.808 ;
     RECT  29.077 1.728 29.221 3.96 ;
     RECT  28.289 10.368 29.221 13.848 ;
     RECT  28.181 14.88 29.221 16.968 ;
     RECT  28.211 23.088 29.269 31.224 ;
     RECT  29.149 32.352 29.269 32.376 ;
     RECT  29.221 1.728 29.408 4.008 ;
     RECT  29.149 5.472 29.408 8.808 ;
     RECT  29.221 10.368 29.408 16.968 ;
     RECT  29.084 18 29.408 22.056 ;
     RECT  29.269 23.088 29.408 32.376 ;
     RECT  29.408 1.728 29.512 41.052 ;
     RECT  29.221 0.144 29.603 0.168 ;
     RECT  29.512 1.728 29.704 40.782 ;
     RECT  29.704 9.12 29.843 9.192 ;
     RECT  29.704 12.288 29.909 12.312 ;
     RECT  29.704 10.416 30.197 11.256 ;
     RECT  29.704 13.344 30.197 16.68 ;
     RECT  29.704 1.728 30.233 4.008 ;
     RECT  30.197 13.92 30.233 16.68 ;
     RECT  29.704 32.496 30.233 32.52 ;
     RECT  30.049 43.056 30.323 43.08 ;
     RECT  30.233 14.496 30.341 16.68 ;
     RECT  29.704 20.112 30.377 20.856 ;
     RECT  29.843 9.12 30.449 9.144 ;
     RECT  29.704 29.328 30.449 29.592 ;
     RECT  29.704 22.032 30.515 27.48 ;
     RECT  30.233 3.408 30.557 4.008 ;
     RECT  29.704 5.04 30.557 7.176 ;
     RECT  30.341 14.496 30.665 15.48 ;
     RECT  29.704 31.2 30.697 31.224 ;
     RECT  30.557 3.984 30.737 4.008 ;
     RECT  30.377 20.208 30.769 20.856 ;
     RECT  30.515 23.808 30.769 27.48 ;
     RECT  29.704 34.368 30.769 34.392 ;
     RECT  30.341 16.656 30.805 16.68 ;
     RECT  30.769 34.368 30.805 34.584 ;
     RECT  30.757 0.144 30.899 0.168 ;
     RECT  30.197 10.416 30.917 10.44 ;
     RECT  29.704 18.72 30.949 18.744 ;
     RECT  30.557 6 30.985 7.176 ;
     RECT  30.769 23.808 30.985 27.672 ;
     RECT  30.805 16.656 31.061 17.064 ;
     RECT  30.949 18.72 31.061 18.792 ;
     RECT  31.061 18.72 31.093 18.744 ;
     RECT  30.985 23.808 31.129 27.96 ;
     RECT  30.449 29.568 31.129 29.592 ;
     RECT  30.697 30.672 31.129 31.224 ;
     RECT  30.805 34.368 31.129 34.68 ;
     RECT  31.093 18.576 31.133 18.744 ;
     RECT  31.133 18.576 31.141 18.6 ;
     RECT  30.985 6 31.169 7.944 ;
     RECT  31.061 16.656 31.169 16.68 ;
     RECT  30.769 20.208 31.169 21 ;
     RECT  31.129 34.368 31.309 35.016 ;
     RECT  30.665 15.024 31.349 15.48 ;
     RECT  31.129 23.808 31.349 28.536 ;
     RECT  31.141 18.192 31.381 18.6 ;
     RECT  31.169 20.208 31.381 20.856 ;
     RECT  31.129 29.568 31.417 31.224 ;
     RECT  31.417 29.568 31.484 31.272 ;
     RECT  30.985 32.736 31.489 32.76 ;
     RECT  31.349 26.208 31.529 28.536 ;
     RECT  31.484 29.568 31.571 31.368 ;
     RECT  31.169 6 31.619 7.416 ;
     RECT  31.532 8.88 31.619 8.904 ;
     RECT  31.381 17.952 31.619 18.6 ;
     RECT  30.515 22.032 31.633 22.776 ;
     RECT  31.349 23.808 31.633 25.176 ;
     RECT  31.349 15.456 31.637 15.48 ;
     RECT  31.529 26.592 31.637 28.536 ;
     RECT  31.453 4.512 31.669 4.536 ;
     RECT  31.619 6 31.669 6.888 ;
     RECT  31.309 33.936 31.705 35.016 ;
     RECT  31.381 19.824 31.709 20.856 ;
     RECT  30.233 1.728 31.763 2.28 ;
     RECT  31.637 26.736 31.777 28.536 ;
     RECT  31.571 29.568 31.777 31.272 ;
     RECT  31.619 18.576 31.781 18.6 ;
     RECT  31.777 26.736 31.781 31.272 ;
     RECT  31.705 33.888 31.849 35.016 ;
     RECT  31.849 33.888 31.964 35.208 ;
     RECT  31.964 33.888 32.005 35.304 ;
     RECT  32.005 33.888 32.051 36.12 ;
     RECT  29.704 39.456 32.051 39.48 ;
     RECT  31.849 14.256 32.065 14.28 ;
     RECT  31.763 1.728 32.177 1.848 ;
     RECT  31.669 4.512 32.177 6.888 ;
     RECT  31.633 22.032 32.177 25.176 ;
     RECT  31.861 2.88 32.209 2.904 ;
     RECT  31.709 20.208 32.252 20.856 ;
     RECT  32.177 22.032 32.252 22.824 ;
     RECT  32.281 18.816 32.293 18.84 ;
     RECT  32.065 13.488 32.357 14.28 ;
     RECT  31.489 32.448 32.389 32.76 ;
     RECT  32.051 33.888 32.389 33.96 ;
     RECT  32.293 18.816 32.401 19.128 ;
     RECT  32.209 2.88 32.429 3 ;
     RECT  32.177 23.808 32.429 25.176 ;
     RECT  32.317 12.336 32.569 12.36 ;
     RECT  32.357 13.488 32.569 13.512 ;
     RECT  32.252 20.208 32.573 22.824 ;
     RECT  32.573 20.208 32.857 20.664 ;
     RECT  31.781 26.736 32.857 27.672 ;
     RECT  31.781 28.704 32.857 31.272 ;
     RECT  32.857 26.736 32.861 31.272 ;
     RECT  32.341 16.512 32.965 16.536 ;
     RECT  30.997 10.128 33.013 10.152 ;
     RECT  32.861 26.736 33.041 31.224 ;
     RECT  32.569 12.336 33.059 13.512 ;
     RECT  33.059 12.768 33.113 13.512 ;
     RECT  32.051 34.992 33.113 36.12 ;
     RECT  32.573 21.648 33.149 22.824 ;
     RECT  33.041 26.736 33.185 31.176 ;
     RECT  32.177 1.728 33.205 1.8 ;
     RECT  32.965 16.416 33.212 16.536 ;
     RECT  32.177 5.472 33.253 6.888 ;
     RECT  32.677 7.872 33.253 7.896 ;
     RECT  33.212 16.416 33.301 17.064 ;
     RECT  33.253 5.472 33.397 7.896 ;
     RECT  32.429 2.88 33.445 2.904 ;
     RECT  32.389 32.448 33.541 33.96 ;
     RECT  33.397 5.472 33.644 7.992 ;
     RECT  33.349 18.192 33.649 18.216 ;
     RECT  33.644 5.376 33.713 7.992 ;
     RECT  33.713 5.376 33.731 8.568 ;
     RECT  33.649 18.192 33.733 18.84 ;
     RECT  33.731 6.24 33.74 8.568 ;
     RECT  33.445 2.88 33.749 2.952 ;
     RECT  33.74 6.24 33.779 8.904 ;
     RECT  33.013 10.128 33.781 10.728 ;
     RECT  32.429 23.952 33.797 25.176 ;
     RECT  33.113 35.136 33.797 36.12 ;
     RECT  33.779 7.344 33.827 8.904 ;
     RECT  33.749 2.832 33.833 2.952 ;
     RECT  33.779 6.24 33.833 6.264 ;
     RECT  33.301 16.32 33.865 17.064 ;
     RECT  33.865 15.792 33.925 17.064 ;
     RECT  33.925 15.36 33.937 17.064 ;
     RECT  33.733 18.192 33.937 18.408 ;
     RECT  33.781 4.224 34.001 4.344 ;
     RECT  33.541 32.208 34.081 33.96 ;
     RECT  33.797 35.136 34.081 35.88 ;
     RECT  33.149 21.648 34.213 22.776 ;
     RECT  33.797 23.952 34.213 24.648 ;
     RECT  33.205 1.728 34.297 1.848 ;
     RECT  33.937 15.36 34.46 18.408 ;
     RECT  34.001 3.408 34.693 4.344 ;
     RECT  34.297 1.728 34.808 2.28 ;
     RECT  34.693 3.408 34.808 4.536 ;
     RECT  33.827 7.344 34.808 8.184 ;
     RECT  33.781 10.128 34.808 10.92 ;
     RECT  34.46 15.312 34.808 18.408 ;
     RECT  32.857 19.824 34.808 20.664 ;
     RECT  34.213 21.648 34.808 24.648 ;
     RECT  33.937 25.68 34.808 25.704 ;
     RECT  33.185 26.736 34.808 30.888 ;
     RECT  34.081 32.208 34.808 35.88 ;
     RECT  34.808 1.728 34.912 41.052 ;
     RECT  34.912 1.728 35.104 40.782 ;
     RECT  35.104 34.176 35.201 34.2 ;
     RECT  34.837 0.144 35.219 0.168 ;
     RECT  35.104 2.88 35.219 3.144 ;
     RECT  35.219 2.88 35.237 2.904 ;
     RECT  35.104 15.312 35.26 16.584 ;
     RECT  35.104 4.128 35.309 4.344 ;
     RECT  35.104 6.864 35.381 8.184 ;
     RECT  35.104 32.304 35.381 32.472 ;
     RECT  35.104 25.536 35.453 29.064 ;
     RECT  35.453 27.552 35.555 29.064 ;
     RECT  35.453 25.536 35.561 26.184 ;
     RECT  35.561 26.16 35.596 26.184 ;
     RECT  35.104 9.408 35.651 10.728 ;
     RECT  35.104 21.792 35.705 23.352 ;
     RECT  35.104 1.728 35.795 1.896 ;
     RECT  35.381 6.864 35.813 7.992 ;
     RECT  35.555 27.552 35.849 27.672 ;
     RECT  35.849 27.552 35.921 27.576 ;
     RECT  35.555 29.04 35.993 29.064 ;
     RECT  35.104 17.664 36.029 20.664 ;
     RECT  36.029 17.664 36.035 20.568 ;
     RECT  35.813 6.912 36.317 7.992 ;
     RECT  36.035 17.664 36.323 20.52 ;
     RECT  36.181 13.152 36.371 13.176 ;
     RECT  35.705 21.792 36.425 22.872 ;
     RECT  35.104 30.864 36.457 30.888 ;
     RECT  35.381 32.448 36.457 32.472 ;
     RECT  36.323 17.664 36.467 19.944 ;
     RECT  36.467 19.68 36.505 19.944 ;
     RECT  35.26 15.312 36.517 15.336 ;
     RECT  35.26 16.32 36.517 16.584 ;
     RECT  36.425 21.792 36.517 22.488 ;
     RECT  36.517 15.312 36.524 16.584 ;
     RECT  36.467 17.664 36.524 18.264 ;
     RECT  36.524 15.312 36.604 18.264 ;
     RECT  36.517 21.696 36.604 22.488 ;
     RECT  35.651 9.408 36.611 10.152 ;
     RECT  36.604 16.416 36.611 18.264 ;
     RECT  36.604 21.792 36.611 22.488 ;
     RECT  36.565 0.576 36.649 0.6 ;
     RECT  36.241 5.184 36.673 5.208 ;
     RECT  36.611 16.416 36.677 16.44 ;
     RECT  35.104 14.208 36.709 14.232 ;
     RECT  36.604 15.312 36.709 15.432 ;
     RECT  36.709 14.208 36.745 15.432 ;
     RECT  36.457 30.864 36.749 32.472 ;
     RECT  36.317 7.968 36.781 7.992 ;
     RECT  35.104 24.48 36.785 24.504 ;
     RECT  36.611 17.856 36.929 18.264 ;
     RECT  36.745 13.632 36.995 15.432 ;
     RECT  36.781 6.816 37.109 6.84 ;
     RECT  36.611 9.6 37.109 10.152 ;
     RECT  36.749 32.448 37.109 32.472 ;
     RECT  36.781 7.968 37.217 8.568 ;
     RECT  36.995 13.632 37.217 14.808 ;
     RECT  36.611 21.792 37.217 21.816 ;
     RECT  35.795 1.728 37.237 1.848 ;
     RECT  36.749 30.864 37.261 31.368 ;
     RECT  37.217 13.632 37.331 14.52 ;
     RECT  36.929 17.856 37.331 17.88 ;
     RECT  37.261 30.864 37.349 30.888 ;
     RECT  37.349 30.72 37.433 30.888 ;
     RECT  37.237 1.728 37.525 1.944 ;
     RECT  37.109 10.128 37.649 10.152 ;
     RECT  37.525 1.728 37.685 2.904 ;
     RECT  37.433 30.864 37.685 30.888 ;
     RECT  37.685 1.728 37.724 2.856 ;
     RECT  37.105 0.48 37.789 0.504 ;
     RECT  37.724 1.68 37.789 2.856 ;
     RECT  36.673 5.184 37.793 5.736 ;
     RECT  37.217 7.968 37.861 8.472 ;
     RECT  36.505 19.92 37.937 19.944 ;
     RECT  37.789 0.48 37.955 2.856 ;
     RECT  37.955 0.48 38.117 1.848 ;
     RECT  37.955 2.832 38.153 2.856 ;
     RECT  37.331 13.632 38.195 13.656 ;
     RECT  38.108 19.632 38.195 19.656 ;
     RECT  37.793 5.184 38.261 5.208 ;
     RECT  38.117 0.48 38.333 1.8 ;
     RECT  37.861 7.344 38.333 8.472 ;
     RECT  38.333 7.968 38.477 8.472 ;
     RECT  38.333 0.48 38.627 1.704 ;
     RECT  38.477 8.448 38.765 8.472 ;
     RECT  38.509 6.288 38.771 6.312 ;
     RECT  38.509 5.136 39.059 5.16 ;
     RECT  38.627 0.48 39.149 1.128 ;
     RECT  39.149 0.096 39.233 1.128 ;
     RECT  39.233 0.144 39.305 1.128 ;
     RECT  39.305 0.48 39.587 1.128 ;
     RECT  39.587 1.056 39.731 1.128 ;
     RECT  39.301 3.408 39.875 3.432 ;
     RECT  39.731 1.056 40.019 1.08 ;
    LAYER M5 ;
     RECT  1.08 0.016 1.2 0.084 ;
     RECT  1.224 0.016 1.344 0.084 ;
     RECT  1.368 0.016 1.44 0.084 ;
     RECT  1.464 0.016 1.584 0.084 ;
     RECT  1.608 0.016 1.728 0.084 ;
     RECT  1.752 0.016 1.872 0.084 ;
     RECT  1.896 0.016 2.016 0.084 ;
     RECT  2.04 0.016 2.16 0.084 ;
     RECT  2.184 0.016 2.256 0.084 ;
     RECT  2.28 0.016 2.4 0.084 ;
     RECT  2.424 0.016 2.544 0.084 ;
     RECT  2.568 0.016 2.688 0.084 ;
     RECT  2.712 0.016 2.832 0.084 ;
     RECT  2.856 0.016 2.928 0.084 ;
     RECT  2.952 0.016 3.072 0.084 ;
     RECT  3.096 0.016 3.216 0.084 ;
     RECT  3.24 0.016 3.36 0.084 ;
     RECT  3.384 0.016 3.504 0.084 ;
     RECT  3.528 0.016 3.6 0.084 ;
     RECT  3.624 0.016 3.744 0.084 ;
     RECT  3.768 0.016 3.888 0.084 ;
     RECT  3.912 0.016 4.032 0.084 ;
     RECT  4.056 0.016 4.176 0.084 ;
     RECT  4.2 0.016 4.32 0.084 ;
     RECT  4.344 0.016 4.416 0.084 ;
     RECT  4.44 0.016 4.56 0.084 ;
     RECT  4.584 0.016 4.704 0.084 ;
     RECT  4.728 0.016 4.848 0.084 ;
     RECT  4.872 0.016 4.992 0.084 ;
     RECT  5.016 0.016 5.088 0.084 ;
     RECT  5.112 0.016 5.232 0.084 ;
     RECT  5.256 0.016 5.376 0.084 ;
     RECT  5.4 0.016 5.52 0.084 ;
     RECT  5.544 0.016 5.664 0.084 ;
     RECT  5.688 0.016 5.808 0.084 ;
     RECT  5.832 0.016 5.904 0.084 ;
     RECT  5.928 0.016 6.048 0.084 ;
     RECT  6.072 0.016 6.192 0.084 ;
     RECT  6.216 0.016 6.336 0.084 ;
     RECT  6.36 0.016 6.48 0.084 ;
     RECT  6.504 0.016 6.576 0.084 ;
     RECT  6.6 0.016 6.72 0.084 ;
     RECT  6.744 0.016 6.864 0.084 ;
     RECT  6.888 0.016 7.008 0.084 ;
     RECT  7.032 0.016 7.152 0.084 ;
     RECT  7.176 0.016 7.248 0.084 ;
     RECT  7.272 0.016 7.392 0.084 ;
     RECT  7.416 0.016 7.536 0.084 ;
     RECT  7.56 0.016 7.68 0.084 ;
     RECT  7.704 0.016 7.824 0.084 ;
     RECT  7.848 0.016 7.968 0.084 ;
     RECT  7.992 0.016 8.064 0.084 ;
     RECT  8.088 0.016 8.208 0.084 ;
     RECT  8.232 0.016 8.352 0.084 ;
     RECT  8.376 0.016 8.496 0.084 ;
     RECT  8.52 0.016 8.64 0.084 ;
     RECT  8.664 0.016 8.736 0.084 ;
     RECT  8.76 0.016 8.88 0.084 ;
     RECT  8.904 0.016 9.024 0.084 ;
     RECT  9.048 0.016 9.168 0.084 ;
     RECT  9.192 0.016 9.312 0.084 ;
     RECT  9.336 0.016 9.408 0.084 ;
     RECT  9.432 0.016 9.552 0.084 ;
     RECT  9.576 0.016 9.696 0.084 ;
     RECT  9.72 0.016 9.84 0.084 ;
     RECT  9.864 0.016 9.984 0.084 ;
     RECT  10.008 0.016 10.128 0.084 ;
     RECT  10.152 0.016 10.224 0.084 ;
     RECT  10.248 0.016 10.368 0.084 ;
     RECT  10.392 0.016 10.512 0.084 ;
     RECT  10.536 0.016 10.656 0.084 ;
     RECT  10.68 0.016 10.8 0.084 ;
     RECT  10.824 0.016 10.896 0.084 ;
     RECT  10.92 0.016 11.04 0.084 ;
     RECT  11.064 0.016 11.184 0.084 ;
     RECT  11.208 0.016 11.328 0.084 ;
     RECT  11.352 0.016 11.472 0.084 ;
     RECT  11.496 0.016 11.616 0.084 ;
     RECT  11.64 0.016 11.712 0.084 ;
     RECT  11.736 0.016 11.856 0.084 ;
     RECT  11.88 0.016 12 0.084 ;
     RECT  12.024 0.016 12.144 0.084 ;
     RECT  12.168 0.016 12.288 0.084 ;
     RECT  12.312 0.016 12.384 0.084 ;
     RECT  12.408 0.016 12.528 0.084 ;
     RECT  12.552 0.016 12.672 0.084 ;
     RECT  12.696 0.016 12.816 0.084 ;
     RECT  12.84 0.016 12.96 0.084 ;
     RECT  12.984 0.016 13.056 0.084 ;
     RECT  13.08 0.016 13.2 0.084 ;
     RECT  13.224 0.016 13.344 0.084 ;
     RECT  13.368 0.016 13.488 0.084 ;
     RECT  13.512 0.016 13.632 0.084 ;
     RECT  13.656 0.016 13.776 0.084 ;
     RECT  13.8 0.016 13.872 0.084 ;
     RECT  13.896 0.016 14.016 0.084 ;
     RECT  14.04 0.016 14.16 0.084 ;
     RECT  14.184 0.016 14.304 0.084 ;
     RECT  14.328 0.016 14.448 0.084 ;
     RECT  14.472 0.016 14.544 0.084 ;
     RECT  14.568 0.016 14.688 0.084 ;
     RECT  14.712 0.016 14.832 0.084 ;
     RECT  14.856 0.016 14.976 0.084 ;
     RECT  15 0.016 15.12 0.084 ;
     RECT  15.144 0.016 15.264 0.084 ;
     RECT  15.288 0.016 15.36 0.084 ;
     RECT  15.384 0.016 15.504 0.084 ;
     RECT  15.528 0.016 15.648 0.084 ;
     RECT  15.672 0.016 15.792 0.084 ;
     RECT  15.816 0.016 15.936 0.084 ;
     RECT  15.96 0.016 16.032 0.084 ;
     RECT  16.056 0.016 16.176 0.084 ;
     RECT  16.2 0.016 16.32 0.084 ;
     RECT  16.344 0.016 16.464 0.084 ;
     RECT  16.488 0.016 16.608 0.084 ;
     RECT  16.632 0.016 16.704 0.084 ;
     RECT  16.728 0.016 16.848 0.084 ;
     RECT  16.872 0.016 16.992 0.084 ;
     RECT  17.016 0.016 17.136 0.084 ;
     RECT  17.16 0.016 17.28 0.084 ;
     RECT  17.304 0.016 17.424 0.084 ;
     RECT  17.448 0.016 17.52 0.084 ;
     RECT  17.544 0.016 17.664 0.084 ;
     RECT  17.688 0.016 17.808 0.084 ;
     RECT  17.832 0.016 17.952 0.084 ;
     RECT  17.976 0.016 18.096 0.084 ;
     RECT  18.12 0.016 18.192 0.084 ;
     RECT  18.216 0.016 18.336 0.084 ;
     RECT  18.36 0.016 18.48 0.084 ;
     RECT  18.504 0.016 18.624 0.084 ;
     RECT  18.648 0.016 18.768 0.084 ;
     RECT  18.792 0.016 18.864 0.084 ;
     RECT  18.888 0.016 19.008 0.084 ;
     RECT  19.032 0.016 19.152 0.084 ;
     RECT  19.176 0.016 19.296 0.084 ;
     RECT  19.32 0.016 19.44 0.084 ;
     RECT  19.464 0.016 19.584 0.084 ;
     RECT  19.608 0.016 19.68 0.084 ;
     RECT  19.704 0.016 19.824 0.084 ;
     RECT  19.848 0.016 19.968 0.084 ;
     RECT  19.992 0.016 20.112 0.084 ;
     RECT  20.136 0.016 20.256 0.084 ;
     RECT  20.28 0.016 20.352 0.084 ;
     RECT  20.376 0.016 20.496 0.084 ;
     RECT  20.52 0.016 20.64 0.084 ;
     RECT  20.664 0.016 20.784 0.084 ;
     RECT  20.808 0.016 20.928 0.084 ;
     RECT  20.952 0.016 21.072 0.084 ;
     RECT  21.096 0.016 21.168 0.084 ;
     RECT  21.192 0.016 21.312 0.084 ;
     RECT  21.336 0.016 21.456 0.084 ;
     RECT  21.48 0.016 21.6 0.084 ;
     RECT  21.624 0.016 21.744 0.084 ;
     RECT  21.768 0.016 21.84 0.084 ;
     RECT  21.864 0.016 21.984 0.084 ;
     RECT  22.008 0.016 22.128 0.084 ;
     RECT  22.152 0.016 22.272 0.084 ;
     RECT  22.296 0.016 22.416 0.084 ;
     RECT  22.44 0.016 22.512 0.084 ;
     RECT  22.536 0.016 22.656 0.084 ;
     RECT  22.68 0.016 22.8 0.084 ;
     RECT  22.824 0.016 22.944 0.084 ;
     RECT  22.968 0.016 23.088 0.084 ;
     RECT  23.112 0.016 23.232 0.084 ;
     RECT  23.256 0.016 23.328 0.084 ;
     RECT  23.352 0.016 23.472 0.084 ;
     RECT  23.496 0.016 23.616 0.084 ;
     RECT  23.64 0.016 23.76 0.084 ;
     RECT  23.784 0.016 23.904 0.084 ;
     RECT  23.928 0.016 24 0.084 ;
     RECT  24.024 0.016 24.144 0.084 ;
     RECT  24.168 0.016 24.288 0.084 ;
     RECT  24.312 0.016 24.432 0.084 ;
     RECT  24.456 0.016 24.576 0.084 ;
     RECT  24.6 0.016 24.72 0.084 ;
     RECT  24.744 0.016 24.816 0.084 ;
     RECT  24.84 0.016 24.96 0.084 ;
     RECT  24.984 0.016 25.104 0.084 ;
     RECT  25.128 0.016 25.248 0.084 ;
     RECT  25.272 0.016 25.392 0.084 ;
     RECT  25.416 0.016 25.488 0.084 ;
     RECT  25.512 0.016 25.632 0.084 ;
     RECT  25.656 0.016 25.776 0.084 ;
     RECT  25.8 0.016 25.92 0.084 ;
     RECT  25.944 0.016 26.064 0.084 ;
     RECT  26.088 0.016 26.16 0.084 ;
     RECT  26.184 0.016 26.304 0.084 ;
     RECT  26.328 0.016 26.448 0.084 ;
     RECT  26.472 0.016 26.592 0.084 ;
     RECT  26.616 0.016 26.736 0.084 ;
     RECT  26.76 0.016 26.88 0.084 ;
     RECT  26.904 0.016 26.976 0.084 ;
     RECT  27 0.016 27.12 0.084 ;
     RECT  27.144 0.016 27.264 0.084 ;
     RECT  27.288 0.016 27.408 0.084 ;
     RECT  27.432 0.016 27.552 0.084 ;
     RECT  27.576 0.016 27.648 0.084 ;
     RECT  27.672 0.016 27.792 0.084 ;
     RECT  27.816 0.016 27.936 0.084 ;
     RECT  27.96 0.016 28.08 0.084 ;
     RECT  28.104 0.016 28.224 0.084 ;
     RECT  28.248 0.016 28.32 0.084 ;
     RECT  28.344 0.016 28.464 0.084 ;
     RECT  28.488 0.016 28.608 0.084 ;
     RECT  28.632 0.016 28.752 0.084 ;
     RECT  28.776 0.016 28.896 0.084 ;
     RECT  28.92 0.016 29.04 0.084 ;
     RECT  29.064 0.016 29.136 0.084 ;
     RECT  29.16 0.016 29.28 0.084 ;
     RECT  29.304 0.016 29.424 0.084 ;
     RECT  29.448 0.016 29.568 0.084 ;
     RECT  29.592 0.016 29.712 0.084 ;
     RECT  29.736 0.016 29.808 0.084 ;
     RECT  29.832 0.016 29.952 0.084 ;
     RECT  29.976 0.016 30.096 0.084 ;
     RECT  30.12 0.016 30.24 0.084 ;
     RECT  30.264 0.016 30.384 0.084 ;
     RECT  30.408 0.016 30.528 0.084 ;
     RECT  30.552 0.016 30.624 0.084 ;
     RECT  30.648 0.016 30.768 0.084 ;
     RECT  30.792 0.016 30.912 0.084 ;
     RECT  30.936 0.016 31.056 0.084 ;
     RECT  31.08 0.016 31.2 0.084 ;
     RECT  31.224 0.016 31.296 0.084 ;
     RECT  31.32 0.016 31.44 0.084 ;
     RECT  31.464 0.016 31.584 0.084 ;
     RECT  31.608 0.016 31.728 0.084 ;
     RECT  31.752 0.016 31.872 0.084 ;
     RECT  31.896 0.016 31.968 0.084 ;
     RECT  31.992 0.016 32.112 0.084 ;
     RECT  32.136 0.016 32.256 0.084 ;
     RECT  32.28 0.016 32.4 0.084 ;
     RECT  32.424 0.016 32.544 0.084 ;
     RECT  32.568 0.016 32.688 0.084 ;
     RECT  32.712 0.016 32.784 0.084 ;
     RECT  32.808 0.016 32.928 0.084 ;
     RECT  32.952 0.016 33.072 0.084 ;
     RECT  33.096 0.016 33.216 0.084 ;
     RECT  33.24 0.016 33.36 0.084 ;
     RECT  33.384 0.016 33.456 0.084 ;
     RECT  33.48 0.016 33.6 0.084 ;
     RECT  33.624 0.016 33.744 0.084 ;
     RECT  33.768 0.016 33.888 0.084 ;
     RECT  33.912 0.016 34.032 0.084 ;
     RECT  34.056 0.016 34.176 0.084 ;
     RECT  34.2 0.016 34.272 0.084 ;
     RECT  34.296 0.016 34.416 0.084 ;
     RECT  34.44 0.016 34.56 0.084 ;
     RECT  34.584 0.016 34.704 0.084 ;
     RECT  34.728 0.016 34.848 0.084 ;
     RECT  34.872 0.016 34.944 0.084 ;
     RECT  34.968 0.016 35.088 0.084 ;
     RECT  35.112 0.016 35.232 0.084 ;
     RECT  35.256 0.016 35.376 0.084 ;
     RECT  35.4 0.016 35.52 0.084 ;
     RECT  35.544 0.016 35.616 0.084 ;
     RECT  35.64 0.016 35.76 0.084 ;
     RECT  35.784 0.016 35.904 0.084 ;
     RECT  35.928 0.016 36.048 0.084 ;
     RECT  36.072 0.016 36.192 0.084 ;
     RECT  36.216 0.016 36.336 0.084 ;
     RECT  36.36 0.016 36.432 0.084 ;
     RECT  36.456 0.016 36.576 0.084 ;
     RECT  36.6 0.016 36.72 0.084 ;
     RECT  36.744 0.016 36.864 0.084 ;
     RECT  36.888 0.016 37.008 0.084 ;
     RECT  37.032 0.016 37.104 0.084 ;
     RECT  37.128 0.016 37.248 0.084 ;
     RECT  37.272 0.016 37.392 0.084 ;
     RECT  37.416 0.016 37.536 0.084 ;
     RECT  37.56 0.016 37.68 0.084 ;
     RECT  37.704 0.016 37.776 0.084 ;
     RECT  37.8 0.016 37.92 0.084 ;
     RECT  37.944 0.016 38.064 0.084 ;
     RECT  38.088 0.016 38.208 0.084 ;
     RECT  38.232 0.016 38.352 0.084 ;
     RECT  38.376 0.016 38.496 0.084 ;
     RECT  38.52 0.016 38.592 0.084 ;
     RECT  38.616 0.016 38.736 0.084 ;
     RECT  38.76 0.016 38.88 0.084 ;
     RECT  38.904 0.016 39.024 0.084 ;
     RECT  39.048 0.016 39.168 0.084 ;
     RECT  39.192 0.016 39.264 0.084 ;
     RECT  39.288 0.016 39.408 0.084 ;
     RECT  39.432 0.016 39.552 0.084 ;
     RECT  39.576 0.016 39.696 0.084 ;
     RECT  39.72 0.016 39.84 0.084 ;
     RECT  39.864 0.016 39.984 0.084 ;
     RECT  1.056 0.084 40.008 1.045 ;
     RECT  0.24 1.045 40.008 1.091 ;
     RECT  0.24 1.091 39.864 1.333 ;
     RECT  0.144 1.333 39.864 1.859 ;
     RECT  14.784 1.859 35.784 1.907 ;
     RECT  21.456 1.907 35.256 1.955 ;
     RECT  37.248 1.859 39.864 1.955 ;
     RECT  21.456 1.955 25.512 2.291 ;
     RECT  26.976 1.955 35.256 2.291 ;
     RECT  37.536 1.955 39.864 2.291 ;
     RECT  14.784 1.907 19.704 2.915 ;
     RECT  21.84 2.291 21.864 2.915 ;
     RECT  23.232 2.291 25.512 2.915 ;
     RECT  31.872 2.291 35.256 2.915 ;
     RECT  37.536 2.291 37.56 2.915 ;
     RECT  26.976 2.291 30.552 2.963 ;
     RECT  33.456 2.915 35.256 2.963 ;
     RECT  29.04 2.963 30.552 3.011 ;
     RECT  0.144 1.859 13.656 3.443 ;
     RECT  17.952 2.915 19.704 3.443 ;
     RECT  33.792 2.963 35.256 3.443 ;
     RECT  38.736 2.291 39.864 3.443 ;
     RECT  18.192 3.443 19.704 3.925 ;
     RECT  29.232 3.011 30.552 4.019 ;
     RECT  15.312 2.915 16.92 4.115 ;
     RECT  33.792 3.443 33.816 4.355 ;
     RECT  34.8 3.443 35.256 4.355 ;
     RECT  0.144 3.443 13.608 4.501 ;
     RECT  14.592 4.261 14.616 4.501 ;
     RECT  34.8 4.355 35.112 4.501 ;
     RECT  23.232 2.915 24.312 4.549 ;
     RECT  18.192 3.925 20.232 4.595 ;
     RECT  26.976 2.963 27.432 4.595 ;
     RECT  18.6 4.595 20.232 4.693 ;
     RECT  18.6 4.693 20.52 4.739 ;
     RECT  20.496 4.739 20.52 5.029 ;
     RECT  25.632 3.925 25.656 5.123 ;
     RECT  20.496 5.029 20.808 5.171 ;
     RECT  38.736 3.443 39.048 5.171 ;
     RECT  23.232 4.549 24.504 5.219 ;
     RECT  0.144 4.501 14.616 5.221 ;
     RECT  15.984 4.115 16.92 5.317 ;
     RECT  18.6 4.739 19.464 5.797 ;
     RECT  18.48 5.797 19.464 5.941 ;
     RECT  20.784 5.171 20.808 5.989 ;
     RECT  0.144 5.221 14.76 6.037 ;
     RECT  15.888 5.317 16.92 6.037 ;
     RECT  0.144 6.037 16.92 6.181 ;
     RECT  17.952 5.941 19.464 6.181 ;
     RECT  29.4 4.019 29.712 6.277 ;
     RECT  0.144 6.181 19.464 6.323 ;
     RECT  38.736 5.171 38.76 6.323 ;
     RECT  29.088 6.277 29.712 6.325 ;
     RECT  22.992 6.373 23.016 6.469 ;
     RECT  33.696 5.365 33.72 6.517 ;
     RECT  34.704 4.501 35.112 6.517 ;
     RECT  29.088 6.325 30.408 6.563 ;
     RECT  20.784 5.989 21.672 6.565 ;
     RECT  22.896 6.469 23.016 6.613 ;
     RECT  24 5.219 24.504 6.613 ;
     RECT  29.088 6.563 30.12 6.707 ;
     RECT  2.304 6.323 19.464 6.805 ;
     RECT  29.28 6.707 30.12 6.851 ;
     RECT  0.144 6.323 1.224 6.899 ;
     RECT  20.544 6.565 21.672 7.477 ;
     RECT  22.896 6.613 24.504 7.477 ;
     RECT  33.696 6.517 35.112 7.717 ;
     RECT  29.28 6.851 29.712 7.765 ;
     RECT  33.264 7.717 35.112 7.765 ;
     RECT  33.264 7.765 35.544 7.813 ;
     RECT  2.304 6.805 19.56 7.909 ;
     RECT  20.544 7.477 24.504 7.909 ;
     RECT  33.264 7.813 35.64 7.957 ;
     RECT  0.192 6.899 1.224 8.003 ;
     RECT  2.304 7.909 24.504 8.053 ;
     RECT  25.68 6.085 25.704 8.053 ;
     RECT  2.304 8.053 25.704 8.147 ;
     RECT  0.192 8.003 0.552 8.245 ;
     RECT  33.264 7.957 36.36 8.437 ;
     RECT  37.872 7.333 37.896 8.437 ;
     RECT  22.176 8.147 25.704 8.533 ;
     RECT  22.176 8.533 25.992 8.579 ;
     RECT  28.416 7.765 29.712 8.579 ;
     RECT  2.304 8.147 15.432 9.109 ;
     RECT  16.896 8.147 20.856 9.109 ;
     RECT  29.28 8.579 29.712 9.157 ;
     RECT  0.144 8.245 0.552 9.299 ;
     RECT  2.304 9.109 20.856 9.637 ;
     RECT  22.176 8.579 24.504 9.637 ;
     RECT  0.192 9.299 0.552 9.875 ;
     RECT  25.68 8.579 25.992 10.021 ;
     RECT  2.304 9.637 24.504 10.067 ;
     RECT  31.584 7.381 31.608 10.117 ;
     RECT  0.24 9.875 0.552 10.355 ;
     RECT  0.528 10.355 0.552 10.451 ;
     RECT  33.264 8.437 37.896 10.693 ;
     RECT  25.68 10.021 26.472 10.835 ;
     RECT  29.28 9.157 29.832 10.883 ;
     RECT  33.024 10.693 37.896 10.931 ;
     RECT  2.304 10.067 20.856 11.075 ;
     RECT  27.648 10.981 27.672 11.221 ;
     RECT  3.888 11.075 20.856 11.363 ;
     RECT  20.016 11.363 20.856 11.651 ;
     RECT  20.688 11.651 20.856 11.699 ;
     RECT  25.92 10.835 26.472 11.941 ;
     RECT  0.192 11.941 0.216 12.277 ;
     RECT  29.4 10.883 29.832 12.323 ;
     RECT  22.464 10.067 24.504 12.371 ;
     RECT  0.144 12.277 0.216 12.611 ;
     RECT  2.304 11.075 2.856 12.659 ;
     RECT  20.784 11.699 20.856 12.757 ;
     RECT  33.024 10.931 33.72 12.803 ;
     RECT  3.888 11.363 18.912 12.853 ;
     RECT  20.64 12.757 20.856 12.853 ;
     RECT  3.888 12.853 21.288 13.091 ;
     RECT  20.64 13.091 21.288 13.237 ;
     RECT  22.464 12.371 24.312 13.237 ;
     RECT  2.304 12.659 2.712 13.331 ;
     RECT  27.648 11.221 28.2 13.333 ;
     RECT  29.4 12.323 29.712 13.333 ;
     RECT  3.888 13.091 18.912 13.427 ;
     RECT  25.92 11.941 26.52 13.571 ;
     RECT  25.92 13.571 25.992 13.621 ;
     RECT  34.704 10.931 37.896 13.621 ;
     RECT  20.64 13.237 24.312 13.715 ;
     RECT  3.888 13.427 16.728 13.763 ;
     RECT  0.144 12.611 0.168 13.813 ;
     RECT  17.712 13.427 18.912 14.003 ;
     RECT  0.144 13.813 0.216 14.051 ;
     RECT  20.784 13.715 24.312 14.581 ;
     RECT  25.344 13.621 25.992 14.581 ;
     RECT  0.192 14.051 0.216 14.723 ;
     RECT  3.888 13.763 15.432 14.773 ;
     RECT  3.888 14.773 15.72 14.819 ;
     RECT  20.784 14.581 25.992 14.819 ;
     RECT  17.808 14.003 18.912 14.867 ;
     RECT  3.888 14.819 14.472 14.915 ;
     RECT  33.264 12.803 33.72 15.301 ;
     RECT  34.704 13.621 38.184 15.301 ;
     RECT  15.696 14.819 15.72 15.349 ;
     RECT  16.704 13.763 16.728 15.349 ;
     RECT  4.176 14.915 14.472 15.443 ;
     RECT  27.648 13.333 29.712 15.973 ;
     RECT  4.176 15.443 9.576 16.019 ;
     RECT  15.696 15.349 16.728 16.019 ;
     RECT  4.176 16.019 8.328 16.067 ;
     RECT  22.608 14.819 25.992 16.213 ;
     RECT  0.144 15.637 0.168 16.403 ;
     RECT  33.264 15.301 38.184 16.405 ;
     RECT  9.552 16.019 9.576 16.501 ;
     RECT  10.8 15.443 14.472 16.501 ;
     RECT  31.008 10.117 31.608 16.501 ;
     RECT  32.976 16.405 38.184 16.501 ;
     RECT  15.696 16.019 16.152 16.595 ;
     RECT  5.184 16.067 8.328 16.981 ;
     RECT  9.552 16.501 14.472 16.981 ;
     RECT  27.552 15.973 29.712 17.027 ;
     RECT  18.096 14.867 18.912 17.411 ;
     RECT  4.176 16.067 4.2 17.605 ;
     RECT  5.184 16.981 14.472 17.605 ;
     RECT  22.512 16.213 25.992 17.651 ;
     RECT  4.176 17.605 14.472 17.699 ;
     RECT  16.992 17.077 17.016 17.747 ;
     RECT  31.008 16.501 38.184 17.891 ;
     RECT  31.008 17.891 36.6 17.987 ;
     RECT  4.176 17.699 13.512 18.709 ;
     RECT  14.544 17.797 14.568 18.709 ;
     RECT  4.176 18.709 14.568 18.755 ;
     RECT  4.176 18.755 13.608 18.851 ;
     RECT  15.696 16.595 15.72 18.851 ;
     RECT  4.8 18.851 13.608 18.947 ;
     RECT  2.4 13.331 2.712 19.093 ;
     RECT  32.352 17.987 36.6 19.093 ;
     RECT  17.184 18.037 17.208 19.381 ;
     RECT  18.6 17.411 18.912 19.381 ;
     RECT  5.184 18.947 13.608 19.427 ;
     RECT  17.184 19.381 18.912 19.427 ;
     RECT  17.616 19.427 18.912 19.571 ;
     RECT  38.16 17.891 38.184 19.667 ;
     RECT  32.304 19.093 36.6 19.909 ;
     RECT  6.048 19.427 13.608 19.955 ;
     RECT  2.4 19.093 3.048 20.003 ;
     RECT  32.304 19.909 37.224 20.579 ;
     RECT  6.048 19.955 13.512 20.627 ;
     RECT  6.048 20.627 10.392 20.675 ;
     RECT  0.144 18.517 0.168 20.723 ;
     RECT  6.048 20.675 6.168 20.867 ;
     RECT  6.048 20.867 6.072 20.915 ;
     RECT  7.2 20.675 10.392 21.155 ;
     RECT  11.616 20.627 13.512 21.155 ;
     RECT  9.264 21.155 10.392 21.491 ;
     RECT  32.304 20.579 35.112 21.539 ;
     RECT  18.6 19.571 18.912 21.589 ;
     RECT  15.888 20.485 15.912 21.683 ;
     RECT  25.632 17.651 25.992 21.683 ;
     RECT  17.76 21.589 18.912 21.875 ;
     RECT  20.784 14.819 21.288 22.165 ;
     RECT  32.976 21.539 35.112 22.165 ;
     RECT  36.288 20.579 37.224 22.165 ;
     RECT  32.976 22.165 37.224 22.499 ;
     RECT  2.4 20.003 2.712 22.549 ;
     RECT  13.2 21.155 13.512 22.549 ;
     RECT  32.976 22.499 35.88 22.549 ;
     RECT  11.856 21.155 11.88 22.645 ;
     RECT  13.104 22.549 13.512 22.645 ;
     RECT  2.304 22.549 2.712 22.739 ;
     RECT  7.2 21.155 8.112 22.741 ;
     RECT  11.856 22.645 13.512 22.741 ;
     RECT  27.648 17.027 29.712 22.741 ;
     RECT  31.008 17.987 31.176 22.741 ;
     RECT  11.856 22.741 13.608 22.787 ;
     RECT  27.648 22.741 31.176 22.787 ;
     RECT  9.264 21.491 9.576 22.835 ;
     RECT  6.672 22.741 8.112 22.883 ;
     RECT  32.688 22.549 35.88 22.883 ;
     RECT  14.832 22.165 14.856 22.979 ;
     RECT  27.648 22.787 27.672 23.125 ;
     RECT  17.472 22.501 17.496 23.365 ;
     RECT  18.6 21.875 18.912 23.365 ;
     RECT  13.2 22.787 13.608 23.411 ;
     RECT  20.784 22.165 21.384 23.411 ;
     RECT  17.472 23.365 18.912 23.509 ;
     RECT  10.752 22.453 10.776 24.277 ;
     RECT  11.856 22.787 11.88 24.277 ;
     RECT  10.752 24.277 11.88 24.323 ;
     RECT  9.312 22.835 9.576 24.419 ;
     RECT  9.552 24.419 9.576 24.467 ;
     RECT  27.6 23.125 27.672 24.469 ;
     RECT  28.992 22.787 31.176 24.469 ;
     RECT  20.16 23.653 20.184 24.515 ;
     RECT  22.512 17.651 24.6 24.611 ;
     RECT  16.512 23.509 18.912 24.659 ;
     RECT  17.472 24.659 18.912 24.899 ;
     RECT  21.264 23.411 21.384 25.139 ;
     RECT  10.752 24.323 11.64 25.235 ;
     RECT  25.968 21.683 25.992 25.573 ;
     RECT  5.184 22.165 5.208 25.715 ;
     RECT  27.6 24.469 31.176 25.715 ;
     RECT  32.688 22.883 35.112 26.149 ;
     RECT  28.992 25.715 31.176 26.197 ;
     RECT  25.776 25.573 25.992 26.243 ;
     RECT  0.144 26.197 0.168 26.339 ;
     RECT  11.952 26.053 11.976 26.773 ;
     RECT  21.264 25.139 21.288 26.773 ;
     RECT  22.848 24.611 24.6 26.773 ;
     RECT  28.992 26.197 31.416 27.107 ;
     RECT  6.672 22.883 6.696 27.253 ;
     RECT  6.576 27.253 6.696 27.299 ;
     RECT  21.264 26.773 24.6 27.395 ;
     RECT  25.968 26.243 25.992 27.733 ;
     RECT  13.2 23.411 13.512 27.877 ;
     RECT  31.152 27.107 31.416 27.971 ;
     RECT  32.688 26.149 35.544 28.211 ;
     RECT  18.6 24.899 18.912 28.309 ;
     RECT  21.264 27.395 24.312 28.451 ;
     RECT  27.6 25.715 27.672 28.451 ;
     RECT  17.472 24.899 17.496 28.453 ;
     RECT  0.192 28.357 0.216 28.499 ;
     RECT  17.376 28.453 17.496 28.499 ;
     RECT  13.2 27.877 14.28 28.547 ;
     RECT  31.152 27.971 31.176 28.547 ;
     RECT  11.856 26.773 11.976 28.741 ;
     RECT  11.808 28.741 11.976 28.787 ;
     RECT  25.488 27.733 25.992 28.981 ;
     RECT  7.8 22.883 8.112 29.221 ;
     RECT  17.376 28.499 17.4 29.509 ;
     RECT  18.6 28.309 19.656 29.509 ;
     RECT  0.144 29.317 0.168 29.603 ;
     RECT  7.8 29.221 9.096 29.699 ;
     RECT  17.376 29.509 19.656 29.699 ;
     RECT  23.664 28.451 24.312 29.699 ;
     RECT  25.392 28.981 25.992 30.275 ;
     RECT  28.992 27.107 29.712 30.275 ;
     RECT  18.192 29.699 18.912 30.371 ;
     RECT  21.264 28.451 22.2 30.563 ;
     RECT  37.2 22.499 37.224 30.709 ;
     RECT  13.2 28.547 13.512 30.757 ;
     RECT  27.648 28.451 27.672 30.803 ;
     RECT  29.088 30.275 29.712 30.851 ;
     RECT  37.2 30.709 37.416 30.853 ;
     RECT  32.688 28.211 35.112 30.899 ;
     RECT  36.48 30.853 37.416 30.899 ;
     RECT  11.808 28.787 11.832 30.995 ;
     RECT  19.92 30.133 19.944 31.139 ;
     RECT  17.136 30.661 17.16 31.379 ;
     RECT  21.264 30.563 21.816 31.379 ;
     RECT  25.968 30.275 25.992 31.379 ;
     RECT  31.536 30.661 31.56 31.379 ;
     RECT  36.48 30.899 37.224 31.379 ;
     RECT  2.4 22.739 2.712 31.381 ;
     RECT  2.4 31.381 2.808 31.571 ;
     RECT  9.648 30.805 9.672 31.619 ;
     RECT  21.072 31.381 21.096 31.955 ;
     RECT  29.28 30.851 29.712 31.955 ;
     RECT  2.4 31.571 2.712 32.005 ;
     RECT  6.576 27.299 6.6 32.435 ;
     RECT  13.2 30.757 14.28 32.771 ;
     RECT  13.2 32.771 13.944 33.013 ;
     RECT  33.984 30.899 35.112 33.013 ;
     RECT  2.016 32.005 2.712 33.203 ;
     RECT  13.056 33.013 13.944 33.587 ;
     RECT  33.696 33.013 35.112 33.683 ;
     RECT  33.696 33.683 33.72 33.923 ;
     RECT  32.688 30.899 32.712 34.357 ;
     RECT  2.4 33.203 2.712 34.405 ;
     RECT  18.6 30.371 18.912 34.453 ;
     RECT  2.064 34.405 2.712 34.547 ;
     RECT  15.984 34.117 16.008 35.123 ;
     RECT  0.144 34.933 0.168 35.219 ;
     RECT  13.2 33.587 13.944 35.315 ;
     RECT  18.6 34.453 19.224 35.315 ;
     RECT  32.016 34.357 32.712 35.363 ;
     RECT  2.4 34.547 2.712 35.797 ;
     RECT  20.496 33.829 20.52 35.939 ;
     RECT  6.384 35.317 6.408 35.987 ;
     RECT  10.752 25.235 10.776 36.421 ;
     RECT  2.304 35.797 2.712 36.469 ;
     RECT  17.136 35.989 17.16 36.755 ;
     RECT  2.016 36.469 2.712 36.851 ;
     RECT  10.656 36.421 10.776 37.621 ;
     RECT  13.2 35.315 13.704 37.667 ;
     RECT  2.4 36.851 2.712 38.197 ;
     RECT  3.936 38.197 3.96 38.531 ;
     RECT  2.304 38.197 2.712 38.675 ;
     RECT  16.08 37.573 16.104 38.915 ;
     RECT  0.144 39.013 0.168 39.155 ;
     RECT  10.272 37.621 10.776 39.395 ;
     RECT  32.016 35.363 32.04 39.491 ;
     RECT  13.2 37.667 13.512 39.637 ;
     RECT  7.8 29.699 8.112 39.685 ;
     RECT  6.816 39.685 8.112 39.827 ;
     RECT  2.4 38.675 2.712 40.501 ;
     RECT  13.056 39.637 13.512 40.883 ;
     RECT  2.304 40.501 2.712 40.979 ;
     RECT  2.4 40.979 2.712 41.049 ;
     RECT  7.8 39.827 8.112 41.049 ;
     RECT  13.2 40.883 13.512 41.049 ;
     RECT  18.6 35.315 18.912 41.049 ;
     RECT  24 29.699 24.312 41.049 ;
     RECT  29.4 31.955 29.712 41.049 ;
     RECT  34.8 33.683 35.112 41.049 ;
     RECT  2.4 41.049 2.52 41.063 ;
     RECT  7.8 41.049 7.92 41.063 ;
     RECT  13.2 41.049 13.32 41.063 ;
     RECT  18.6 41.049 18.72 41.063 ;
     RECT  24 41.049 24.12 41.063 ;
     RECT  29.4 41.049 29.52 41.063 ;
     RECT  34.8 41.049 34.92 41.063 ;
     RECT  13.656 1.859 14.784 2.915 ;
     RECT  35.784 1.859 37.248 1.907 ;
     RECT  25.512 1.955 26.976 2.915 ;
     RECT  21.864 2.291 23.232 2.915 ;
     RECT  30.552 2.291 31.872 2.915 ;
     RECT  37.56 2.291 38.736 2.915 ;
     RECT  13.656 2.915 15.312 3.443 ;
     RECT  16.92 2.915 17.952 3.443 ;
     RECT  24.312 2.915 26.976 3.925 ;
     RECT  13.608 3.443 15.312 4.115 ;
     RECT  16.92 3.443 18.192 4.595 ;
     RECT  33.816 3.443 34.8 4.355 ;
     RECT  24.312 3.925 25.632 4.549 ;
     RECT  25.656 3.925 26.976 4.595 ;
     RECT  13.608 4.115 15.984 4.261 ;
     RECT  13.608 4.261 14.592 4.501 ;
     RECT  14.616 4.261 15.984 5.221 ;
     RECT  33.792 4.355 34.8 4.501 ;
     RECT  33.792 4.501 34.704 5.365 ;
     RECT  24.504 4.549 25.632 5.123 ;
     RECT  16.92 4.595 18.6 5.797 ;
     RECT  25.656 4.595 25.704 5.123 ;
     RECT  19.464 4.739 20.496 5.171 ;
     RECT  24.504 5.123 25.704 6.085 ;
     RECT  19.464 5.171 20.784 6.565 ;
     RECT  23.232 5.219 24 6.373 ;
     RECT  14.76 5.221 15.984 5.317 ;
     RECT  14.76 5.317 15.888 6.037 ;
     RECT  33.72 5.365 34.704 6.517 ;
     RECT  16.92 5.797 18.48 5.941 ;
     RECT  16.92 5.941 17.952 6.181 ;
     RECT  24.504 6.085 25.68 8.053 ;
     RECT  1.224 6.323 2.304 8.003 ;
     RECT  21.672 6.373 22.992 6.469 ;
     RECT  23.016 6.373 24 6.613 ;
     RECT  21.672 6.469 22.896 7.477 ;
     RECT  19.464 6.565 20.544 6.805 ;
     RECT  29.088 6.707 29.28 7.765 ;
     RECT  19.56 6.805 20.544 7.909 ;
     RECT  0.144 6.899 0.192 8.245 ;
     RECT  36.36 7.957 37.872 8.437 ;
     RECT  15.432 8.147 16.896 9.109 ;
     RECT  20.856 8.147 22.176 9.637 ;
     RECT  24.504 8.579 25.68 10.835 ;
     RECT  29.832 10.117 31.008 12.323 ;
     RECT  31.608 10.693 33.024 12.803 ;
     RECT  24.504 10.835 25.92 12.371 ;
     RECT  29.28 10.883 29.4 11.221 ;
     RECT  33.72 10.931 34.704 15.301 ;
     RECT  26.472 10.981 27.648 11.941 ;
     RECT  2.856 11.075 3.888 12.659 ;
     RECT  28.2 11.221 29.4 13.333 ;
     RECT  18.912 11.363 20.016 11.651 ;
     RECT  18.912 11.651 20.688 11.699 ;
     RECT  18.912 11.699 20.784 12.757 ;
     RECT  26.52 11.941 27.648 13.571 ;
     RECT  29.712 12.323 31.008 22.741 ;
     RECT  24.312 12.371 25.92 13.621 ;
     RECT  0.168 12.611 0.216 13.813 ;
     RECT  2.712 12.659 3.888 14.915 ;
     RECT  18.912 12.757 20.64 12.853 ;
     RECT  21.288 12.853 22.464 13.237 ;
     RECT  16.728 13.427 17.712 14.003 ;
     RECT  24.312 13.621 25.344 14.581 ;
     RECT  15.432 13.763 16.704 14.773 ;
     RECT  16.728 14.003 17.808 14.867 ;
     RECT  15.72 14.773 16.704 15.349 ;
     RECT  14.472 14.819 15.696 17.699 ;
     RECT  21.288 14.819 22.608 16.213 ;
     RECT  16.728 14.867 18.096 16.019 ;
     RECT  2.712 14.915 4.176 18.851 ;
     RECT  9.576 15.443 10.8 16.501 ;
     RECT  8.328 16.019 9.552 16.981 ;
     RECT  16.152 16.019 18.096 16.595 ;
     RECT  4.2 16.067 5.184 17.605 ;
     RECT  21.288 16.213 22.512 22.165 ;
     RECT  31.608 16.405 32.976 16.501 ;
     RECT  15.72 16.595 18.096 17.077 ;
     RECT  15.72 17.077 16.992 17.747 ;
     RECT  17.016 17.077 18.096 17.411 ;
     RECT  17.016 17.411 18.6 17.747 ;
     RECT  24.6 17.651 25.632 21.683 ;
     RECT  13.512 17.699 15.696 17.797 ;
     RECT  15.72 17.747 18.6 18.037 ;
     RECT  13.512 17.797 14.544 18.709 ;
     RECT  14.568 17.797 15.696 18.755 ;
     RECT  31.176 17.987 32.352 19.093 ;
     RECT  15.72 18.037 17.184 18.851 ;
     RECT  17.208 18.037 18.6 19.381 ;
     RECT  2.712 18.851 3.048 19.093 ;
     RECT  31.176 19.093 32.304 21.539 ;
     RECT  35.112 20.579 36.288 22.165 ;
     RECT  10.392 20.627 11.616 21.155 ;
     RECT  6.168 20.675 7.2 20.867 ;
     RECT  6.072 20.867 7.2 20.915 ;
     RECT  8.112 21.155 9.264 22.835 ;
     RECT  10.392 21.155 11.856 21.491 ;
     RECT  11.88 21.155 13.2 22.549 ;
     RECT  9.576 21.491 11.856 22.453 ;
     RECT  31.176 21.539 32.976 22.549 ;
     RECT  24.6 21.683 25.968 25.573 ;
     RECT  17.76 21.875 18.6 22.501 ;
     RECT  13.512 22.165 14.832 22.741 ;
     RECT  21.384 22.165 22.512 24.611 ;
     RECT  9.576 22.453 10.752 24.467 ;
     RECT  10.776 22.453 11.856 24.277 ;
     RECT  35.88 22.499 37.2 22.883 ;
     RECT  17.496 22.501 18.6 23.365 ;
     RECT  11.88 22.549 13.104 22.645 ;
     RECT  31.176 22.549 32.688 26.197 ;
     RECT  5.208 22.741 6.672 25.715 ;
     RECT  13.608 22.741 14.832 22.979 ;
     RECT  11.88 22.787 13.2 24.323 ;
     RECT  27.672 22.787 28.992 24.469 ;
     RECT  8.112 22.835 9.312 24.419 ;
     RECT  6.696 22.883 7.8 27.299 ;
     RECT  20.784 23.411 21.264 23.653 ;
     RECT  18.912 23.653 20.16 24.515 ;
     RECT  20.184 23.653 21.264 24.515 ;
     RECT  8.112 24.419 9.552 24.467 ;
     RECT  21.384 24.611 22.848 25.139 ;
     RECT  17.496 24.899 18.6 28.499 ;
     RECT  10.776 25.235 11.64 26.053 ;
     RECT  24.6 25.573 25.776 26.243 ;
     RECT  27.672 25.715 28.992 30.275 ;
     RECT  10.776 26.053 11.952 26.773 ;
     RECT  11.976 26.053 13.2 28.787 ;
     RECT  31.416 26.197 32.688 27.971 ;
     RECT  24.6 26.243 25.968 27.395 ;
     RECT  10.776 26.773 11.856 28.741 ;
     RECT  29.712 27.107 31.152 28.547 ;
     RECT  6.6 27.299 7.8 32.435 ;
     RECT  24.312 27.395 25.968 27.733 ;
     RECT  24.312 27.733 25.488 28.981 ;
     RECT  31.176 27.971 32.688 28.547 ;
     RECT  22.2 28.451 23.664 29.699 ;
     RECT  17.4 28.499 18.6 29.509 ;
     RECT  10.776 28.741 11.808 30.995 ;
     RECT  11.832 28.787 13.2 30.995 ;
     RECT  24.312 28.981 25.392 30.275 ;
     RECT  17.376 29.699 18.192 30.371 ;
     RECT  18.912 29.699 19.656 30.133 ;
     RECT  18.912 30.133 19.92 31.139 ;
     RECT  19.944 30.133 21.264 31.139 ;
     RECT  27.672 30.275 29.088 30.803 ;
     RECT  17.376 30.371 18.6 30.661 ;
     RECT  17.16 30.661 18.6 31.379 ;
     RECT  31.56 30.661 32.688 31.379 ;
     RECT  9.672 30.805 10.752 31.619 ;
     RECT  35.112 30.853 36.48 31.379 ;
     RECT  32.712 30.899 33.984 33.013 ;
     RECT  21.072 31.139 21.264 31.379 ;
     RECT  21.072 31.379 21.096 31.381 ;
     RECT  32.712 33.013 33.696 33.923 ;
     RECT  2.064 33.203 2.4 34.405 ;
     RECT  33.72 33.683 34.8 33.923 ;
     RECT  19.224 34.453 20.496 35.315 ;
     RECT  2.304 34.547 2.4 35.797 ;
     RECT  6.408 35.317 7.8 35.987 ;
     RECT  17.16 35.989 18.6 36.755 ;
     RECT  2.304 36.851 2.4 38.197 ;
     RECT  2.712 38.197 3.936 38.531 ;
  END
END qkd_ctrl_pc_ecc_child
END LIBRARY
